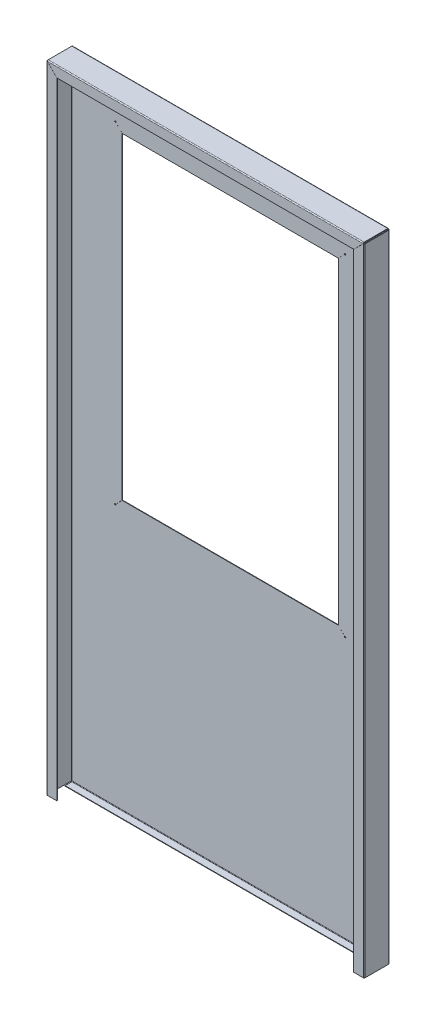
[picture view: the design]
ISO-10303-21;
HEADER;
FILE_DESCRIPTION(('STEP AP214'),'2;1');
FILE_NAME('part.step','',(''),(''),'','','');
FILE_SCHEMA(('AUTOMOTIVE_DESIGN { 1 0 10303 214 1 1 1 1 }'));
ENDSEC;
DATA;
#1=APPLICATION_CONTEXT('core data for automotive mechanical design processes');
#2=APPLICATION_PROTOCOL_DEFINITION('international standard','automotive_design',2000,#1);
#3=PRODUCT_CONTEXT('',#1,'mechanical');
#4=PRODUCT('Part','Part','',(#3));
#5=PRODUCT_RELATED_PRODUCT_CATEGORY('part','',(#4));
#6=PRODUCT_DEFINITION_FORMATION('','',#4);
#7=PRODUCT_DEFINITION_CONTEXT('part definition',#1,'design');
#8=PRODUCT_DEFINITION('design','',#6,#7);
#9=PRODUCT_DEFINITION_SHAPE('','',#8);
#10=(LENGTH_UNIT() NAMED_UNIT(*) SI_UNIT(.MILLI.,.METRE.));
#11=(NAMED_UNIT(*) PLANE_ANGLE_UNIT() SI_UNIT($,.RADIAN.));
#12=(NAMED_UNIT(*) SI_UNIT($,.STERADIAN.) SOLID_ANGLE_UNIT());
#13=UNCERTAINTY_MEASURE_WITH_UNIT(LENGTH_MEASURE(1.E-05),#10,'distance_accuracy_value','');
#14=(GEOMETRIC_REPRESENTATION_CONTEXT(3) GLOBAL_UNCERTAINTY_ASSIGNED_CONTEXT((#13)) GLOBAL_UNIT_ASSIGNED_CONTEXT((#10,
#11,#12)) REPRESENTATION_CONTEXT('',''));
#15=CARTESIAN_POINT('',(0.,0.,0.));
#16=DIRECTION('',(0.,0.,1.));
#17=DIRECTION('',(1.,0.,0.));
#18=AXIS2_PLACEMENT_3D('',#15,#16,#17);
#19=CARTESIAN_POINT('',(0.,1000.,0.75));
#20=DIRECTION('',(0.,0.,-1.));
#21=DIRECTION('',(-1.,0.,0.));
#22=AXIS2_PLACEMENT_3D('',#19,#20,#21);
#23=PLANE('',#22);
#24=DIRECTION('',(0.,1.,0.));
#25=VECTOR('',#24,1.);
#26=CARTESIAN_POINT('',(79.9999999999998,500.,0.750000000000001));
#27=LINE('',#26,#25);
#28=CARTESIAN_POINT('',(79.9999999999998,421.570710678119,0.750000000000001));
#29=VERTEX_POINT('',#28);
#30=CARTESIAN_POINT('',(79.9999999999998,921.429289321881,0.750000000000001));
#31=VERTEX_POINT('',#30);
#32=EDGE_CURVE('E499',#29,#31,#27,.T.);
#33=ORIENTED_EDGE('',*,*,#32,.T.);
#34=DIRECTION('',(0.707106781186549,-0.707106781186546,0.));
#35=VECTOR('',#34,1.);
#36=CARTESIAN_POINT('',(-58.6487222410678,1060.07801156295,0.750000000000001));
#37=LINE('',#36,#35);
#38=CARTESIAN_POINT('',(69.9208670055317,931.508422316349,0.750000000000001));
#39=VERTEX_POINT('',#38);
#40=EDGE_CURVE('E481',#39,#31,#37,.T.);
#41=ORIENTED_EDGE('',*,*,#40,.F.);
#42=CARTESIAN_POINT('',(69.2499999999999,932.25,0.750000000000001));
#43=DIRECTION('',(0.,0.,-1.));
#44=DIRECTION('',(-1.,0.,0.));
#45=AXIS2_PLACEMENT_3D('',#42,#43,#44);
#46=CIRCLE('',#45,0.999999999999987);
#47=CARTESIAN_POINT('',(69.9915776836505,931.579132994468,0.750000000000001));
#48=VERTEX_POINT('',#47);
#49=EDGE_CURVE('E490',#48,#39,#46,.F.);
#50=ORIENTED_EDGE('',*,*,#49,.F.);
#51=DIRECTION('',(0.707106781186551,-0.707106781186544,0.));
#52=VECTOR('',#51,1.);
#53=CARTESIAN_POINT('',(-58.5780115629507,1060.14872224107,0.750000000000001));
#54=LINE('',#53,#52);
#55=CARTESIAN_POINT('',(80.0707106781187,921.5,0.750000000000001));
#56=VERTEX_POINT('',#55);
#57=EDGE_CURVE('E189',#48,#56,#54,.T.);
#58=ORIENTED_EDGE('',*,*,#57,.T.);
#59=DIRECTION('',(1.,0.,0.));
#60=VECTOR('',#59,1.);
#61=CARTESIAN_POINT('',(-618.726733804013,921.5,0.750000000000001));
#62=LINE('',#61,#60);
#63=CARTESIAN_POINT('',(419.929289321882,921.5,0.750000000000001));
#64=VERTEX_POINT('',#63);
#65=EDGE_CURVE('E2033',#56,#64,#62,.T.);
#66=ORIENTED_EDGE('',*,*,#65,.T.);
#67=DIRECTION('',(-0.707106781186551,-0.707106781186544,0.));
#68=VECTOR('',#67,1.);
#69=CARTESIAN_POINT('',(-310.148722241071,191.421988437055,0.750000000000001));
#70=LINE('',#69,#68);
#71=CARTESIAN_POINT('',(430.008422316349,931.579132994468,0.750000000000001));
#72=VERTEX_POINT('',#71);
#73=EDGE_CURVE('E2035',#72,#64,#70,.T.);
#74=ORIENTED_EDGE('',*,*,#73,.F.);
#75=CARTESIAN_POINT('',(430.75,932.25,0.750000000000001));
#76=DIRECTION('',(0.,0.,-1.));
#77=DIRECTION('',(-1.,0.,0.));
#78=AXIS2_PLACEMENT_3D('',#75,#76,#77);
#79=CIRCLE('',#78,0.999999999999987);
#80=CARTESIAN_POINT('',(430.079132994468,931.508422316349,0.750000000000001));
#81=VERTEX_POINT('',#80);
#82=EDGE_CURVE('E2040',#72,#81,#79,.T.);
#83=ORIENTED_EDGE('',*,*,#82,.T.);
#84=DIRECTION('',(-0.707106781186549,-0.707106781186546,0.));
#85=VECTOR('',#84,1.);
#86=CARTESIAN_POINT('',(-310.07801156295,191.351277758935,0.750000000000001));
#87=LINE('',#86,#85);
#88=CARTESIAN_POINT('',(420.,921.429289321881,0.750000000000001));
#89=VERTEX_POINT('',#88);
#90=EDGE_CURVE('E2043',#81,#89,#87,.T.);
#91=ORIENTED_EDGE('',*,*,#90,.T.);
#92=DIRECTION('',(0.,1.,0.));
#93=VECTOR('',#92,1.);
#94=CARTESIAN_POINT('',(420.,500.,0.750000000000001));
#95=LINE('',#94,#93);
#96=CARTESIAN_POINT('',(420.,421.570710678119,0.750000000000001));
#97=VERTEX_POINT('',#96);
#98=EDGE_CURVE('E2046',#97,#89,#95,.T.);
#99=ORIENTED_EDGE('',*,*,#98,.F.);
#100=DIRECTION('',(-0.707106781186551,0.707106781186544,0.));
#101=VECTOR('',#100,1.);
#102=CARTESIAN_POINT('',(-138.578011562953,980.148722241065,0.750000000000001));
#103=LINE('',#102,#101);
#104=CARTESIAN_POINT('',(430.079132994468,411.491577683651,0.750000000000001));
#105=VERTEX_POINT('',#104);
#106=EDGE_CURVE('E2049',#105,#97,#103,.T.);
#107=ORIENTED_EDGE('',*,*,#106,.F.);
#108=CARTESIAN_POINT('',(430.75,410.75,0.750000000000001));
#109=DIRECTION('',(0.,0.,-1.));
#110=DIRECTION('',(-1.,0.,0.));
#111=AXIS2_PLACEMENT_3D('',#108,#109,#110);
#112=CIRCLE('',#111,1.00000000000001);
#113=CARTESIAN_POINT('',(430.008422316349,411.420867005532,0.750000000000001));
#114=VERTEX_POINT('',#113);
#115=EDGE_CURVE('E2052',#114,#105,#112,.F.);
#116=ORIENTED_EDGE('',*,*,#115,.F.);
#117=DIRECTION('',(-0.707106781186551,0.707106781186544,0.));
#118=VECTOR('',#117,1.);
#119=CARTESIAN_POINT('',(-138.648722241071,980.078011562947,0.750000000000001));
#120=LINE('',#119,#118);
#121=CARTESIAN_POINT('',(419.929289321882,421.5,0.750000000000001));
#122=VERTEX_POINT('',#121);
#123=EDGE_CURVE('E2055',#114,#122,#120,.T.);
#124=ORIENTED_EDGE('',*,*,#123,.T.);
#125=DIRECTION('',(1.,0.,0.));
#126=VECTOR('',#125,1.);
#127=CARTESIAN_POINT('',(-618.726733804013,421.5,0.750000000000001));
#128=LINE('',#127,#126);
#129=CARTESIAN_POINT('',(80.0707106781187,421.5,0.750000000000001));
#130=VERTEX_POINT('',#129);
#131=EDGE_CURVE('E2058',#130,#122,#128,.T.);
#132=ORIENTED_EDGE('',*,*,#131,.F.);
#133=DIRECTION('',(0.707106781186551,0.707106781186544,0.));
#134=VECTOR('',#133,1.);
#135=CARTESIAN_POINT('',(-230.078011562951,111.351277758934,0.750000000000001));
#136=LINE('',#135,#134);
#137=CARTESIAN_POINT('',(69.9915776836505,411.420867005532,0.750000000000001));
#138=VERTEX_POINT('',#137);
#139=EDGE_CURVE('E2061',#138,#130,#136,.T.);
#140=ORIENTED_EDGE('',*,*,#139,.F.);
#141=CARTESIAN_POINT('',(69.2499999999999,410.75,0.750000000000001));
#142=DIRECTION('',(0.,0.,-1.));
#143=DIRECTION('',(-1.,0.,0.));
#144=AXIS2_PLACEMENT_3D('',#141,#142,#143);
#145=CIRCLE('',#144,1.00000000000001);
#146=CARTESIAN_POINT('',(69.9208670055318,411.491577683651,0.750000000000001));
#147=VERTEX_POINT('',#146);
#148=EDGE_CURVE('E2064',#138,#147,#145,.T.);
#149=ORIENTED_EDGE('',*,*,#148,.T.);
#150=DIRECTION('',(0.707106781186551,0.707106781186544,0.));
#151=VECTOR('',#150,1.);
#152=CARTESIAN_POINT('',(-230.14872224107,111.421988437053,0.750000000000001));
#153=LINE('',#152,#151);
#154=EDGE_CURVE('E503',#147,#29,#153,.T.);
#155=ORIENTED_EDGE('',*,*,#154,.T.);
#156=EDGE_LOOP('',(#33,#41,#50,#58,#66,#74,#83,#91,#99,#107,#116,#124,#132,#140,#149,#155));
#157=FACE_BOUND('',#156,.T.);
#158=DIRECTION('',(0.,1.,0.));
#159=VECTOR('',#158,1.);
#160=CARTESIAN_POINT('',(498.5,1000.,0.750000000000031));
#161=LINE('',#160,#159);
#162=CARTESIAN_POINT('',(498.5,1000.,0.750000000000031));
#163=VERTEX_POINT('',#162);
#164=CARTESIAN_POINT('',(498.5,0.,0.750000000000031));
#165=VERTEX_POINT('',#164);
#166=EDGE_CURVE('E1001',#163,#165,#161,.F.);
#167=ORIENTED_EDGE('',*,*,#166,.F.);
#168=DIRECTION('',(-1.,0.,0.));
#169=VECTOR('',#168,1.);
#170=CARTESIAN_POINT('',(0.,1000.,0.75));
#171=LINE('',#170,#169);
#172=CARTESIAN_POINT('',(1.5,1000.,0.75));
#173=VERTEX_POINT('',#172);
#174=EDGE_CURVE('E13',#163,#173,#171,.T.);
#175=ORIENTED_EDGE('',*,*,#174,.T.);
#176=DIRECTION('',(0.,-1.,0.));
#177=VECTOR('',#176,1.);
#178=CARTESIAN_POINT('',(1.5,0.,0.75));
#179=LINE('',#178,#177);
#180=CARTESIAN_POINT('',(1.5,0.,0.75));
#181=VERTEX_POINT('',#180);
#182=EDGE_CURVE('E1046',#181,#173,#179,.F.);
#183=ORIENTED_EDGE('',*,*,#182,.F.);
#184=DIRECTION('',(1.,0.,0.));
#185=VECTOR('',#184,1.);
#186=CARTESIAN_POINT('',(0.,0.,0.75));
#187=LINE('',#186,#185);
#188=EDGE_CURVE('E182',#181,#165,#187,.T.);
#189=ORIENTED_EDGE('',*,*,#188,.T.);
#190=EDGE_LOOP('',(#167,#175,#183,#189));
#191=FACE_BOUND('',#190,.T.);
#192=ADVANCED_FACE('F175',(#157,#191),#23,.F.);
#193=CARTESIAN_POINT('',(0.,1000.,0.));
#194=DIRECTION('',(0.,0.,-1.));
#195=DIRECTION('',(-1.,0.,0.));
#196=AXIS2_PLACEMENT_3D('',#193,#194,#195);
#197=PLANE('',#196);
#198=DIRECTION('',(-0.707106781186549,0.707106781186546,0.));
#199=VECTOR('',#198,1.);
#200=CARTESIAN_POINT('',(-58.6487222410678,1060.07801156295,0.));
#201=LINE('',#200,#199);
#202=CARTESIAN_POINT('',(79.9999999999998,921.429289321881,0.));
#203=VERTEX_POINT('',#202);
#204=CARTESIAN_POINT('',(69.9208670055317,931.508422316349,0.));
#205=VERTEX_POINT('',#204);
#206=EDGE_CURVE('E197',#203,#205,#201,.T.);
#207=ORIENTED_EDGE('',*,*,#206,.F.);
#208=DIRECTION('',(0.,-1.,0.));
#209=VECTOR('',#208,1.);
#210=CARTESIAN_POINT('',(79.9999999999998,500.,0.));
#211=LINE('',#210,#209);
#212=CARTESIAN_POINT('',(79.9999999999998,421.570710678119,0.));
#213=VERTEX_POINT('',#212);
#214=EDGE_CURVE('E487',#203,#213,#211,.T.);
#215=ORIENTED_EDGE('',*,*,#214,.T.);
#216=DIRECTION('',(-0.707106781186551,-0.707106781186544,0.));
#217=VECTOR('',#216,1.);
#218=CARTESIAN_POINT('',(-230.14872224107,111.421988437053,0.));
#219=LINE('',#218,#217);
#220=CARTESIAN_POINT('',(69.9208670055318,411.491577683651,0.));
#221=VERTEX_POINT('',#220);
#222=EDGE_CURVE('E544',#213,#221,#219,.T.);
#223=ORIENTED_EDGE('',*,*,#222,.T.);
#224=CARTESIAN_POINT('',(69.2499999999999,410.75,0.));
#225=DIRECTION('',(0.,0.,-1.));
#226=DIRECTION('',(-1.,0.,0.));
#227=AXIS2_PLACEMENT_3D('',#224,#225,#226);
#228=CIRCLE('',#227,1.00000000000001);
#229=CARTESIAN_POINT('',(69.9915776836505,411.420867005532,0.));
#230=VERTEX_POINT('',#229);
#231=EDGE_CURVE('E541',#221,#230,#228,.F.);
#232=ORIENTED_EDGE('',*,*,#231,.T.);
#233=DIRECTION('',(-0.707106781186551,-0.707106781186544,0.));
#234=VECTOR('',#233,1.);
#235=CARTESIAN_POINT('',(-230.078011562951,111.351277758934,0.));
#236=LINE('',#235,#234);
#237=CARTESIAN_POINT('',(80.0707106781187,421.5,0.));
#238=VERTEX_POINT('',#237);
#239=EDGE_CURVE('E538',#238,#230,#236,.T.);
#240=ORIENTED_EDGE('',*,*,#239,.F.);
#241=DIRECTION('',(-1.,0.,0.));
#242=VECTOR('',#241,1.);
#243=CARTESIAN_POINT('',(-618.726733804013,421.5,0.));
#244=LINE('',#243,#242);
#245=CARTESIAN_POINT('',(419.929289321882,421.5,0.));
#246=VERTEX_POINT('',#245);
#247=EDGE_CURVE('E535',#246,#238,#244,.T.);
#248=ORIENTED_EDGE('',*,*,#247,.F.);
#249=DIRECTION('',(0.707106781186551,-0.707106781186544,0.));
#250=VECTOR('',#249,1.);
#251=CARTESIAN_POINT('',(-138.648722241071,980.078011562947,0.));
#252=LINE('',#251,#250);
#253=CARTESIAN_POINT('',(430.008422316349,411.420867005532,0.));
#254=VERTEX_POINT('',#253);
#255=EDGE_CURVE('E532',#246,#254,#252,.T.);
#256=ORIENTED_EDGE('',*,*,#255,.T.);
#257=CARTESIAN_POINT('',(430.75,410.75,0.));
#258=DIRECTION('',(0.,0.,-1.));
#259=DIRECTION('',(-1.,0.,0.));
#260=AXIS2_PLACEMENT_3D('',#257,#258,#259);
#261=CIRCLE('',#260,1.00000000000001);
#262=CARTESIAN_POINT('',(430.079132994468,411.491577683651,0.));
#263=VERTEX_POINT('',#262);
#264=EDGE_CURVE('E529',#263,#254,#261,.T.);
#265=ORIENTED_EDGE('',*,*,#264,.F.);
#266=DIRECTION('',(0.707106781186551,-0.707106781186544,0.));
#267=VECTOR('',#266,1.);
#268=CARTESIAN_POINT('',(-138.578011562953,980.148722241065,0.));
#269=LINE('',#268,#267);
#270=CARTESIAN_POINT('',(420.,421.570710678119,0.));
#271=VERTEX_POINT('',#270);
#272=EDGE_CURVE('E526',#271,#263,#269,.T.);
#273=ORIENTED_EDGE('',*,*,#272,.F.);
#274=DIRECTION('',(0.,-1.,0.));
#275=VECTOR('',#274,1.);
#276=CARTESIAN_POINT('',(420.,500.,0.));
#277=LINE('',#276,#275);
#278=CARTESIAN_POINT('',(420.,921.429289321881,0.));
#279=VERTEX_POINT('',#278);
#280=EDGE_CURVE('E523',#279,#271,#277,.T.);
#281=ORIENTED_EDGE('',*,*,#280,.F.);
#282=DIRECTION('',(0.707106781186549,0.707106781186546,0.));
#283=VECTOR('',#282,1.);
#284=CARTESIAN_POINT('',(-310.07801156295,191.351277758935,0.));
#285=LINE('',#284,#283);
#286=CARTESIAN_POINT('',(430.079132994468,931.508422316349,0.));
#287=VERTEX_POINT('',#286);
#288=EDGE_CURVE('E520',#279,#287,#285,.T.);
#289=ORIENTED_EDGE('',*,*,#288,.T.);
#290=CARTESIAN_POINT('',(430.75,932.25,0.));
#291=DIRECTION('',(0.,0.,-1.));
#292=DIRECTION('',(-1.,0.,0.));
#293=AXIS2_PLACEMENT_3D('',#290,#291,#292);
#294=CIRCLE('',#293,0.999999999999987);
#295=CARTESIAN_POINT('',(430.008422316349,931.579132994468,0.));
#296=VERTEX_POINT('',#295);
#297=EDGE_CURVE('E517',#287,#296,#294,.F.);
#298=ORIENTED_EDGE('',*,*,#297,.T.);
#299=DIRECTION('',(0.707106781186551,0.707106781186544,0.));
#300=VECTOR('',#299,1.);
#301=CARTESIAN_POINT('',(-310.148722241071,191.421988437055,0.));
#302=LINE('',#301,#300);
#303=CARTESIAN_POINT('',(419.929289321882,921.5,0.));
#304=VERTEX_POINT('',#303);
#305=EDGE_CURVE('E514',#304,#296,#302,.T.);
#306=ORIENTED_EDGE('',*,*,#305,.F.);
#307=DIRECTION('',(-1.,0.,0.));
#308=VECTOR('',#307,1.);
#309=CARTESIAN_POINT('',(-618.726733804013,921.5,0.));
#310=LINE('',#309,#308);
#311=CARTESIAN_POINT('',(80.0707106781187,921.5,0.));
#312=VERTEX_POINT('',#311);
#313=EDGE_CURVE('E511',#304,#312,#310,.T.);
#314=ORIENTED_EDGE('',*,*,#313,.T.);
#315=DIRECTION('',(-0.707106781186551,0.707106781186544,0.));
#316=VECTOR('',#315,1.);
#317=CARTESIAN_POINT('',(-58.5780115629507,1060.14872224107,0.));
#318=LINE('',#317,#316);
#319=CARTESIAN_POINT('',(69.9915776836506,931.579132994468,0.));
#320=VERTEX_POINT('',#319);
#321=EDGE_CURVE('E508',#312,#320,#318,.T.);
#322=ORIENTED_EDGE('',*,*,#321,.T.);
#323=CARTESIAN_POINT('',(69.2499999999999,932.25,0.));
#324=DIRECTION('',(0.,0.,-1.));
#325=DIRECTION('',(-1.,0.,0.));
#326=AXIS2_PLACEMENT_3D('',#323,#324,#325);
#327=CIRCLE('',#326,0.999999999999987);
#328=EDGE_CURVE('E501',#205,#320,#327,.T.);
#329=ORIENTED_EDGE('',*,*,#328,.F.);
#330=EDGE_LOOP('',(#207,#215,#223,#232,#240,#248,#256,#265,#273,#281,#289,#298,#306,#314,#322,#329));
#331=FACE_BOUND('',#330,.T.);
#332=DIRECTION('',(-1.,0.,0.));
#333=VECTOR('',#332,1.);
#334=CARTESIAN_POINT('',(0.,1000.,0.));
#335=LINE('',#334,#333);
#336=CARTESIAN_POINT('',(498.5,1000.,0.));
#337=VERTEX_POINT('',#336);
#338=CARTESIAN_POINT('',(1.5,1000.,0.));
#339=VERTEX_POINT('',#338);
#340=EDGE_CURVE('E931',#337,#339,#335,.T.);
#341=ORIENTED_EDGE('',*,*,#340,.F.);
#342=DIRECTION('',(0.,1.,0.));
#343=VECTOR('',#342,1.);
#344=CARTESIAN_POINT('',(498.5,1000.,0.));
#345=LINE('',#344,#343);
#346=CARTESIAN_POINT('',(498.5,0.,0.));
#347=VERTEX_POINT('',#346);
#348=EDGE_CURVE('E934',#337,#347,#345,.F.);
#349=ORIENTED_EDGE('',*,*,#348,.T.);
#350=DIRECTION('',(1.,0.,0.));
#351=VECTOR('',#350,1.);
#352=CARTESIAN_POINT('',(0.,0.,0.));
#353=LINE('',#352,#351);
#354=CARTESIAN_POINT('',(1.5,0.,0.));
#355=VERTEX_POINT('',#354);
#356=EDGE_CURVE('E940',#355,#347,#353,.T.);
#357=ORIENTED_EDGE('',*,*,#356,.F.);
#358=DIRECTION('',(0.,-1.,0.));
#359=VECTOR('',#358,1.);
#360=CARTESIAN_POINT('',(1.5,0.,0.));
#361=LINE('',#360,#359);
#362=EDGE_CURVE('E936',#355,#339,#361,.F.);
#363=ORIENTED_EDGE('',*,*,#362,.T.);
#364=EDGE_LOOP('',(#341,#349,#357,#363));
#365=FACE_BOUND('',#364,.T.);
#366=ADVANCED_FACE('F919',(#331,#365),#197,.T.);
#367=CARTESIAN_POINT('',(1.5,1000.,1.5));
#368=DIRECTION('',(0.,1.,0.));
#369=DIRECTION('',(0.,0.,1.));
#370=AXIS2_PLACEMENT_3D('',#367,#368,#369);
#371=PLANE('',#370);
#372=DIRECTION('',(1.,0.,0.));
#373=VECTOR('',#372,1.);
#374=CARTESIAN_POINT('',(0.,1000.,1.49999999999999));
#375=LINE('',#374,#373);
#376=CARTESIAN_POINT('',(0.749999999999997,1000.,1.5));
#377=VERTEX_POINT('',#376);
#378=CARTESIAN_POINT('',(0.,1000.,1.49999999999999));
#379=VERTEX_POINT('',#378);
#380=EDGE_CURVE('E1008',#377,#379,#375,.F.);
#381=ORIENTED_EDGE('',*,*,#380,.F.);
#382=CARTESIAN_POINT('',(1.5,1000.,1.5));
#383=DIRECTION('',(0.,-1.,0.));
#384=DIRECTION('',(0.,0.,-1.));
#385=AXIS2_PLACEMENT_3D('',#382,#383,#384);
#386=CIRCLE('',#385,0.75);
#387=EDGE_CURVE('E1042',#173,#377,#386,.F.);
#388=ORIENTED_EDGE('',*,*,#387,.F.);
#389=DIRECTION('',(0.,0.,-1.));
#390=VECTOR('',#389,1.);
#391=CARTESIAN_POINT('',(1.5,1000.,0.75));
#392=LINE('',#391,#390);
#393=EDGE_CURVE('E1057',#173,#339,#392,.T.);
#394=ORIENTED_EDGE('',*,*,#393,.T.);
#395=CARTESIAN_POINT('',(1.5,1000.,1.5));
#396=DIRECTION('',(0.,-1.,0.));
#397=DIRECTION('',(0.,0.,-1.));
#398=AXIS2_PLACEMENT_3D('',#395,#396,#397);
#399=CIRCLE('',#398,1.5);
#400=EDGE_CURVE('E1051',#339,#379,#399,.F.);
#401=ORIENTED_EDGE('',*,*,#400,.T.);
#402=EDGE_LOOP('',(#381,#388,#394,#401));
#403=FACE_BOUND('',#402,.T.);
#404=ADVANCED_FACE('F916',(#403),#371,.T.);
#405=CARTESIAN_POINT('',(1.5,0.,1.5));
#406=DIRECTION('',(0.,1.,0.));
#407=DIRECTION('',(0.,0.,1.));
#408=AXIS2_PLACEMENT_3D('',#405,#406,#407);
#409=PLANE('',#408);
#410=CARTESIAN_POINT('',(1.5,0.,1.5));
#411=DIRECTION('',(0.,-1.,0.));
#412=DIRECTION('',(0.,0.,-1.));
#413=AXIS2_PLACEMENT_3D('',#410,#411,#412);
#414=CIRCLE('',#413,0.75);
#415=CARTESIAN_POINT('',(0.749999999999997,0.,1.5));
#416=VERTEX_POINT('',#415);
#417=EDGE_CURVE('E1012',#416,#181,#414,.T.);
#418=ORIENTED_EDGE('',*,*,#417,.F.);
#419=DIRECTION('',(1.,0.,0.));
#420=VECTOR('',#419,1.);
#421=CARTESIAN_POINT('',(0.749999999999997,0.,1.5));
#422=LINE('',#421,#420);
#423=CARTESIAN_POINT('',(0.,0.,1.49999999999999));
#424=VERTEX_POINT('',#423);
#425=EDGE_CURVE('E1035',#416,#424,#422,.F.);
#426=ORIENTED_EDGE('',*,*,#425,.T.);
#427=CARTESIAN_POINT('',(1.5,0.,1.5));
#428=DIRECTION('',(0.,-1.,0.));
#429=DIRECTION('',(0.,0.,-1.));
#430=AXIS2_PLACEMENT_3D('',#427,#428,#429);
#431=CIRCLE('',#430,1.5);
#432=EDGE_CURVE('E1045',#424,#355,#431,.T.);
#433=ORIENTED_EDGE('',*,*,#432,.T.);
#434=DIRECTION('',(0.,0.,-1.));
#435=VECTOR('',#434,1.);
#436=CARTESIAN_POINT('',(1.5,0.,0.75));
#437=LINE('',#436,#435);
#438=EDGE_CURVE('E1054',#181,#355,#437,.T.);
#439=ORIENTED_EDGE('',*,*,#438,.F.);
#440=EDGE_LOOP('',(#418,#426,#433,#439));
#441=FACE_BOUND('',#440,.T.);
#442=ADVANCED_FACE('F912',(#441),#409,.F.);
#443=CARTESIAN_POINT('',(1.5,0.,1.5));
#444=DIRECTION('',(0.,-1.,0.));
#445=DIRECTION('',(-1.,0.,0.));
#446=AXIS2_PLACEMENT_3D('',#443,#444,#445);
#447=CYLINDRICAL_SURFACE('',#446,1.5);
#448=ORIENTED_EDGE('',*,*,#362,.F.);
#449=ORIENTED_EDGE('',*,*,#432,.F.);
#450=DIRECTION('',(0.,-1.,0.));
#451=VECTOR('',#450,1.);
#452=CARTESIAN_POINT('',(0.,1000.,1.49999999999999));
#453=LINE('',#452,#451);
#454=EDGE_CURVE('E1033',#424,#379,#453,.F.);
#455=ORIENTED_EDGE('',*,*,#454,.T.);
#456=ORIENTED_EDGE('',*,*,#400,.F.);
#457=EDGE_LOOP('',(#448,#449,#455,#456));
#458=FACE_BOUND('',#457,.T.);
#459=ADVANCED_FACE('F910',(#458),#447,.T.);
#460=CARTESIAN_POINT('',(1.5,0.,1.5));
#461=DIRECTION('',(0.,-1.,0.));
#462=DIRECTION('',(-1.,0.,0.));
#463=AXIS2_PLACEMENT_3D('',#460,#461,#462);
#464=CYLINDRICAL_SURFACE('',#463,0.75);
#465=ORIENTED_EDGE('',*,*,#182,.T.);
#466=ORIENTED_EDGE('',*,*,#387,.T.);
#467=DIRECTION('',(0.,-1.,0.));
#468=VECTOR('',#467,1.);
#469=CARTESIAN_POINT('',(0.749999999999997,1000.,1.5));
#470=LINE('',#469,#468);
#471=EDGE_CURVE('E1038',#377,#416,#470,.T.);
#472=ORIENTED_EDGE('',*,*,#471,.T.);
#473=ORIENTED_EDGE('',*,*,#417,.T.);
#474=EDGE_LOOP('',(#465,#466,#472,#473));
#475=FACE_BOUND('',#474,.T.);
#476=ADVANCED_FACE('F906',(#475),#464,.F.);
#477=CARTESIAN_POINT('',(0.,1000.,0.749999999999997));
#478=DIRECTION('',(0.,-1.,0.));
#479=DIRECTION('',(0.,0.,-1.));
#480=AXIS2_PLACEMENT_3D('',#477,#478,#479);
#481=PLANE('',#480);
#482=ORIENTED_EDGE('',*,*,#380,.T.);
#483=DIRECTION('',(0.,0.,-1.));
#484=VECTOR('',#483,1.);
#485=CARTESIAN_POINT('',(-1.31838984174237E-13,1000.,38.5));
#486=LINE('',#485,#484);
#487=CARTESIAN_POINT('',(-1.31838984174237E-13,1000.,38.5));
#488=VERTEX_POINT('',#487);
#489=EDGE_CURVE('E1022',#488,#379,#486,.T.);
#490=ORIENTED_EDGE('',*,*,#489,.F.);
#491=DIRECTION('',(1.,0.,0.));
#492=VECTOR('',#491,1.);
#493=CARTESIAN_POINT('',(-1.31803496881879E-13,1000.,38.5));
#494=LINE('',#493,#492);
#495=CARTESIAN_POINT('',(0.749999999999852,1000.,38.5));
#496=VERTEX_POINT('',#495);
#497=EDGE_CURVE('E1013',#488,#496,#494,.T.);
#498=ORIENTED_EDGE('',*,*,#497,.T.);
#499=DIRECTION('',(0.,0.,1.));
#500=VECTOR('',#499,1.);
#501=CARTESIAN_POINT('',(0.75,1000.,0.75));
#502=LINE('',#501,#500);
#503=EDGE_CURVE('E1030',#496,#377,#502,.F.);
#504=ORIENTED_EDGE('',*,*,#503,.T.);
#505=EDGE_LOOP('',(#482,#490,#498,#504));
#506=FACE_BOUND('',#505,.T.);
#507=ADVANCED_FACE('F902',(#506),#481,.F.);
#508=CARTESIAN_POINT('',(-1.31838984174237E-13,0.,38.5));
#509=DIRECTION('',(0.,1.,0.));
#510=DIRECTION('',(0.,0.,1.));
#511=AXIS2_PLACEMENT_3D('',#508,#509,#510);
#512=PLANE('',#511);
#513=ORIENTED_EDGE('',*,*,#425,.F.);
#514=DIRECTION('',(0.,0.,-1.));
#515=VECTOR('',#514,1.);
#516=CARTESIAN_POINT('',(0.749999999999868,0.,38.5));
#517=LINE('',#516,#515);
#518=CARTESIAN_POINT('',(0.749999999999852,0.,38.5));
#519=VERTEX_POINT('',#518);
#520=EDGE_CURVE('E1027',#416,#519,#517,.F.);
#521=ORIENTED_EDGE('',*,*,#520,.T.);
#522=DIRECTION('',(1.,0.,0.));
#523=VECTOR('',#522,1.);
#524=CARTESIAN_POINT('',(-1.31838984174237E-13,0.,38.5));
#525=LINE('',#524,#523);
#526=CARTESIAN_POINT('',(-1.47668335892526E-13,0.,38.5));
#527=VERTEX_POINT('',#526);
#528=EDGE_CURVE('E1010',#527,#519,#525,.T.);
#529=ORIENTED_EDGE('',*,*,#528,.F.);
#530=DIRECTION('',(0.,0.,1.));
#531=VECTOR('',#530,1.);
#532=CARTESIAN_POINT('',(-1.31838984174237E-13,0.,38.5));
#533=LINE('',#532,#531);
#534=EDGE_CURVE('E1019',#424,#527,#533,.T.);
#535=ORIENTED_EDGE('',*,*,#534,.F.);
#536=EDGE_LOOP('',(#513,#521,#529,#535));
#537=FACE_BOUND('',#536,.T.);
#538=ADVANCED_FACE('F898',(#537),#512,.F.);
#539=CARTESIAN_POINT('',(-1.31838984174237E-13,1000.,38.5));
#540=DIRECTION('',(1.,0.,0.));
#541=DIRECTION('',(0.,0.,-1.));
#542=AXIS2_PLACEMENT_3D('',#539,#540,#541);
#543=PLANE('',#542);
#544=ORIENTED_EDGE('',*,*,#454,.F.);
#545=ORIENTED_EDGE('',*,*,#534,.T.);
#546=DIRECTION('',(0.,1.,0.));
#547=VECTOR('',#546,1.);
#548=CARTESIAN_POINT('',(-1.31838984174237E-13,1000.,38.5));
#549=LINE('',#548,#547);
#550=EDGE_CURVE('E1016',#527,#488,#549,.T.);
#551=ORIENTED_EDGE('',*,*,#550,.T.);
#552=ORIENTED_EDGE('',*,*,#489,.T.);
#553=EDGE_LOOP('',(#544,#545,#551,#552));
#554=FACE_BOUND('',#553,.T.);
#555=ADVANCED_FACE('F894',(#554),#543,.F.);
#556=CARTESIAN_POINT('',(0.749999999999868,1000.,38.5));
#557=DIRECTION('',(1.,0.,0.));
#558=DIRECTION('',(0.,0.,-1.));
#559=AXIS2_PLACEMENT_3D('',#556,#557,#558);
#560=PLANE('',#559);
#561=ORIENTED_EDGE('',*,*,#520,.F.);
#562=ORIENTED_EDGE('',*,*,#471,.F.);
#563=ORIENTED_EDGE('',*,*,#503,.F.);
#564=DIRECTION('',(0.,-1.,0.));
#565=VECTOR('',#564,1.);
#566=CARTESIAN_POINT('',(0.749999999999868,1000.,38.5));
#567=LINE('',#566,#565);
#568=EDGE_CURVE('E1025',#519,#496,#567,.F.);
#569=ORIENTED_EDGE('',*,*,#568,.F.);
#570=EDGE_LOOP('',(#561,#562,#563,#569));
#571=FACE_BOUND('',#570,.T.);
#572=ADVANCED_FACE('F887',(#571),#560,.T.);
#573=CARTESIAN_POINT('',(498.5,0.,1.5));
#574=DIRECTION('',(0.,-1.,0.));
#575=DIRECTION('',(0.,0.,-1.));
#576=AXIS2_PLACEMENT_3D('',#573,#574,#575);
#577=PLANE('',#576);
#578=DIRECTION('',(-1.,0.,0.));
#579=VECTOR('',#578,1.);
#580=CARTESIAN_POINT('',(500.,0.,1.5));
#581=LINE('',#580,#579);
#582=CARTESIAN_POINT('',(499.25,0.,1.5));
#583=VERTEX_POINT('',#582);
#584=CARTESIAN_POINT('',(500.,0.,1.5));
#585=VERTEX_POINT('',#584);
#586=EDGE_CURVE('E957',#583,#585,#581,.F.);
#587=ORIENTED_EDGE('',*,*,#586,.F.);
#588=CARTESIAN_POINT('',(498.5,0.,1.5));
#589=DIRECTION('',(0.,1.,0.));
#590=DIRECTION('',(0.,0.,1.));
#591=AXIS2_PLACEMENT_3D('',#588,#589,#590);
#592=CIRCLE('',#591,0.749999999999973);
#593=EDGE_CURVE('E997',#165,#583,#592,.F.);
#594=ORIENTED_EDGE('',*,*,#593,.F.);
#595=DIRECTION('',(0.,0.,-1.));
#596=VECTOR('',#595,1.);
#597=CARTESIAN_POINT('',(498.5,0.,0.750000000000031));
#598=LINE('',#597,#596);
#599=EDGE_CURVE('E952',#165,#347,#598,.T.);
#600=ORIENTED_EDGE('',*,*,#599,.T.);
#601=CARTESIAN_POINT('',(498.5,0.,1.5));
#602=DIRECTION('',(0.,1.,0.));
#603=DIRECTION('',(0.,0.,1.));
#604=AXIS2_PLACEMENT_3D('',#601,#602,#603);
#605=CIRCLE('',#604,1.49999999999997);
#606=EDGE_CURVE('E953',#347,#585,#605,.F.);
#607=ORIENTED_EDGE('',*,*,#606,.T.);
#608=EDGE_LOOP('',(#587,#594,#600,#607));
#609=FACE_BOUND('',#608,.T.);
#610=ADVANCED_FACE('F884',(#609),#577,.T.);
#611=CARTESIAN_POINT('',(498.5,1000.,1.5));
#612=DIRECTION('',(0.,-1.,0.));
#613=DIRECTION('',(0.,0.,-1.));
#614=AXIS2_PLACEMENT_3D('',#611,#612,#613);
#615=PLANE('',#614);
#616=CARTESIAN_POINT('',(498.5,1000.,1.5));
#617=DIRECTION('',(0.,1.,0.));
#618=DIRECTION('',(0.,0.,1.));
#619=AXIS2_PLACEMENT_3D('',#616,#617,#618);
#620=CIRCLE('',#619,0.749999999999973);
#621=CARTESIAN_POINT('',(499.25,1000.,1.5));
#622=VERTEX_POINT('',#621);
#623=EDGE_CURVE('E970',#622,#163,#620,.T.);
#624=ORIENTED_EDGE('',*,*,#623,.F.);
#625=DIRECTION('',(-1.,0.,0.));
#626=VECTOR('',#625,1.);
#627=CARTESIAN_POINT('',(499.25,1000.,1.5));
#628=LINE('',#627,#626);
#629=CARTESIAN_POINT('',(500.,1000.,1.5));
#630=VERTEX_POINT('',#629);
#631=EDGE_CURVE('E993',#622,#630,#628,.F.);
#632=ORIENTED_EDGE('',*,*,#631,.T.);
#633=CARTESIAN_POINT('',(498.5,1000.,1.5));
#634=DIRECTION('',(0.,1.,0.));
#635=DIRECTION('',(0.,0.,1.));
#636=AXIS2_PLACEMENT_3D('',#633,#634,#635);
#637=CIRCLE('',#636,1.49999999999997);
#638=EDGE_CURVE('E1000',#630,#337,#637,.T.);
#639=ORIENTED_EDGE('',*,*,#638,.T.);
#640=DIRECTION('',(0.,0.,-1.));
#641=VECTOR('',#640,1.);
#642=CARTESIAN_POINT('',(498.5,1000.,0.750000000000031));
#643=LINE('',#642,#641);
#644=EDGE_CURVE('E944',#163,#337,#643,.T.);
#645=ORIENTED_EDGE('',*,*,#644,.F.);
#646=EDGE_LOOP('',(#624,#632,#639,#645));
#647=FACE_BOUND('',#646,.T.);
#648=ADVANCED_FACE('F880',(#647),#615,.F.);
#649=CARTESIAN_POINT('',(498.5,1000.,1.5));
#650=DIRECTION('',(0.,1.,0.));
#651=DIRECTION('',(1.,0.,0.));
#652=AXIS2_PLACEMENT_3D('',#649,#650,#651);
#653=CYLINDRICAL_SURFACE('',#652,1.49999999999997);
#654=ORIENTED_EDGE('',*,*,#348,.F.);
#655=ORIENTED_EDGE('',*,*,#638,.F.);
#656=DIRECTION('',(0.,1.,0.));
#657=VECTOR('',#656,1.);
#658=CARTESIAN_POINT('',(500.,0.,1.5));
#659=LINE('',#658,#657);
#660=EDGE_CURVE('E991',#630,#585,#659,.F.);
#661=ORIENTED_EDGE('',*,*,#660,.T.);
#662=ORIENTED_EDGE('',*,*,#606,.F.);
#663=EDGE_LOOP('',(#654,#655,#661,#662));
#664=FACE_BOUND('',#663,.T.);
#665=ADVANCED_FACE('F878',(#664),#653,.T.);
#666=CARTESIAN_POINT('',(498.5,1000.,1.5));
#667=DIRECTION('',(0.,1.,0.));
#668=DIRECTION('',(1.,0.,0.));
#669=AXIS2_PLACEMENT_3D('',#666,#667,#668);
#670=CYLINDRICAL_SURFACE('',#669,0.749999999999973);
#671=ORIENTED_EDGE('',*,*,#166,.T.);
#672=ORIENTED_EDGE('',*,*,#593,.T.);
#673=DIRECTION('',(0.,1.,0.));
#674=VECTOR('',#673,1.);
#675=CARTESIAN_POINT('',(499.25,0.,1.5));
#676=LINE('',#675,#674);
#677=EDGE_CURVE('E961',#583,#622,#676,.T.);
#678=ORIENTED_EDGE('',*,*,#677,.T.);
#679=ORIENTED_EDGE('',*,*,#623,.T.);
#680=EDGE_LOOP('',(#671,#672,#678,#679));
#681=FACE_BOUND('',#680,.T.);
#682=ADVANCED_FACE('F874',(#681),#670,.F.);
#683=CARTESIAN_POINT('',(500.,0.,0.749999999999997));
#684=DIRECTION('',(0.,1.,0.));
#685=DIRECTION('',(0.,0.,1.));
#686=AXIS2_PLACEMENT_3D('',#683,#684,#685);
#687=PLANE('',#686);
#688=ORIENTED_EDGE('',*,*,#586,.T.);
#689=DIRECTION('',(0.,0.,-1.));
#690=VECTOR('',#689,1.);
#691=CARTESIAN_POINT('',(500.,0.,38.5));
#692=LINE('',#691,#690);
#693=CARTESIAN_POINT('',(500.,0.,38.5));
#694=VERTEX_POINT('',#693);
#695=EDGE_CURVE('E980',#694,#585,#692,.T.);
#696=ORIENTED_EDGE('',*,*,#695,.F.);
#697=DIRECTION('',(-1.,0.,0.));
#698=VECTOR('',#697,1.);
#699=CARTESIAN_POINT('',(500.,0.,38.5));
#700=LINE('',#699,#698);
#701=CARTESIAN_POINT('',(499.25,0.,38.5));
#702=VERTEX_POINT('',#701);
#703=EDGE_CURVE('E971',#694,#702,#700,.T.);
#704=ORIENTED_EDGE('',*,*,#703,.T.);
#705=DIRECTION('',(0.,0.,1.));
#706=VECTOR('',#705,1.);
#707=CARTESIAN_POINT('',(499.25,0.,0.75));
#708=LINE('',#707,#706);
#709=EDGE_CURVE('E988',#702,#583,#708,.F.);
#710=ORIENTED_EDGE('',*,*,#709,.T.);
#711=EDGE_LOOP('',(#688,#696,#704,#710));
#712=FACE_BOUND('',#711,.T.);
#713=ADVANCED_FACE('F870',(#712),#687,.F.);
#714=CARTESIAN_POINT('',(500.,1000.,38.5));
#715=DIRECTION('',(0.,-1.,0.));
#716=DIRECTION('',(0.,0.,-1.));
#717=AXIS2_PLACEMENT_3D('',#714,#715,#716);
#718=PLANE('',#717);
#719=ORIENTED_EDGE('',*,*,#631,.F.);
#720=DIRECTION('',(0.,0.,-1.));
#721=VECTOR('',#720,1.);
#722=CARTESIAN_POINT('',(499.25,1000.,38.5));
#723=LINE('',#722,#721);
#724=CARTESIAN_POINT('',(499.25,1000.,38.5));
#725=VERTEX_POINT('',#724);
#726=EDGE_CURVE('E985',#622,#725,#723,.F.);
#727=ORIENTED_EDGE('',*,*,#726,.T.);
#728=DIRECTION('',(-1.,0.,0.));
#729=VECTOR('',#728,1.);
#730=CARTESIAN_POINT('',(500.,1000.,38.5));
#731=LINE('',#730,#729);
#732=CARTESIAN_POINT('',(500.,1000.,38.5));
#733=VERTEX_POINT('',#732);
#734=EDGE_CURVE('E968',#733,#725,#731,.T.);
#735=ORIENTED_EDGE('',*,*,#734,.F.);
#736=DIRECTION('',(0.,0.,1.));
#737=VECTOR('',#736,1.);
#738=CARTESIAN_POINT('',(500.,1000.,38.5));
#739=LINE('',#738,#737);
#740=EDGE_CURVE('E977',#630,#733,#739,.T.);
#741=ORIENTED_EDGE('',*,*,#740,.F.);
#742=EDGE_LOOP('',(#719,#727,#735,#741));
#743=FACE_BOUND('',#742,.T.);
#744=ADVANCED_FACE('F866',(#743),#718,.F.);
#745=CARTESIAN_POINT('',(500.,0.,38.5));
#746=DIRECTION('',(-1.,0.,0.));
#747=DIRECTION('',(0.,0.,1.));
#748=AXIS2_PLACEMENT_3D('',#745,#746,#747);
#749=PLANE('',#748);
#750=ORIENTED_EDGE('',*,*,#660,.F.);
#751=ORIENTED_EDGE('',*,*,#740,.T.);
#752=DIRECTION('',(0.,-1.,0.));
#753=VECTOR('',#752,1.);
#754=CARTESIAN_POINT('',(500.,0.,38.5));
#755=LINE('',#754,#753);
#756=EDGE_CURVE('E974',#733,#694,#755,.T.);
#757=ORIENTED_EDGE('',*,*,#756,.T.);
#758=ORIENTED_EDGE('',*,*,#695,.T.);
#759=EDGE_LOOP('',(#750,#751,#757,#758));
#760=FACE_BOUND('',#759,.T.);
#761=ADVANCED_FACE('F862',(#760),#749,.F.);
#762=CARTESIAN_POINT('',(499.25,0.,38.5));
#763=DIRECTION('',(-1.,0.,0.));
#764=DIRECTION('',(0.,0.,1.));
#765=AXIS2_PLACEMENT_3D('',#762,#763,#764);
#766=PLANE('',#765);
#767=ORIENTED_EDGE('',*,*,#726,.F.);
#768=ORIENTED_EDGE('',*,*,#677,.F.);
#769=ORIENTED_EDGE('',*,*,#709,.F.);
#770=DIRECTION('',(0.,1.,0.));
#771=VECTOR('',#770,1.);
#772=CARTESIAN_POINT('',(499.25,0.,38.5));
#773=LINE('',#772,#771);
#774=EDGE_CURVE('E983',#725,#702,#773,.F.);
#775=ORIENTED_EDGE('',*,*,#774,.F.);
#776=EDGE_LOOP('',(#767,#768,#769,#775));
#777=FACE_BOUND('',#776,.T.);
#778=ADVANCED_FACE('F855',(#777),#766,.T.);
#779=CARTESIAN_POINT('',(498.5,1000.,1.50000000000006));
#780=DIRECTION('',(1.,0.,0.));
#781=DIRECTION('',(0.,0.,-1.));
#782=AXIS2_PLACEMENT_3D('',#779,#780,#781);
#783=PLANE('',#782);
#784=DIRECTION('',(0.,1.,0.));
#785=VECTOR('',#784,1.);
#786=CARTESIAN_POINT('',(498.5,1001.5,1.50000000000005));
#787=LINE('',#786,#785);
#788=CARTESIAN_POINT('',(498.5,1000.75,1.50000000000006));
#789=VERTEX_POINT('',#788);
#790=CARTESIAN_POINT('',(498.5,1001.5,1.50000000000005));
#791=VERTEX_POINT('',#790);
#792=EDGE_CURVE('E1092',#789,#791,#787,.T.);
#793=ORIENTED_EDGE('',*,*,#792,.F.);
#794=CARTESIAN_POINT('',(498.5,1000.,1.50000000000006));
#795=DIRECTION('',(-1.,0.,0.));
#796=DIRECTION('',(0.,0.,1.));
#797=AXIS2_PLACEMENT_3D('',#794,#795,#796);
#798=CIRCLE('',#797,0.750000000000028);
#799=EDGE_CURVE('E948',#163,#789,#798,.F.);
#800=ORIENTED_EDGE('',*,*,#799,.F.);
#801=ORIENTED_EDGE('',*,*,#644,.T.);
#802=CARTESIAN_POINT('',(498.5,1000.,1.50000000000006));
#803=DIRECTION('',(-1.,0.,0.));
#804=DIRECTION('',(0.,0.,1.));
#805=AXIS2_PLACEMENT_3D('',#802,#803,#804);
#806=CIRCLE('',#805,1.50000000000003);
#807=EDGE_CURVE('E945',#337,#791,#806,.F.);
#808=ORIENTED_EDGE('',*,*,#807,.T.);
#809=EDGE_LOOP('',(#793,#800,#801,#808));
#810=FACE_BOUND('',#809,.T.);
#811=ADVANCED_FACE('F852',(#810),#783,.T.);
#812=CARTESIAN_POINT('',(1.5,1000.,1.50000000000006));
#813=DIRECTION('',(1.,0.,0.));
#814=DIRECTION('',(0.,0.,-1.));
#815=AXIS2_PLACEMENT_3D('',#812,#813,#814);
#816=PLANE('',#815);
#817=CARTESIAN_POINT('',(1.5,1000.,1.50000000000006));
#818=DIRECTION('',(-1.,0.,0.));
#819=DIRECTION('',(0.,0.,1.));
#820=AXIS2_PLACEMENT_3D('',#817,#818,#819);
#821=CIRCLE('',#820,0.750000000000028);
#822=CARTESIAN_POINT('',(1.5,1000.75,1.50000000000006));
#823=VERTEX_POINT('',#822);
#824=EDGE_CURVE('E965',#823,#173,#821,.T.);
#825=ORIENTED_EDGE('',*,*,#824,.F.);
#826=DIRECTION('',(0.,1.,0.));
#827=VECTOR('',#826,1.);
#828=CARTESIAN_POINT('',(1.5,1000.75,1.50000000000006));
#829=LINE('',#828,#827);
#830=CARTESIAN_POINT('',(1.5,1001.5,1.50000000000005));
#831=VERTEX_POINT('',#830);
#832=EDGE_CURVE('E1116',#823,#831,#829,.T.);
#833=ORIENTED_EDGE('',*,*,#832,.T.);
#834=CARTESIAN_POINT('',(1.5,1000.,1.50000000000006));
#835=DIRECTION('',(-1.,0.,0.));
#836=DIRECTION('',(0.,0.,1.));
#837=AXIS2_PLACEMENT_3D('',#834,#835,#836);
#838=CIRCLE('',#837,1.50000000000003);
#839=EDGE_CURVE('E958',#831,#339,#838,.T.);
#840=ORIENTED_EDGE('',*,*,#839,.T.);
#841=ORIENTED_EDGE('',*,*,#393,.F.);
#842=EDGE_LOOP('',(#825,#833,#840,#841));
#843=FACE_BOUND('',#842,.T.);
#844=ADVANCED_FACE('F848',(#843),#816,.F.);
#845=CARTESIAN_POINT('',(1.49999999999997,1000.,1.50000000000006));
#846=DIRECTION('',(-1.,0.,0.));
#847=DIRECTION('',(0.,1.,0.));
#848=AXIS2_PLACEMENT_3D('',#845,#846,#847);
#849=CYLINDRICAL_SURFACE('',#848,1.50000000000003);
#850=ORIENTED_EDGE('',*,*,#340,.T.);
#851=ORIENTED_EDGE('',*,*,#839,.F.);
#852=DIRECTION('',(-1.,0.,0.));
#853=VECTOR('',#852,1.);
#854=CARTESIAN_POINT('',(1.5,1001.5,1.50000000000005));
#855=LINE('',#854,#853);
#856=EDGE_CURVE('E956',#791,#831,#855,.T.);
#857=ORIENTED_EDGE('',*,*,#856,.F.);
#858=ORIENTED_EDGE('',*,*,#807,.F.);
#859=EDGE_LOOP('',(#850,#851,#857,#858));
#860=FACE_BOUND('',#859,.T.);
#861=ADVANCED_FACE('F846',(#860),#849,.T.);
#862=CARTESIAN_POINT('',(1.49999999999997,1000.,1.50000000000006));
#863=DIRECTION('',(-1.,0.,0.));
#864=DIRECTION('',(0.,1.,0.));
#865=AXIS2_PLACEMENT_3D('',#862,#863,#864);
#866=CYLINDRICAL_SURFACE('',#865,0.750000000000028);
#867=ORIENTED_EDGE('',*,*,#174,.F.);
#868=ORIENTED_EDGE('',*,*,#799,.T.);
#869=DIRECTION('',(1.,0.,0.));
#870=VECTOR('',#869,1.);
#871=CARTESIAN_POINT('',(498.5,1000.75,1.50000000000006));
#872=LINE('',#871,#870);
#873=EDGE_CURVE('E1119',#789,#823,#872,.F.);
#874=ORIENTED_EDGE('',*,*,#873,.T.);
#875=ORIENTED_EDGE('',*,*,#824,.T.);
#876=EDGE_LOOP('',(#867,#868,#874,#875));
#877=FACE_BOUND('',#876,.T.);
#878=ADVANCED_FACE('F839',(#877),#866,.F.);
#879=CARTESIAN_POINT('',(1.5,1001.5,0.749999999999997));
#880=DIRECTION('',(-1.,0.,0.));
#881=DIRECTION('',(0.,0.,1.));
#882=AXIS2_PLACEMENT_3D('',#879,#880,#881);
#883=PLANE('',#882);
#884=DIRECTION('',(0.,0.,-1.));
#885=VECTOR('',#884,1.);
#886=CARTESIAN_POINT('',(1.5,1001.5,0.749999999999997));
#887=LINE('',#886,#885);
#888=CARTESIAN_POINT('',(1.49999999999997,1001.5,38.5));
#889=VERTEX_POINT('',#888);
#890=EDGE_CURVE('E1100',#889,#831,#887,.T.);
#891=ORIENTED_EDGE('',*,*,#890,.T.);
#892=ORIENTED_EDGE('',*,*,#832,.F.);
#893=DIRECTION('',(0.,0.,1.));
#894=VECTOR('',#893,1.);
#895=CARTESIAN_POINT('',(1.5,1000.75,0.75));
#896=LINE('',#895,#894);
#897=CARTESIAN_POINT('',(1.5,1000.75,38.5));
#898=VERTEX_POINT('',#897);
#899=EDGE_CURVE('E1108',#898,#823,#896,.F.);
#900=ORIENTED_EDGE('',*,*,#899,.F.);
#901=DIRECTION('',(0.,-1.,0.));
#902=VECTOR('',#901,1.);
#903=CARTESIAN_POINT('',(1.5,1001.5,38.5));
#904=LINE('',#903,#902);
#905=EDGE_CURVE('E1094',#889,#898,#904,.T.);
#906=ORIENTED_EDGE('',*,*,#905,.F.);
#907=EDGE_LOOP('',(#891,#892,#900,#906));
#908=FACE_BOUND('',#907,.T.);
#909=ADVANCED_FACE('F836',(#908),#883,.T.);
#910=CARTESIAN_POINT('',(498.5,1001.5,38.5));
#911=DIRECTION('',(1.,0.,0.));
#912=DIRECTION('',(0.,1.,0.));
#913=AXIS2_PLACEMENT_3D('',#910,#911,#912);
#914=PLANE('',#913);
#915=DIRECTION('',(0.,0.,-1.));
#916=VECTOR('',#915,1.);
#917=CARTESIAN_POINT('',(498.5,1000.75,0.75));
#918=LINE('',#917,#916);
#919=CARTESIAN_POINT('',(498.5,1000.75,38.5));
#920=VERTEX_POINT('',#919);
#921=EDGE_CURVE('E1113',#789,#920,#918,.F.);
#922=ORIENTED_EDGE('',*,*,#921,.F.);
#923=ORIENTED_EDGE('',*,*,#792,.T.);
#924=DIRECTION('',(0.,0.,1.));
#925=VECTOR('',#924,1.);
#926=CARTESIAN_POINT('',(498.5,1001.5,38.5));
#927=LINE('',#926,#925);
#928=CARTESIAN_POINT('',(498.5,1001.5,38.5));
#929=VERTEX_POINT('',#928);
#930=EDGE_CURVE('E1106',#791,#929,#927,.T.);
#931=ORIENTED_EDGE('',*,*,#930,.T.);
#932=DIRECTION('',(0.,-1.,0.));
#933=VECTOR('',#932,1.);
#934=CARTESIAN_POINT('',(498.5,1001.5,38.5));
#935=LINE('',#934,#933);
#936=EDGE_CURVE('E1097',#929,#920,#935,.T.);
#937=ORIENTED_EDGE('',*,*,#936,.T.);
#938=EDGE_LOOP('',(#922,#923,#931,#937));
#939=FACE_BOUND('',#938,.T.);
#940=ADVANCED_FACE('F834',(#939),#914,.T.);
#941=CARTESIAN_POINT('',(1.5,1001.5,0.749999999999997));
#942=DIRECTION('',(0.,1.,0.));
#943=DIRECTION('',(0.,0.,1.));
#944=AXIS2_PLACEMENT_3D('',#941,#942,#943);
#945=PLANE('',#944);
#946=ORIENTED_EDGE('',*,*,#930,.F.);
#947=ORIENTED_EDGE('',*,*,#856,.T.);
#948=ORIENTED_EDGE('',*,*,#890,.F.);
#949=DIRECTION('',(-1.,0.,0.));
#950=VECTOR('',#949,1.);
#951=CARTESIAN_POINT('',(1.5,1001.5,38.5));
#952=LINE('',#951,#950);
#953=EDGE_CURVE('E1103',#929,#889,#952,.T.);
#954=ORIENTED_EDGE('',*,*,#953,.F.);
#955=EDGE_LOOP('',(#946,#947,#948,#954));
#956=FACE_BOUND('',#955,.T.);
#957=ADVANCED_FACE('F830',(#956),#945,.T.);
#958=CARTESIAN_POINT('',(1.5,1000.75,0.75));
#959=DIRECTION('',(0.,1.,0.));
#960=DIRECTION('',(0.,0.,1.));
#961=AXIS2_PLACEMENT_3D('',#958,#959,#960);
#962=PLANE('',#961);
#963=ORIENTED_EDGE('',*,*,#873,.F.);
#964=ORIENTED_EDGE('',*,*,#921,.T.);
#965=DIRECTION('',(1.,0.,0.));
#966=VECTOR('',#965,1.);
#967=CARTESIAN_POINT('',(1.5,1000.75,38.5));
#968=LINE('',#967,#966);
#969=EDGE_CURVE('E1111',#920,#898,#968,.F.);
#970=ORIENTED_EDGE('',*,*,#969,.T.);
#971=ORIENTED_EDGE('',*,*,#899,.T.);
#972=EDGE_LOOP('',(#963,#964,#970,#971));
#973=FACE_BOUND('',#972,.T.);
#974=ADVANCED_FACE('F823',(#973),#962,.F.);
#975=CARTESIAN_POINT('',(1.49999999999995,0.,1.50000000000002));
#976=DIRECTION('',(-1.,0.,0.));
#977=DIRECTION('',(0.,0.,1.));
#978=AXIS2_PLACEMENT_3D('',#975,#976,#977);
#979=PLANE('',#978);
#980=DIRECTION('',(0.,1.,0.));
#981=VECTOR('',#980,1.);
#982=CARTESIAN_POINT('',(1.5,-1.5,1.49999999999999));
#983=LINE('',#982,#981);
#984=CARTESIAN_POINT('',(1.49999999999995,-0.75,1.50000000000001));
#985=VERTEX_POINT('',#984);
#986=CARTESIAN_POINT('',(1.49999999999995,-1.5,1.50000000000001));
#987=VERTEX_POINT('',#986);
#988=EDGE_CURVE('E1223',#985,#987,#983,.F.);
#989=ORIENTED_EDGE('',*,*,#988,.F.);
#990=CARTESIAN_POINT('',(1.49999999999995,0.,1.50000000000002));
#991=DIRECTION('',(1.,0.,0.));
#992=DIRECTION('',(0.,0.,-1.));
#993=AXIS2_PLACEMENT_3D('',#990,#991,#992);
#994=CIRCLE('',#993,0.75);
#995=EDGE_CURVE('E1081',#181,#985,#994,.F.);
#996=ORIENTED_EDGE('',*,*,#995,.F.);
#997=ORIENTED_EDGE('',*,*,#438,.T.);
#998=CARTESIAN_POINT('',(1.49999999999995,0.,1.50000000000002));
#999=DIRECTION('',(1.,0.,0.));
#1000=DIRECTION('',(0.,0.,-1.));
#1001=AXIS2_PLACEMENT_3D('',#998,#999,#1000);
#1002=CIRCLE('',#1001,1.5);
#1003=EDGE_CURVE('E1089',#355,#987,#1002,.F.);
#1004=ORIENTED_EDGE('',*,*,#1003,.T.);
#1005=EDGE_LOOP('',(#989,#996,#997,#1004));
#1006=FACE_BOUND('',#1005,.T.);
#1007=ADVANCED_FACE('F820',(#1006),#979,.T.);
#1008=CARTESIAN_POINT('',(498.5,0.,1.50000000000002));
#1009=DIRECTION('',(-1.,0.,0.));
#1010=DIRECTION('',(0.,0.,1.));
#1011=AXIS2_PLACEMENT_3D('',#1008,#1009,#1010);
#1012=PLANE('',#1011);
#1013=CARTESIAN_POINT('',(498.5,0.,1.50000000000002));
#1014=DIRECTION('',(1.,0.,0.));
#1015=DIRECTION('',(0.,0.,-1.));
#1016=AXIS2_PLACEMENT_3D('',#1013,#1014,#1015);
#1017=CIRCLE('',#1016,0.75);
#1018=CARTESIAN_POINT('',(498.5,-0.75,1.50000000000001));
#1019=VERTEX_POINT('',#1018);
#1020=EDGE_CURVE('E1074',#1019,#165,#1017,.T.);
#1021=ORIENTED_EDGE('',*,*,#1020,.F.);
#1022=DIRECTION('',(0.,1.,0.));
#1023=VECTOR('',#1022,1.);
#1024=CARTESIAN_POINT('',(498.5,-0.75,1.50000000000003));
#1025=LINE('',#1024,#1023);
#1026=CARTESIAN_POINT('',(498.5,-1.5,1.50000000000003));
#1027=VERTEX_POINT('',#1026);
#1028=EDGE_CURVE('E1247',#1019,#1027,#1025,.F.);
#1029=ORIENTED_EDGE('',*,*,#1028,.T.);
#1030=CARTESIAN_POINT('',(498.5,0.,1.50000000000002));
#1031=DIRECTION('',(1.,0.,0.));
#1032=DIRECTION('',(0.,0.,-1.));
#1033=AXIS2_PLACEMENT_3D('',#1030,#1031,#1032);
#1034=CIRCLE('',#1033,1.5);
#1035=EDGE_CURVE('E1076',#1027,#347,#1034,.T.);
#1036=ORIENTED_EDGE('',*,*,#1035,.T.);
#1037=ORIENTED_EDGE('',*,*,#599,.F.);
#1038=EDGE_LOOP('',(#1021,#1029,#1036,#1037));
#1039=FACE_BOUND('',#1038,.T.);
#1040=ADVANCED_FACE('F816',(#1039),#1012,.F.);
#1041=CARTESIAN_POINT('',(498.5,0.,1.50000000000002));
#1042=DIRECTION('',(1.,0.,0.));
#1043=DIRECTION('',(0.,-1.,0.));
#1044=AXIS2_PLACEMENT_3D('',#1041,#1042,#1043);
#1045=CYLINDRICAL_SURFACE('',#1044,1.5);
#1046=ORIENTED_EDGE('',*,*,#356,.T.);
#1047=ORIENTED_EDGE('',*,*,#1035,.F.);
#1048=DIRECTION('',(1.,0.,0.));
#1049=VECTOR('',#1048,1.);
#1050=CARTESIAN_POINT('',(1.5,-1.5,1.49999999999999));
#1051=LINE('',#1050,#1049);
#1052=EDGE_CURVE('E1243',#1027,#987,#1051,.F.);
#1053=ORIENTED_EDGE('',*,*,#1052,.T.);
#1054=ORIENTED_EDGE('',*,*,#1003,.F.);
#1055=EDGE_LOOP('',(#1046,#1047,#1053,#1054));
#1056=FACE_BOUND('',#1055,.T.);
#1057=ADVANCED_FACE('F814',(#1056),#1045,.T.);
#1058=CARTESIAN_POINT('',(498.5,0.,1.50000000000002));
#1059=DIRECTION('',(1.,0.,0.));
#1060=DIRECTION('',(0.,-1.,0.));
#1061=AXIS2_PLACEMENT_3D('',#1058,#1059,#1060);
#1062=CYLINDRICAL_SURFACE('',#1061,0.75);
#1063=ORIENTED_EDGE('',*,*,#188,.F.);
#1064=ORIENTED_EDGE('',*,*,#995,.T.);
#1065=DIRECTION('',(1.,0.,0.));
#1066=VECTOR('',#1065,1.);
#1067=CARTESIAN_POINT('',(1.5,-0.75,1.5));
#1068=LINE('',#1067,#1066);
#1069=EDGE_CURVE('E1080',#985,#1019,#1068,.T.);
#1070=ORIENTED_EDGE('',*,*,#1069,.T.);
#1071=ORIENTED_EDGE('',*,*,#1020,.T.);
#1072=EDGE_LOOP('',(#1063,#1064,#1070,#1071));
#1073=FACE_BOUND('',#1072,.T.);
#1074=ADVANCED_FACE('F810',(#1073),#1062,.F.);
#1075=CARTESIAN_POINT('',(1.5,-1.5,0.749999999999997));
#1076=DIRECTION('',(1.,0.,0.));
#1077=DIRECTION('',(0.,0.,-1.));
#1078=AXIS2_PLACEMENT_3D('',#1075,#1076,#1077);
#1079=PLANE('',#1078);
#1080=ORIENTED_EDGE('',*,*,#988,.T.);
#1081=DIRECTION('',(0.,0.,-1.));
#1082=VECTOR('',#1081,1.);
#1083=CARTESIAN_POINT('',(1.5,-1.5,0.749999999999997));
#1084=LINE('',#1083,#1082);
#1085=CARTESIAN_POINT('',(1.5,-1.50000000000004,12.));
#1086=VERTEX_POINT('',#1085);
#1087=EDGE_CURVE('E1257',#1086,#987,#1084,.T.);
#1088=ORIENTED_EDGE('',*,*,#1087,.F.);
#1089=DIRECTION('',(0.,1.,0.));
#1090=VECTOR('',#1089,1.);
#1091=CARTESIAN_POINT('',(1.5,-1.50000000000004,12.));
#1092=LINE('',#1091,#1090);
#1093=CARTESIAN_POINT('',(1.5,-0.750000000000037,12.));
#1094=VERTEX_POINT('',#1093);
#1095=EDGE_CURVE('E1086',#1086,#1094,#1092,.T.);
#1096=ORIENTED_EDGE('',*,*,#1095,.T.);
#1097=DIRECTION('',(0.,0.,1.));
#1098=VECTOR('',#1097,1.);
#1099=CARTESIAN_POINT('',(1.5,-0.749999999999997,0.75));
#1100=LINE('',#1099,#1098);
#1101=EDGE_CURVE('E1246',#1094,#985,#1100,.F.);
#1102=ORIENTED_EDGE('',*,*,#1101,.T.);
#1103=EDGE_LOOP('',(#1080,#1088,#1096,#1102));
#1104=FACE_BOUND('',#1103,.T.);
#1105=ADVANCED_FACE('F806',(#1104),#1079,.F.);
#1106=CARTESIAN_POINT('',(498.5,-1.50000000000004,12.));
#1107=DIRECTION('',(-1.,0.,0.));
#1108=DIRECTION('',(0.,-1.,0.));
#1109=AXIS2_PLACEMENT_3D('',#1106,#1107,#1108);
#1110=PLANE('',#1109);
#1111=ORIENTED_EDGE('',*,*,#1028,.F.);
#1112=DIRECTION('',(0.,0.,-1.));
#1113=VECTOR('',#1112,1.);
#1114=CARTESIAN_POINT('',(498.5,-0.750000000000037,12.));
#1115=LINE('',#1114,#1113);
#1116=CARTESIAN_POINT('',(498.5,-0.750000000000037,12.));
#1117=VERTEX_POINT('',#1116);
#1118=EDGE_CURVE('E1250',#1019,#1117,#1115,.F.);
#1119=ORIENTED_EDGE('',*,*,#1118,.T.);
#1120=DIRECTION('',(0.,1.,0.));
#1121=VECTOR('',#1120,1.);
#1122=CARTESIAN_POINT('',(498.5,-1.50000000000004,12.));
#1123=LINE('',#1122,#1121);
#1124=CARTESIAN_POINT('',(498.5,-1.50000000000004,12.));
#1125=VERTEX_POINT('',#1124);
#1126=EDGE_CURVE('E1082',#1125,#1117,#1123,.T.);
#1127=ORIENTED_EDGE('',*,*,#1126,.F.);
#1128=DIRECTION('',(0.,0.,1.));
#1129=VECTOR('',#1128,1.);
#1130=CARTESIAN_POINT('',(498.5,-1.5,0.749999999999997));
#1131=LINE('',#1130,#1129);
#1132=EDGE_CURVE('E1262',#1027,#1125,#1131,.T.);
#1133=ORIENTED_EDGE('',*,*,#1132,.F.);
#1134=EDGE_LOOP('',(#1111,#1119,#1127,#1133));
#1135=FACE_BOUND('',#1134,.T.);
#1136=ADVANCED_FACE('F799',(#1135),#1110,.F.);
#1137=CARTESIAN_POINT('',(1.5,-1.5,0.749999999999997));
#1138=DIRECTION('',(0.,1.,0.));
#1139=DIRECTION('',(0.,0.,1.));
#1140=AXIS2_PLACEMENT_3D('',#1137,#1138,#1139);
#1141=PLANE('',#1140);
#1142=ORIENTED_EDGE('',*,*,#1052,.F.);
#1143=ORIENTED_EDGE('',*,*,#1132,.T.);
#1144=DIRECTION('',(-1.,0.,0.));
#1145=VECTOR('',#1144,1.);
#1146=CARTESIAN_POINT('',(1.5,-1.50000000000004,12.));
#1147=LINE('',#1146,#1145);
#1148=EDGE_CURVE('E1260',#1125,#1086,#1147,.T.);
#1149=ORIENTED_EDGE('',*,*,#1148,.T.);
#1150=ORIENTED_EDGE('',*,*,#1087,.T.);
#1151=EDGE_LOOP('',(#1142,#1143,#1149,#1150));
#1152=FACE_BOUND('',#1151,.T.);
#1153=ADVANCED_FACE('F795',(#1152),#1141,.F.);
#1154=CARTESIAN_POINT('',(1.5,-0.749999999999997,0.75));
#1155=DIRECTION('',(0.,1.,0.));
#1156=DIRECTION('',(0.,0.,1.));
#1157=AXIS2_PLACEMENT_3D('',#1154,#1155,#1156);
#1158=PLANE('',#1157);
#1159=ORIENTED_EDGE('',*,*,#1118,.F.);
#1160=ORIENTED_EDGE('',*,*,#1069,.F.);
#1161=ORIENTED_EDGE('',*,*,#1101,.F.);
#1162=DIRECTION('',(1.,0.,0.));
#1163=VECTOR('',#1162,1.);
#1164=CARTESIAN_POINT('',(1.5,-0.750000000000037,12.));
#1165=LINE('',#1164,#1163);
#1166=EDGE_CURVE('E1263',#1117,#1094,#1165,.F.);
#1167=ORIENTED_EDGE('',*,*,#1166,.F.);
#1168=EDGE_LOOP('',(#1159,#1160,#1161,#1167));
#1169=FACE_BOUND('',#1168,.T.);
#1170=ADVANCED_FACE('F792',(#1169),#1158,.T.);
#1171=CARTESIAN_POINT('',(1.5,-1.50000000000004,12.));
#1172=DIRECTION('',(0.,0.,-1.));
#1173=DIRECTION('',(0.,1.,0.));
#1174=AXIS2_PLACEMENT_3D('',#1171,#1172,#1173);
#1175=PLANE('',#1174);
#1176=ORIENTED_EDGE('',*,*,#1166,.T.);
#1177=ORIENTED_EDGE('',*,*,#1095,.F.);
#1178=ORIENTED_EDGE('',*,*,#1148,.F.);
#1179=ORIENTED_EDGE('',*,*,#1126,.T.);
#1180=EDGE_LOOP('',(#1176,#1177,#1178,#1179));
#1181=FACE_BOUND('',#1180,.T.);
#1182=ADVANCED_FACE('F782',(#1181),#1175,.F.);
#1183=CARTESIAN_POINT('',(-0.00750000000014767,1000.,38.5));
#1184=CARTESIAN_POINT('',(-0.00750000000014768,999.994106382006,38.6973668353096));
#1185=CARTESIAN_POINT('',(0.0317361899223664,999.98821488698,38.8945849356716));
#1186=CARTESIAN_POINT('',(0.18276701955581,999.97642977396,39.2592056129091));
#1187=CARTESIAN_POINT('',(0.294502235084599,999.970537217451,39.4264291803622));
#1188=CARTESIAN_POINT('',(0.573570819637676,999.958752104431,39.7054977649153));
#1189=CARTESIAN_POINT('',(0.740794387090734,999.952859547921,39.8172329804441));
#1190=CARTESIAN_POINT('',(1.10541506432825,999.941074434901,39.9682638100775));
#1191=CARTESIAN_POINT('',(1.3026331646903,999.935182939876,40.0075));
#1192=CARTESIAN_POINT('',(1.49999999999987,999.929289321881,40.0075));
#1193=CARTESIAN_POINT('',(-1.47668335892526E-13,1000.,38.5));
#1194=CARTESIAN_POINT('',(-1.47678589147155E-13,999.994106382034,38.6963849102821));
#1195=CARTESIAN_POINT('',(0.0390409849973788,999.98821488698,38.8926218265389));
#1196=CARTESIAN_POINT('',(0.189320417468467,999.97642977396,39.2554284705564));
#1197=CARTESIAN_POINT('',(0.300499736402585,999.970537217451,39.4218200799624));
#1198=CARTESIAN_POINT('',(0.578179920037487,999.958752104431,39.6995002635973));
#1199=CARTESIAN_POINT('',(0.744571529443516,999.952859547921,39.8106795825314));
#1200=CARTESIAN_POINT('',(1.10737817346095,999.941074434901,39.9609590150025));
#1201=CARTESIAN_POINT('',(1.30361508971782,999.935182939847,40.));
#1202=CARTESIAN_POINT('',(1.49999999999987,999.929289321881,40.));
#1203=CARTESIAN_POINT('',(0.749999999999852,1000.,38.5));
#1204=CARTESIAN_POINT('',(0.749999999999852,999.994106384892,38.5981924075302));
#1205=CARTESIAN_POINT('',(0.769520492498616,999.98821488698,38.6963109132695));
#1206=CARTESIAN_POINT('',(0.844660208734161,999.97642977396,38.8777142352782));
#1207=CARTESIAN_POINT('',(0.90024986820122,999.97053721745,38.9609100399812));
#1208=CARTESIAN_POINT('',(1.03908996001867,999.958752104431,39.0997501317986));
#1209=CARTESIAN_POINT('',(1.12228576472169,999.952859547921,39.1553397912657));
#1210=CARTESIAN_POINT('',(1.3036890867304,999.941074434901,39.2304795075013));
#1211=CARTESIAN_POINT('',(1.40180759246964,999.935182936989,39.25));
#1212=CARTESIAN_POINT('',(1.49999999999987,999.929289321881,39.25));
#1213=CARTESIAN_POINT('',(0.757574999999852,1000.,38.5));
#1214=CARTESIAN_POINT('',(0.757574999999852,999.994106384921,38.5972006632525));
#1215=CARTESIAN_POINT('',(0.776898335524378,999.98821488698,38.6943281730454));
#1216=CARTESIAN_POINT('',(0.851279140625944,999.97642977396,38.8738993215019));
#1217=CARTESIAN_POINT('',(0.906307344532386,999.97053721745,38.9562548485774));
#1218=CARTESIAN_POINT('',(1.04374515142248,999.958752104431,39.0936926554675));
#1219=CARTESIAN_POINT('',(1.12610067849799,999.952859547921,39.1487208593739));
#1220=CARTESIAN_POINT('',(1.30567182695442,999.941074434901,39.2231016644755));
#1221=CARTESIAN_POINT('',(1.40279933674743,999.93518293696,39.242425));
#1222=CARTESIAN_POINT('',(1.49999999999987,999.929289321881,39.242425));
#1223=B_SPLINE_SURFACE_WITH_KNOTS('',1,3,((#1183,#1184,#1185,#1186,#1187,#1188,#1189,#1190,
#1191,#1192),(#1193,#1194,#1195,#1196,#1197,#1198,#1199,#1200,#1201,#1202),(#1203,#1204,#1205,
#1206,#1207,#1208,#1209,#1210,#1211,#1212),(#1213,#1214,#1215,#1216,#1217,#1218,#1219,#1220,
#1221,#1222)),.UNSPECIFIED.,.F.,.F.,.F.,(2,1,1,2),(4,2,2,2,4),(-0.01,0.,1.,1.0101),(0.,0.25,0.5,
0.75,1.),.UNSPECIFIED.);
#1224=DIRECTION('',(0.,0.,-1.));
#1225=VECTOR('',#1224,1.);
#1226=CARTESIAN_POINT('',(1.49999999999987,999.929289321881,39.25));
#1227=LINE('',#1226,#1225);
#1228=CARTESIAN_POINT('',(1.49999999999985,999.929289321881,40.));
#1229=VERTEX_POINT('',#1228);
#1230=CARTESIAN_POINT('',(1.49999999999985,999.929289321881,39.25));
#1231=VERTEX_POINT('',#1230);
#1232=EDGE_CURVE('E722',#1229,#1231,#1227,.T.);
#1233=CARTESIAN_POINT('',(0.749999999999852,1000.,38.5));
#1234=CARTESIAN_POINT('',(0.74999973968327,999.999263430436,38.5122718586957));
#1235=CARTESIAN_POINT('',(0.750301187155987,999.998526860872,38.5245436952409));
#1236=CARTESIAN_POINT('',(0.751505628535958,999.997053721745,38.5490578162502));
#1237=CARTESIAN_POINT('',(0.752408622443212,999.996317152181,38.5613001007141));
#1238=CARTESIAN_POINT('',(0.754814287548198,999.994844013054,38.5857256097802));
#1239=CARTESIAN_POINT('',(0.756316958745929,999.99410744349,38.5979088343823));
#1240=CARTESIAN_POINT('',(0.759918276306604,999.992634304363,38.6221868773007));
#1241=CARTESIAN_POINT('',(0.762016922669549,999.991897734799,38.6342816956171));
#1242=CARTESIAN_POINT('',(0.766805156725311,999.990424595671,38.6583537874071));
#1243=CARTESIAN_POINT('',(0.76949474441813,999.989688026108,38.6703310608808));
#1244=CARTESIAN_POINT('',(0.775458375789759,999.98821488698,38.6941392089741));
#1245=CARTESIAN_POINT('',(0.77873241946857,999.987478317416,38.7059700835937));
#1246=CARTESIAN_POINT('',(0.785857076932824,999.986005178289,38.729456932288));
#1247=CARTESIAN_POINT('',(0.789707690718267,999.985268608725,38.7411129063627));
#1248=CARTESIAN_POINT('',(0.797976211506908,999.983795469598,38.7642218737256));
#1249=CARTESIAN_POINT('',(0.802394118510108,999.983058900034,38.7756748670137));
#1250=CARTESIAN_POINT('',(0.811786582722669,999.981585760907,38.7983502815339));
#1251=CARTESIAN_POINT('',(0.816761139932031,999.980849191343,38.8095727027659));
#1252=CARTESIAN_POINT('',(0.827254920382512,999.979376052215,38.8317599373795));
#1253=CARTESIAN_POINT('',(0.832774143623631,999.978639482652,38.8427247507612));
#1254=CARTESIAN_POINT('',(0.844343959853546,999.977166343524,38.8643703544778));
#1255=CARTESIAN_POINT('',(0.850394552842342,999.97642977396,38.8750511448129));
#1256=CARTESIAN_POINT('',(0.863012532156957,999.974956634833,38.896102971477));
#1257=CARTESIAN_POINT('',(0.869579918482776,999.974220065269,38.9064740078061));
#1258=CARTESIAN_POINT('',(0.883215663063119,999.972746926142,38.9268813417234));
#1259=CARTESIAN_POINT('',(0.890284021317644,999.972010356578,38.9369176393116));
#1260=CARTESIAN_POINT('',(0.904904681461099,999.97053721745,38.9566313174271));
#1261=CARTESIAN_POINT('',(0.912456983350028,999.969800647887,38.9663086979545));
#1262=CARTESIAN_POINT('',(0.928027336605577,999.968327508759,38.985281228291));
#1263=CARTESIAN_POINT('',(0.936045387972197,999.967590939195,38.9945763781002));
#1264=CARTESIAN_POINT('',(0.952527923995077,999.966117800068,39.0127620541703));
#1265=CARTESIAN_POINT('',(0.960992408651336,999.965381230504,39.0216525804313));
#1266=CARTESIAN_POINT('',(0.978347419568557,999.963908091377,39.0390075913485));
#1267=CARTESIAN_POINT('',(0.987237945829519,999.963171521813,39.0474720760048));
#1268=CARTESIAN_POINT('',(1.00542362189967,999.961698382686,39.0639546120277));
#1269=CARTESIAN_POINT('',(1.01471877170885,999.960961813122,39.0719726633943));
#1270=CARTESIAN_POINT('',(1.0336913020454,999.959488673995,39.0875430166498));
#1271=CARTESIAN_POINT('',(1.04336868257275,999.958752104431,39.0950953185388));
#1272=CARTESIAN_POINT('',(1.06308236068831,999.957278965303,39.1097159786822));
#1273=CARTESIAN_POINT('',(1.07311865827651,999.956542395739,39.1167843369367));
#1274=CARTESIAN_POINT('',(1.0935259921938,999.955069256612,39.1304200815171));
#1275=CARTESIAN_POINT('',(1.10389702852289,999.954332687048,39.1369874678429));
#1276=CARTESIAN_POINT('',(1.124948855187,999.952859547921,39.1496054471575));
#1277=CARTESIAN_POINT('',(1.13562964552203,999.952122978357,39.1556560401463));
#1278=CARTESIAN_POINT('',(1.15727524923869,999.95064983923,39.1672258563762));
#1279=CARTESIAN_POINT('',(1.16824006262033,999.949913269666,39.1727450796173));
#1280=CARTESIAN_POINT('',(1.19042729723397,999.948440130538,39.1832388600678));
#1281=CARTESIAN_POINT('',(1.20164971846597,999.947703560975,39.1882134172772));
#1282=CARTESIAN_POINT('',(1.22432513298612,999.946230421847,39.1976058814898));
#1283=CARTESIAN_POINT('',(1.23577812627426,999.945493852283,39.202023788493));
#1284=CARTESIAN_POINT('',(1.25888709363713,999.944020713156,39.2102923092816));
#1285=CARTESIAN_POINT('',(1.27054306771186,999.943284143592,39.214142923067));
#1286=CARTESIAN_POINT('',(1.29402991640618,999.941811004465,39.2212675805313));
#1287=CARTESIAN_POINT('',(1.30586079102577,999.941074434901,39.2245416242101));
#1288=CARTESIAN_POINT('',(1.32966893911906,999.939601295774,39.2305052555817));
#1289=CARTESIAN_POINT('',(1.34164621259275,999.93886472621,39.2331948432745));
#1290=CARTESIAN_POINT('',(1.36571830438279,999.937391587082,39.2379830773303));
#1291=CARTESIAN_POINT('',(1.37781312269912,999.936655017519,39.2400817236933));
#1292=CARTESIAN_POINT('',(1.40209116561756,999.935181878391,39.2436830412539));
#1293=CARTESIAN_POINT('',(1.41427439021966,999.934445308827,39.2451857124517));
#1294=CARTESIAN_POINT('',(1.43869989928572,999.9329721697,39.2475913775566));
#1295=CARTESIAN_POINT('',(1.45094218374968,999.932235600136,39.2484943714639));
#1296=CARTESIAN_POINT('',(1.47545630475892,999.930762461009,39.2496988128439));
#1297=CARTESIAN_POINT('',(1.4877281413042,999.930025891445,39.2500002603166));
#1298=CARTESIAN_POINT('',(1.49999999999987,999.929289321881,39.25));
#1299=B_SPLINE_CURVE_WITH_KNOTS('',3,(#1233,#1234,#1235,#1236,#1237,#1238,#1239,#1240,#1241,
#1242,#1243,#1244,#1245,#1246,#1247,#1248,#1249,#1250,#1251,#1252,#1253,#1254,#1255,#1256,#1257,
#1258,#1259,#1260,#1261,#1262,#1263,#1264,#1265,#1266,#1267,#1268,#1269,#1270,#1271,#1272,#1273,
#1274,#1275,#1276,#1277,#1278,#1279,#1280,#1281,#1282,#1283,#1284,#1285,#1286,#1287,#1288,#1289,
#1290,#1291,#1292,#1293,#1294,#1295,#1296,#1297,#1298),.UNSPECIFIED.,.F.,.F.,(4,2,2,2,2,2,2,2,2,
2,2,2,2,2,2,2,2,2,2,2,2,2,2,2,2,2,2,2,2,2,2,2,4),(0.,0.0368781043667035,0.0737562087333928,
0.110634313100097,0.1475124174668,0.1843905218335,0.221268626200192,0.258146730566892,
0.295024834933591,0.331902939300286,0.368781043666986,0.405659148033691,0.442537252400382,
0.479415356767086,0.516293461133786,0.553171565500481,0.590049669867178,0.626927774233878,
0.663805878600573,0.700683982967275,0.737562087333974,0.77444019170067,0.81131829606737,
0.848196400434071,0.885074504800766,0.921952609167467,0.958830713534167,0.995708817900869,
1.03258692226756,1.06946502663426,1.10634313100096,1.14322123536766,1.18009933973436),.UNSPECIFIED.);
#1300=EDGE_CURVE('E746',#496,#1231,#1299,.T.);
#1301=CARTESIAN_POINT('',(-1.47668335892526E-13,1000.,38.5));
#1302=CARTESIAN_POINT('',(-5.20633310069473E-07,999.999263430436,38.5245437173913));
#1303=CARTESIAN_POINT('',(0.00060237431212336,999.998526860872,38.5490873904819));
#1304=CARTESIAN_POINT('',(0.0030112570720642,999.997053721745,38.5981156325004));
#1305=CARTESIAN_POINT('',(0.00481724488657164,999.996317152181,38.6226002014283));
#1306=CARTESIAN_POINT('',(0.0096285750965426,999.994844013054,38.6714512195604));
#1307=CARTESIAN_POINT('',(0.012633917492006,999.99410744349,38.6958176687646));
#1308=CARTESIAN_POINT('',(0.0198365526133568,999.992634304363,38.7443737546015));
#1309=CARTESIAN_POINT('',(0.0240338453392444,999.991897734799,38.7685633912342));
#1310=CARTESIAN_POINT('',(0.0336103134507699,999.990424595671,38.8167075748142));
#1311=CARTESIAN_POINT('',(0.0389894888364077,999.989688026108,38.8406621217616));
#1312=CARTESIAN_POINT('',(0.0509167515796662,999.98821488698,38.8882784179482));
#1313=CARTESIAN_POINT('',(0.0574648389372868,999.987478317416,38.9119401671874));
#1314=CARTESIAN_POINT('',(0.0717141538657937,999.986005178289,38.958913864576));
#1315=CARTESIAN_POINT('',(0.07941538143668,999.985268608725,38.9822258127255));
#1316=CARTESIAN_POINT('',(0.0959524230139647,999.983795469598,39.0284437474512));
#1317=CARTESIAN_POINT('',(0.104788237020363,999.983058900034,39.0513497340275));
#1318=CARTESIAN_POINT('',(0.123573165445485,999.981585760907,39.0967005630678));
#1319=CARTESIAN_POINT('',(0.133522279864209,999.980849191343,39.1191454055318));
#1320=CARTESIAN_POINT('',(0.15450984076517,999.979376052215,39.1635198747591));
#1321=CARTESIAN_POINT('',(0.165548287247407,999.978639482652,39.1854495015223));
#1322=CARTESIAN_POINT('',(0.188687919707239,999.977166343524,39.2287407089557));
#1323=CARTESIAN_POINT('',(0.200789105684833,999.97642977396,39.2501022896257));
#1324=CARTESIAN_POINT('',(0.226025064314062,999.974956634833,39.292205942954));
#1325=CARTESIAN_POINT('',(0.239159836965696,999.974220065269,39.3129480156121));
#1326=CARTESIAN_POINT('',(0.266431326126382,999.972746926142,39.3537626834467));
#1327=CARTESIAN_POINT('',(0.280568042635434,999.972010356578,39.3738352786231));
#1328=CARTESIAN_POINT('',(0.309809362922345,999.97053721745,39.4132626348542));
#1329=CARTESIAN_POINT('',(0.324913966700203,999.969800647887,39.4326173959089));
#1330=CARTESIAN_POINT('',(0.356054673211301,999.968327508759,39.470562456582));
#1331=CARTESIAN_POINT('',(0.372090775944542,999.967590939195,39.4891527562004));
#1332=CARTESIAN_POINT('',(0.405055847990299,999.966117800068,39.5255241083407));
#1333=CARTESIAN_POINT('',(0.421984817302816,999.965381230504,39.5433051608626));
#1334=CARTESIAN_POINT('',(0.456694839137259,999.963908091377,39.5780151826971));
#1335=CARTESIAN_POINT('',(0.474475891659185,999.963171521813,39.5949441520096));
#1336=CARTESIAN_POINT('',(0.51084724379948,999.961698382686,39.6279092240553));
#1337=CARTESIAN_POINT('',(0.529437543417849,999.960961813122,39.6439453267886));
#1338=CARTESIAN_POINT('',(0.567382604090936,999.959488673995,39.6750860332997));
#1339=CARTESIAN_POINT('',(0.586737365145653,999.958752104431,39.6901906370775));
#1340=CARTESIAN_POINT('',(0.626164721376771,999.957278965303,39.7194319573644));
#1341=CARTESIAN_POINT('',(0.646237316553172,999.956542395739,39.7335686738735));
#1342=CARTESIAN_POINT('',(0.687051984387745,999.955069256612,39.7608401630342));
#1343=CARTESIAN_POINT('',(0.707794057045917,999.954332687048,39.7739749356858));
#1344=CARTESIAN_POINT('',(0.749897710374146,999.952859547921,39.799210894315));
#1345=CARTESIAN_POINT('',(0.771259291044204,999.952122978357,39.8113120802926));
#1346=CARTESIAN_POINT('',(0.814550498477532,999.95064983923,39.8344517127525));
#1347=CARTESIAN_POINT('',(0.836480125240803,999.949913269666,39.8454901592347));
#1348=CARTESIAN_POINT('',(0.88085459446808,999.948440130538,39.8664777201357));
#1349=CARTESIAN_POINT('',(0.903299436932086,999.947703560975,39.8764268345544));
#1350=CARTESIAN_POINT('',(0.94865026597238,999.946230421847,39.8952117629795));
#1351=CARTESIAN_POINT('',(0.971556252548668,999.945493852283,39.9040475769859));
#1352=CARTESIAN_POINT('',(1.01777418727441,999.944020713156,39.9205846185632));
#1353=CARTESIAN_POINT('',(1.04108613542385,999.943284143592,39.9282858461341));
#1354=CARTESIAN_POINT('',(1.08805983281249,999.941811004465,39.9425351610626));
#1355=CARTESIAN_POINT('',(1.11172158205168,999.941074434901,39.9490832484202));
#1356=CARTESIAN_POINT('',(1.15933787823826,999.939601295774,39.9610105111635));
#1357=CARTESIAN_POINT('',(1.18329242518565,999.93886472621,39.9663896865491));
#1358=CARTESIAN_POINT('',(1.23143660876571,999.937391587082,39.9759661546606));
#1359=CARTESIAN_POINT('',(1.25562624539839,999.936655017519,39.9801634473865));
#1360=CARTESIAN_POINT('',(1.30418233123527,999.935181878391,39.9873660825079));
#1361=CARTESIAN_POINT('',(1.32854878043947,999.934445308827,39.9903714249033));
#1362=CARTESIAN_POINT('',(1.37739979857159,999.9329721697,39.9951827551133));
#1363=CARTESIAN_POINT('',(1.40188436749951,999.932235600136,39.9969887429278));
#1364=CARTESIAN_POINT('',(1.45091260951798,999.930762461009,39.9993976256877));
#1365=CARTESIAN_POINT('',(1.47545628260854,999.930025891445,40.0000005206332));
#1366=CARTESIAN_POINT('',(1.49999999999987,999.929289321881,40.));
#1367=B_SPLINE_CURVE_WITH_KNOTS('',3,(#1301,#1302,#1303,#1304,#1305,#1306,#1307,#1308,#1309,
#1310,#1311,#1312,#1313,#1314,#1315,#1316,#1317,#1318,#1319,#1320,#1321,#1322,#1323,#1324,#1325,
#1326,#1327,#1328,#1329,#1330,#1331,#1332,#1333,#1334,#1335,#1336,#1337,#1338,#1339,#1340,#1341,
#1342,#1343,#1344,#1345,#1346,#1347,#1348,#1349,#1350,#1351,#1352,#1353,#1354,#1355,#1356,#1357,
#1358,#1359,#1360,#1361,#1362,#1363,#1364,#1365,#1366),.UNSPECIFIED.,.F.,.F.,(4,2,2,2,2,2,2,2,2,
2,2,2,2,2,2,2,2,2,2,2,2,2,2,2,2,2,2,2,2,2,2,2,4),(0.,0.0736568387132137,0.14731367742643,
0.220970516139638,0.294627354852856,0.368284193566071,0.441941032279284,0.515597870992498,
0.589254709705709,0.662911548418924,0.736568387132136,0.810225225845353,0.883882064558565,
0.95753890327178,1.03119574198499,1.1048525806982,1.17850941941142,1.25216625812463,
1.32582309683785,1.39947993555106,1.47313677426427,1.54679361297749,1.6204504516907,
1.69410729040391,1.76776412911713,1.84142096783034,1.91507780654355,1.98873464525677,
2.06239148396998,2.1360483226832,2.20970516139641,2.28336200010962,2.35701883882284),.UNSPECIFIED.);
#1368=EDGE_CURVE('E750',#488,#1229,#1367,.T.);
#1369=ORIENTED_EDGE('',*,*,#1232,.T.);
#1370=ORIENTED_EDGE('',*,*,#1300,.F.);
#1371=ORIENTED_EDGE('',*,*,#497,.F.);
#1372=ORIENTED_EDGE('',*,*,#1368,.T.);
#1373=EDGE_LOOP('',(#1369,#1370,#1371,#1372));
#1374=FACE_BOUND('',#1373,.T.);
#1375=ADVANCED_FACE('F777',(#1374),#1223,.F.);
#1376=CARTESIAN_POINT('',(1.49999999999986,0.,38.5));
#1377=DIRECTION('',(0.,1.,0.));
#1378=DIRECTION('',(0.,0.,1.));
#1379=AXIS2_PLACEMENT_3D('',#1376,#1377,#1378);
#1380=PLANE('',#1379);
#1381=CARTESIAN_POINT('',(1.49999999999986,0.,38.5));
#1382=DIRECTION('',(0.,-1.,0.));
#1383=DIRECTION('',(0.,0.,-1.));
#1384=AXIS2_PLACEMENT_3D('',#1381,#1382,#1383);
#1385=CIRCLE('',#1384,0.750000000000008);
#1386=CARTESIAN_POINT('',(1.49999999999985,0.,39.25));
#1387=VERTEX_POINT('',#1386);
#1388=EDGE_CURVE('E724',#1387,#519,#1385,.T.);
#1389=ORIENTED_EDGE('',*,*,#1388,.F.);
#1390=DIRECTION('',(0.,0.,1.));
#1391=VECTOR('',#1390,1.);
#1392=CARTESIAN_POINT('',(1.49999999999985,0.,39.25));
#1393=LINE('',#1392,#1391);
#1394=CARTESIAN_POINT('',(1.49999999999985,0.,40.));
#1395=VERTEX_POINT('',#1394);
#1396=EDGE_CURVE('E740',#1387,#1395,#1393,.T.);
#1397=ORIENTED_EDGE('',*,*,#1396,.T.);
#1398=CARTESIAN_POINT('',(1.49999999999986,0.,38.5));
#1399=DIRECTION('',(0.,-1.,0.));
#1400=DIRECTION('',(0.,0.,-1.));
#1401=AXIS2_PLACEMENT_3D('',#1398,#1399,#1400);
#1402=CIRCLE('',#1401,1.50000000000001);
#1403=EDGE_CURVE('E747',#1395,#527,#1402,.T.);
#1404=ORIENTED_EDGE('',*,*,#1403,.T.);
#1405=ORIENTED_EDGE('',*,*,#528,.T.);
#1406=EDGE_LOOP('',(#1389,#1397,#1404,#1405));
#1407=FACE_BOUND('',#1406,.T.);
#1408=ADVANCED_FACE('F770',(#1407),#1380,.F.);
#1409=CARTESIAN_POINT('',(1.49999999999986,0.,38.5));
#1410=DIRECTION('',(0.,-1.,0.));
#1411=DIRECTION('',(0.,0.,1.));
#1412=AXIS2_PLACEMENT_3D('',#1409,#1410,#1411);
#1413=CYLINDRICAL_SURFACE('',#1412,1.50000000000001);
#1414=ORIENTED_EDGE('',*,*,#550,.F.);
#1415=ORIENTED_EDGE('',*,*,#1403,.F.);
#1416=DIRECTION('',(0.,-1.,0.));
#1417=VECTOR('',#1416,1.);
#1418=CARTESIAN_POINT('',(1.49999999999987,1000.,40.));
#1419=LINE('',#1418,#1417);
#1420=EDGE_CURVE('E738',#1395,#1229,#1419,.F.);
#1421=ORIENTED_EDGE('',*,*,#1420,.T.);
#1422=ORIENTED_EDGE('',*,*,#1368,.F.);
#1423=EDGE_LOOP('',(#1414,#1415,#1421,#1422));
#1424=FACE_BOUND('',#1423,.T.);
#1425=ADVANCED_FACE('F768',(#1424),#1413,.T.);
#1426=CARTESIAN_POINT('',(1.49999999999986,0.,38.5));
#1427=DIRECTION('',(0.,-1.,0.));
#1428=DIRECTION('',(0.,0.,1.));
#1429=AXIS2_PLACEMENT_3D('',#1426,#1427,#1428);
#1430=CYLINDRICAL_SURFACE('',#1429,0.750000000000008);
#1431=ORIENTED_EDGE('',*,*,#568,.T.);
#1432=ORIENTED_EDGE('',*,*,#1300,.T.);
#1433=DIRECTION('',(0.,-1.,0.));
#1434=VECTOR('',#1433,1.);
#1435=CARTESIAN_POINT('',(1.49999999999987,1000.,39.25));
#1436=LINE('',#1435,#1434);
#1437=EDGE_CURVE('E721',#1231,#1387,#1436,.T.);
#1438=ORIENTED_EDGE('',*,*,#1437,.T.);
#1439=ORIENTED_EDGE('',*,*,#1388,.T.);
#1440=EDGE_LOOP('',(#1431,#1432,#1438,#1439));
#1441=FACE_BOUND('',#1440,.T.);
#1442=ADVANCED_FACE('F758',(#1441),#1430,.F.);
#1443=CARTESIAN_POINT('',(16.4999999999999,1000.,40.0000000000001));
#1444=DIRECTION('',(0.,0.,-1.));
#1445=DIRECTION('',(-1.,0.,0.));
#1446=AXIS2_PLACEMENT_3D('',#1443,#1444,#1445);
#1447=PLANE('',#1446);
#1448=DIRECTION('',(0.707106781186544,-0.707106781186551,0.));
#1449=VECTOR('',#1448,1.);
#1450=CARTESIAN_POINT('',(1.49999999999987,999.929289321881,40.));
#1451=LINE('',#1450,#1449);
#1452=CARTESIAN_POINT('',(16.4999999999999,984.929289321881,40.0000000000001));
#1453=VERTEX_POINT('',#1452);
#1454=EDGE_CURVE('E708',#1229,#1453,#1451,.T.);
#1455=ORIENTED_EDGE('',*,*,#1454,.F.);
#1456=ORIENTED_EDGE('',*,*,#1420,.F.);
#1457=DIRECTION('',(1.,0.,0.));
#1458=VECTOR('',#1457,1.);
#1459=CARTESIAN_POINT('',(16.4999999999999,0.,40.0000000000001));
#1460=LINE('',#1459,#1458);
#1461=CARTESIAN_POINT('',(16.4999999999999,0.,40.0000000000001));
#1462=VERTEX_POINT('',#1461);
#1463=EDGE_CURVE('E728',#1462,#1395,#1460,.F.);
#1464=ORIENTED_EDGE('',*,*,#1463,.F.);
#1465=DIRECTION('',(0.,1.,0.));
#1466=VECTOR('',#1465,1.);
#1467=CARTESIAN_POINT('',(16.4999999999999,1000.,40.0000000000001));
#1468=LINE('',#1467,#1466);
#1469=EDGE_CURVE('E731',#1453,#1462,#1468,.F.);
#1470=ORIENTED_EDGE('',*,*,#1469,.F.);
#1471=EDGE_LOOP('',(#1455,#1456,#1464,#1470));
#1472=FACE_BOUND('',#1471,.T.);
#1473=ADVANCED_FACE('F767',(#1472),#1447,.F.);
#1474=CARTESIAN_POINT('',(16.4999999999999,1000.,39.2500000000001));
#1475=DIRECTION('',(0.,0.,-1.));
#1476=DIRECTION('',(-1.,0.,0.));
#1477=AXIS2_PLACEMENT_3D('',#1474,#1475,#1476);
#1478=PLANE('',#1477);
#1479=ORIENTED_EDGE('',*,*,#1437,.F.);
#1480=DIRECTION('',(0.707106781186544,-0.707106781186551,0.));
#1481=VECTOR('',#1480,1.);
#1482=CARTESIAN_POINT('',(8.9646446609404,992.464644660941,39.2500000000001));
#1483=LINE('',#1482,#1481);
#1484=CARTESIAN_POINT('',(16.4999999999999,984.929289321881,39.2500000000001));
#1485=VERTEX_POINT('',#1484);
#1486=EDGE_CURVE('E718',#1231,#1485,#1483,.T.);
#1487=ORIENTED_EDGE('',*,*,#1486,.T.);
#1488=DIRECTION('',(0.,-1.,0.));
#1489=VECTOR('',#1488,1.);
#1490=CARTESIAN_POINT('',(16.4999999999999,1000.,39.2500000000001));
#1491=LINE('',#1490,#1489);
#1492=CARTESIAN_POINT('',(16.4999999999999,0.,39.2500000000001));
#1493=VERTEX_POINT('',#1492);
#1494=EDGE_CURVE('E736',#1485,#1493,#1491,.T.);
#1495=ORIENTED_EDGE('',*,*,#1494,.T.);
#1496=DIRECTION('',(-1.,0.,0.));
#1497=VECTOR('',#1496,1.);
#1498=CARTESIAN_POINT('',(16.4999999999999,0.,39.2500000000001));
#1499=LINE('',#1498,#1497);
#1500=EDGE_CURVE('E733',#1493,#1387,#1499,.T.);
#1501=ORIENTED_EDGE('',*,*,#1500,.T.);
#1502=EDGE_LOOP('',(#1479,#1487,#1495,#1501));
#1503=FACE_BOUND('',#1502,.T.);
#1504=ADVANCED_FACE('F1200',(#1503),#1478,.T.);
#1505=CARTESIAN_POINT('',(16.4999999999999,1000.,40.0000000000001));
#1506=DIRECTION('',(1.,0.,0.));
#1507=DIRECTION('',(0.,0.,-1.));
#1508=AXIS2_PLACEMENT_3D('',#1505,#1506,#1507);
#1509=PLANE('',#1508);
#1510=ORIENTED_EDGE('',*,*,#1494,.F.);
#1511=DIRECTION('',(0.,0.,1.));
#1512=VECTOR('',#1511,1.);
#1513=CARTESIAN_POINT('',(16.4999999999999,984.929289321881,40.0000000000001));
#1514=LINE('',#1513,#1512);
#1515=EDGE_CURVE('E715',#1485,#1453,#1514,.T.);
#1516=ORIENTED_EDGE('',*,*,#1515,.T.);
#1517=ORIENTED_EDGE('',*,*,#1469,.T.);
#1518=DIRECTION('',(0.,0.,-1.));
#1519=VECTOR('',#1518,1.);
#1520=CARTESIAN_POINT('',(16.4999999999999,0.,40.0000000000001));
#1521=LINE('',#1520,#1519);
#1522=EDGE_CURVE('E725',#1462,#1493,#1521,.T.);
#1523=ORIENTED_EDGE('',*,*,#1522,.T.);
#1524=EDGE_LOOP('',(#1510,#1516,#1517,#1523));
#1525=FACE_BOUND('',#1524,.T.);
#1526=ADVANCED_FACE('F771',(#1525),#1509,.T.);
#1527=CARTESIAN_POINT('',(16.4999999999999,0.,40.0000000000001));
#1528=DIRECTION('',(0.,-1.,0.));
#1529=DIRECTION('',(1.,0.,0.));
#1530=AXIS2_PLACEMENT_3D('',#1527,#1528,#1529);
#1531=PLANE('',#1530);
#1532=ORIENTED_EDGE('',*,*,#1463,.T.);
#1533=ORIENTED_EDGE('',*,*,#1396,.F.);
#1534=ORIENTED_EDGE('',*,*,#1500,.F.);
#1535=ORIENTED_EDGE('',*,*,#1522,.F.);
#1536=EDGE_LOOP('',(#1532,#1533,#1534,#1535));
#1537=FACE_BOUND('',#1536,.T.);
#1538=ADVANCED_FACE('F1198',(#1537),#1531,.T.);
#1539=CARTESIAN_POINT('',(1.49999999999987,999.929289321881,40.));
#1540=DIRECTION('',(0.707106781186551,0.707106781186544,0.));
#1541=DIRECTION('',(-0.707106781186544,0.707106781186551,0.));
#1542=AXIS2_PLACEMENT_3D('',#1539,#1540,#1541);
#1543=PLANE('',#1542);
#1544=ORIENTED_EDGE('',*,*,#1486,.F.);
#1545=ORIENTED_EDGE('',*,*,#1232,.F.);
#1546=ORIENTED_EDGE('',*,*,#1454,.T.);
#1547=ORIENTED_EDGE('',*,*,#1515,.F.);
#1548=EDGE_LOOP('',(#1544,#1545,#1546,#1547));
#1549=FACE_BOUND('',#1548,.T.);
#1550=ADVANCED_FACE('F1185',(#1549),#1543,.T.);
#1551=CARTESIAN_POINT('',(498.5,1001.5075,38.5));
#1552=CARTESIAN_POINT('',(498.494106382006,1001.5075,38.6973668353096));
#1553=CARTESIAN_POINT('',(498.48821488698,1001.46826381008,38.8945849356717));
#1554=CARTESIAN_POINT('',(498.47642977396,1001.31723298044,39.2592056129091));
#1555=CARTESIAN_POINT('',(498.470537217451,1001.20549776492,39.4264291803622));
#1556=CARTESIAN_POINT('',(498.458752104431,1000.92642918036,39.7054977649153));
#1557=CARTESIAN_POINT('',(498.452859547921,1000.75920561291,39.8172329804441));
#1558=CARTESIAN_POINT('',(498.441074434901,1000.39458493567,39.9682638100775));
#1559=CARTESIAN_POINT('',(498.435182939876,1000.19736683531,40.0075));
#1560=CARTESIAN_POINT('',(498.429289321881,1000.,40.0075));
#1561=CARTESIAN_POINT('',(498.5,1001.5,38.5));
#1562=CARTESIAN_POINT('',(498.494106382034,1001.5,38.6963849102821));
#1563=CARTESIAN_POINT('',(498.48821488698,1001.460959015,38.892621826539));
#1564=CARTESIAN_POINT('',(498.47642977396,1001.31067958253,39.2554284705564));
#1565=CARTESIAN_POINT('',(498.470537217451,1001.1995002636,39.4218200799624));
#1566=CARTESIAN_POINT('',(498.458752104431,1000.92182007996,39.6995002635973));
#1567=CARTESIAN_POINT('',(498.452859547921,1000.75542847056,39.8106795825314));
#1568=CARTESIAN_POINT('',(498.441074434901,1000.39262182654,39.9609590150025));
#1569=CARTESIAN_POINT('',(498.435182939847,1000.19638491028,40.));
#1570=CARTESIAN_POINT('',(498.429289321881,1000.,40.));
#1571=CARTESIAN_POINT('',(498.5,1000.75,38.5));
#1572=CARTESIAN_POINT('',(498.494106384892,1000.75,38.5981924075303));
#1573=CARTESIAN_POINT('',(498.48821488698,1000.7304795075,38.6963109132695));
#1574=CARTESIAN_POINT('',(498.47642977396,1000.65533979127,38.8777142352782));
#1575=CARTESIAN_POINT('',(498.470537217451,1000.5997501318,38.9609100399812));
#1576=CARTESIAN_POINT('',(498.458752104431,1000.46091003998,39.0997501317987));
#1577=CARTESIAN_POINT('',(498.452859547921,1000.37771423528,39.1553397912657));
#1578=CARTESIAN_POINT('',(498.441074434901,1000.19631091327,39.2304795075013));
#1579=CARTESIAN_POINT('',(498.435182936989,1000.09819240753,39.25));
#1580=CARTESIAN_POINT('',(498.429289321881,1000.,39.25));
#1581=CARTESIAN_POINT('',(498.5,1000.742425,38.5));
#1582=CARTESIAN_POINT('',(498.494106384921,1000.742425,38.5972006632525));
#1583=CARTESIAN_POINT('',(498.48821488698,1000.72310166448,38.6943281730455));
#1584=CARTESIAN_POINT('',(498.47642977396,1000.64872085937,38.8738993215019));
#1585=CARTESIAN_POINT('',(498.470537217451,1000.59369265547,38.9562548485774));
#1586=CARTESIAN_POINT('',(498.458752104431,1000.45625484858,39.0936926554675));
#1587=CARTESIAN_POINT('',(498.452859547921,1000.3738993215,39.1487208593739));
#1588=CARTESIAN_POINT('',(498.441074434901,1000.19432817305,39.2231016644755));
#1589=CARTESIAN_POINT('',(498.43518293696,1000.09720066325,39.242425));
#1590=CARTESIAN_POINT('',(498.429289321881,1000.,39.242425));
#1591=B_SPLINE_SURFACE_WITH_KNOTS('',1,3,((#1551,#1552,#1553,#1554,#1555,#1556,#1557,#1558,
#1559,#1560),(#1561,#1562,#1563,#1564,#1565,#1566,#1567,#1568,#1569,#1570),(#1571,#1572,#1573,
#1574,#1575,#1576,#1577,#1578,#1579,#1580),(#1581,#1582,#1583,#1584,#1585,#1586,#1587,#1588,
#1589,#1590)),.UNSPECIFIED.,.F.,.F.,.F.,(2,1,1,2),(4,2,2,2,4),(-0.01,0.,1.,1.0101),(0.,0.25,0.5,
0.75,1.),.UNSPECIFIED.);
#1592=DIRECTION('',(0.,0.,-1.));
#1593=VECTOR('',#1592,1.);
#1594=CARTESIAN_POINT('',(498.429289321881,1000.,39.25));
#1595=LINE('',#1594,#1593);
#1596=CARTESIAN_POINT('',(498.429289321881,1000.,40.));
#1597=VERTEX_POINT('',#1596);
#1598=CARTESIAN_POINT('',(498.429289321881,1000.,39.25));
#1599=VERTEX_POINT('',#1598);
#1600=EDGE_CURVE('E1142',#1597,#1599,#1595,.T.);
#1601=CARTESIAN_POINT('',(498.5,1000.75,38.5));
#1602=CARTESIAN_POINT('',(498.499263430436,1000.75000026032,38.5122718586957));
#1603=CARTESIAN_POINT('',(498.498526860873,1000.74969881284,38.524543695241));
#1604=CARTESIAN_POINT('',(498.497053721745,1000.74849437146,38.5490578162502));
#1605=CARTESIAN_POINT('',(498.496317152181,1000.74759137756,38.5613001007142));
#1606=CARTESIAN_POINT('',(498.494844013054,1000.74518571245,38.5857256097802));
#1607=CARTESIAN_POINT('',(498.49410744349,1000.74368304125,38.5979088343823));
#1608=CARTESIAN_POINT('',(498.492634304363,1000.74008172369,38.6221868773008));
#1609=CARTESIAN_POINT('',(498.491897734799,1000.73798307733,38.6342816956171));
#1610=CARTESIAN_POINT('',(498.490424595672,1000.73319484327,38.6583537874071));
#1611=CARTESIAN_POINT('',(498.489688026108,1000.73050525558,38.6703310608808));
#1612=CARTESIAN_POINT('',(498.48821488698,1000.72454162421,38.6941392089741));
#1613=CARTESIAN_POINT('',(498.487478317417,1000.72126758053,38.7059700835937));
#1614=CARTESIAN_POINT('',(498.486005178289,1000.71414292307,38.729456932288));
#1615=CARTESIAN_POINT('',(498.485268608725,1000.71029230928,38.7411129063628));
#1616=CARTESIAN_POINT('',(498.483795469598,1000.70202378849,38.7642218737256));
#1617=CARTESIAN_POINT('',(498.483058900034,1000.69760588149,38.7756748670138));
#1618=CARTESIAN_POINT('',(498.481585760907,1000.68821341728,38.7983502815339));
#1619=CARTESIAN_POINT('',(498.480849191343,1000.68323886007,38.8095727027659));
#1620=CARTESIAN_POINT('',(498.479376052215,1000.67274507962,38.8317599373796));
#1621=CARTESIAN_POINT('',(498.478639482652,1000.66722585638,38.8427247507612));
#1622=CARTESIAN_POINT('',(498.477166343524,1000.65565604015,38.8643703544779));
#1623=CARTESIAN_POINT('',(498.47642977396,1000.64960544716,38.8750511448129));
#1624=CARTESIAN_POINT('',(498.474956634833,1000.63698746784,38.896102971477));
#1625=CARTESIAN_POINT('',(498.474220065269,1000.63042008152,38.9064740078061));
#1626=CARTESIAN_POINT('',(498.472746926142,1000.61678433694,38.9268813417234));
#1627=CARTESIAN_POINT('',(498.472010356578,1000.60971597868,38.9369176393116));
#1628=CARTESIAN_POINT('',(498.470537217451,1000.59509531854,38.9566313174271));
#1629=CARTESIAN_POINT('',(498.469800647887,1000.58754301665,38.9663086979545));
#1630=CARTESIAN_POINT('',(498.468327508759,1000.57197266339,38.985281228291));
#1631=CARTESIAN_POINT('',(498.467590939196,1000.56395461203,38.9945763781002));
#1632=CARTESIAN_POINT('',(498.466117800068,1000.54747207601,39.0127620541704));
#1633=CARTESIAN_POINT('',(498.465381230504,1000.53900759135,39.0216525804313));
#1634=CARTESIAN_POINT('',(498.463908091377,1000.52165258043,39.0390075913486));
#1635=CARTESIAN_POINT('',(498.463171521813,1000.51276205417,39.0474720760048));
#1636=CARTESIAN_POINT('',(498.461698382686,1000.4945763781,39.0639546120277));
#1637=CARTESIAN_POINT('',(498.460961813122,1000.48528122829,39.0719726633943));
#1638=CARTESIAN_POINT('',(498.459488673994,1000.46630869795,39.0875430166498));
#1639=CARTESIAN_POINT('',(498.458752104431,1000.45663131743,39.0950953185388));
#1640=CARTESIAN_POINT('',(498.457278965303,1000.43691763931,39.1097159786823));
#1641=CARTESIAN_POINT('',(498.45654239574,1000.42688134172,39.1167843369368));
#1642=CARTESIAN_POINT('',(498.455069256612,1000.40647400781,39.1304200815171));
#1643=CARTESIAN_POINT('',(498.454332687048,1000.39610297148,39.1369874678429));
#1644=CARTESIAN_POINT('',(498.452859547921,1000.37505114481,39.1496054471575));
#1645=CARTESIAN_POINT('',(498.452122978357,1000.36437035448,39.1556560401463));
#1646=CARTESIAN_POINT('',(498.45064983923,1000.34272475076,39.1672258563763));
#1647=CARTESIAN_POINT('',(498.449913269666,1000.33175993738,39.1727450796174));
#1648=CARTESIAN_POINT('',(498.448440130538,1000.30957270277,39.1832388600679));
#1649=CARTESIAN_POINT('',(498.447703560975,1000.29835028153,39.1882134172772));
#1650=CARTESIAN_POINT('',(498.446230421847,1000.27567486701,39.1976058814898));
#1651=CARTESIAN_POINT('',(498.445493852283,1000.26422187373,39.202023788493));
#1652=CARTESIAN_POINT('',(498.444020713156,1000.24111290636,39.2102923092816));
#1653=CARTESIAN_POINT('',(498.443284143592,1000.22945693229,39.2141429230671));
#1654=CARTESIAN_POINT('',(498.441811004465,1000.20597008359,39.2212675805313));
#1655=CARTESIAN_POINT('',(498.441074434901,1000.19413920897,39.2245416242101));
#1656=CARTESIAN_POINT('',(498.439601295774,1000.17033106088,39.2305052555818));
#1657=CARTESIAN_POINT('',(498.43886472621,1000.15835378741,39.2331948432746));
#1658=CARTESIAN_POINT('',(498.437391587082,1000.13428169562,39.2379830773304));
#1659=CARTESIAN_POINT('',(498.436655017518,1000.1221868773,39.2400817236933));
#1660=CARTESIAN_POINT('',(498.435181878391,1000.09790883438,39.243683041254));
#1661=CARTESIAN_POINT('',(498.434445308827,1000.08572560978,39.2451857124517));
#1662=CARTESIAN_POINT('',(498.4329721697,1000.06130010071,39.2475913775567));
#1663=CARTESIAN_POINT('',(498.432235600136,1000.04905781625,39.2484943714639));
#1664=CARTESIAN_POINT('',(498.430762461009,1000.02454369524,39.2496988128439));
#1665=CARTESIAN_POINT('',(498.430025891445,1000.0122718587,39.2500002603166));
#1666=CARTESIAN_POINT('',(498.429289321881,1000.,39.25));
#1667=B_SPLINE_CURVE_WITH_KNOTS('',3,(#1601,#1602,#1603,#1604,#1605,#1606,#1607,#1608,#1609,
#1610,#1611,#1612,#1613,#1614,#1615,#1616,#1617,#1618,#1619,#1620,#1621,#1622,#1623,#1624,#1625,
#1626,#1627,#1628,#1629,#1630,#1631,#1632,#1633,#1634,#1635,#1636,#1637,#1638,#1639,#1640,#1641,
#1642,#1643,#1644,#1645,#1646,#1647,#1648,#1649,#1650,#1651,#1652,#1653,#1654,#1655,#1656,#1657,
#1658,#1659,#1660,#1661,#1662,#1663,#1664,#1665,#1666),.UNSPECIFIED.,.F.,.F.,(4,2,2,2,2,2,2,2,2,
2,2,2,2,2,2,2,2,2,2,2,2,2,2,2,2,2,2,2,2,2,2,2,4),(0.,0.0368781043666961,0.0737562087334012,
0.110634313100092,0.14751241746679,0.184390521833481,0.221268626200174,0.258146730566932,
0.295024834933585,0.331902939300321,0.368781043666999,0.405659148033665,0.442537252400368,
0.479415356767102,0.51629346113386,0.55317156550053,0.59004966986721,0.626927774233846,
0.663805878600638,0.70068398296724,0.737562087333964,0.774440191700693,0.811318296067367,
0.848196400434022,0.885074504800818,0.921952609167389,0.958830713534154,0.995708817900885,
1.03258692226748,1.06946502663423,1.10634313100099,1.14322123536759,1.18009933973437),.UNSPECIFIED.);
#1668=EDGE_CURVE('E687',#920,#1599,#1667,.T.);
#1669=CARTESIAN_POINT('',(498.5,1001.5,38.5));
#1670=CARTESIAN_POINT('',(498.499263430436,1001.50000052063,38.5245437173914));
#1671=CARTESIAN_POINT('',(498.498526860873,1001.49939762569,38.5490873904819));
#1672=CARTESIAN_POINT('',(498.497053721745,1001.49698874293,38.5981156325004));
#1673=CARTESIAN_POINT('',(498.496317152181,1001.49518275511,38.6226002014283));
#1674=CARTESIAN_POINT('',(498.494844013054,1001.4903714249,38.6714512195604));
#1675=CARTESIAN_POINT('',(498.49410744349,1001.48736608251,38.6958176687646));
#1676=CARTESIAN_POINT('',(498.492634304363,1001.48016344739,38.7443737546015));
#1677=CARTESIAN_POINT('',(498.491897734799,1001.47596615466,38.7685633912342));
#1678=CARTESIAN_POINT('',(498.490424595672,1001.46638968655,38.8167075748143));
#1679=CARTESIAN_POINT('',(498.489688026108,1001.46101051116,38.8406621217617));
#1680=CARTESIAN_POINT('',(498.48821488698,1001.44908324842,38.8882784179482));
#1681=CARTESIAN_POINT('',(498.487478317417,1001.44253516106,38.9119401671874));
#1682=CARTESIAN_POINT('',(498.486005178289,1001.42828584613,38.9589138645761));
#1683=CARTESIAN_POINT('',(498.485268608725,1001.42058461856,38.9822258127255));
#1684=CARTESIAN_POINT('',(498.483795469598,1001.40404757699,39.0284437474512));
#1685=CARTESIAN_POINT('',(498.483058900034,1001.39521176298,39.0513497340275));
#1686=CARTESIAN_POINT('',(498.481585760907,1001.37642683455,39.0967005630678));
#1687=CARTESIAN_POINT('',(498.480849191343,1001.36647772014,39.1191454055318));
#1688=CARTESIAN_POINT('',(498.479376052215,1001.34549015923,39.1635198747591));
#1689=CARTESIAN_POINT('',(498.478639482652,1001.33445171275,39.1854495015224));
#1690=CARTESIAN_POINT('',(498.477166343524,1001.31131208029,39.2287407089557));
#1691=CARTESIAN_POINT('',(498.47642977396,1001.29921089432,39.2501022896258));
#1692=CARTESIAN_POINT('',(498.474956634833,1001.27397493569,39.292205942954));
#1693=CARTESIAN_POINT('',(498.474220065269,1001.26084016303,39.3129480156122));
#1694=CARTESIAN_POINT('',(498.472746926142,1001.23356867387,39.3537626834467));
#1695=CARTESIAN_POINT('',(498.472010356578,1001.21943195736,39.3738352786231));
#1696=CARTESIAN_POINT('',(498.470537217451,1001.19019063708,39.4132626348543));
#1697=CARTESIAN_POINT('',(498.469800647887,1001.1750860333,39.432617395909));
#1698=CARTESIAN_POINT('',(498.468327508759,1001.14394532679,39.4705624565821));
#1699=CARTESIAN_POINT('',(498.467590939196,1001.12790922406,39.4891527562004));
#1700=CARTESIAN_POINT('',(498.466117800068,1001.09494415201,39.5255241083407));
#1701=CARTESIAN_POINT('',(498.465381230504,1001.0780151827,39.5433051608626));
#1702=CARTESIAN_POINT('',(498.463908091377,1001.04330516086,39.5780151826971));
#1703=CARTESIAN_POINT('',(498.463171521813,1001.02552410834,39.5949441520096));
#1704=CARTESIAN_POINT('',(498.461698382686,1000.9891527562,39.6279092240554));
#1705=CARTESIAN_POINT('',(498.460961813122,1000.97056245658,39.6439453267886));
#1706=CARTESIAN_POINT('',(498.459488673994,1000.93261739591,39.6750860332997));
#1707=CARTESIAN_POINT('',(498.458752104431,1000.91326263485,39.6901906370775));
#1708=CARTESIAN_POINT('',(498.457278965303,1000.87383527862,39.7194319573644));
#1709=CARTESIAN_POINT('',(498.45654239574,1000.85376268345,39.7335686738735));
#1710=CARTESIAN_POINT('',(498.455069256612,1000.81294801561,39.7608401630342));
#1711=CARTESIAN_POINT('',(498.454332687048,1000.79220594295,39.7739749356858));
#1712=CARTESIAN_POINT('',(498.452859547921,1000.75010228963,39.7992108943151));
#1713=CARTESIAN_POINT('',(498.452122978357,1000.72874070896,39.8113120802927));
#1714=CARTESIAN_POINT('',(498.45064983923,1000.68544950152,39.8344517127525));
#1715=CARTESIAN_POINT('',(498.449913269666,1000.66351987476,39.8454901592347));
#1716=CARTESIAN_POINT('',(498.448440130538,1000.61914540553,39.8664777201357));
#1717=CARTESIAN_POINT('',(498.447703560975,1000.59670056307,39.8764268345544));
#1718=CARTESIAN_POINT('',(498.446230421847,1000.55134973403,39.8952117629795));
#1719=CARTESIAN_POINT('',(498.445493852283,1000.52844374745,39.9040475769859));
#1720=CARTESIAN_POINT('',(498.444020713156,1000.48222581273,39.9205846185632));
#1721=CARTESIAN_POINT('',(498.443284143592,1000.45891386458,39.9282858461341));
#1722=CARTESIAN_POINT('',(498.441811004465,1000.41194016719,39.9425351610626));
#1723=CARTESIAN_POINT('',(498.441074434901,1000.38827841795,39.9490832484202));
#1724=CARTESIAN_POINT('',(498.439601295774,1000.34066212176,39.9610105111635));
#1725=CARTESIAN_POINT('',(498.43886472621,1000.31670757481,39.9663896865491));
#1726=CARTESIAN_POINT('',(498.437391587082,1000.26856339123,39.9759661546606));
#1727=CARTESIAN_POINT('',(498.436655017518,1000.2443737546,39.9801634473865));
#1728=CARTESIAN_POINT('',(498.435181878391,1000.19581766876,39.9873660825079));
#1729=CARTESIAN_POINT('',(498.434445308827,1000.17145121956,39.9903714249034));
#1730=CARTESIAN_POINT('',(498.4329721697,1000.12260020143,39.9951827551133));
#1731=CARTESIAN_POINT('',(498.432235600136,1000.0981156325,39.9969887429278));
#1732=CARTESIAN_POINT('',(498.430762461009,1000.04908739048,39.9993976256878));
#1733=CARTESIAN_POINT('',(498.430025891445,1000.02454371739,40.0000005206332));
#1734=CARTESIAN_POINT('',(498.429289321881,1000.,40.));
#1735=B_SPLINE_CURVE_WITH_KNOTS('',3,(#1669,#1670,#1671,#1672,#1673,#1674,#1675,#1676,#1677,
#1678,#1679,#1680,#1681,#1682,#1683,#1684,#1685,#1686,#1687,#1688,#1689,#1690,#1691,#1692,#1693,
#1694,#1695,#1696,#1697,#1698,#1699,#1700,#1701,#1702,#1703,#1704,#1705,#1706,#1707,#1708,#1709,
#1710,#1711,#1712,#1713,#1714,#1715,#1716,#1717,#1718,#1719,#1720,#1721,#1722,#1723,#1724,#1725,
#1726,#1727,#1728,#1729,#1730,#1731,#1732,#1733,#1734),.UNSPECIFIED.,.F.,.F.,(4,2,2,2,2,2,2,2,2,
2,2,2,2,2,2,2,2,2,2,2,2,2,2,2,2,2,2,2,2,2,2,2,4),(0.,0.0736568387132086,0.147313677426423,
0.220970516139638,0.294627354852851,0.368284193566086,0.441941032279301,0.515597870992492,
0.589254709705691,0.662911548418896,0.736568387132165,0.810225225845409,0.883882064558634,
0.957538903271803,1.03119574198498,1.10485258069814,1.17850941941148,1.25216625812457,
1.32582309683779,1.39947993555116,1.47313677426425,1.54679361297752,1.62045045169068,
1.69410729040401,1.76776412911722,1.84142096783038,1.91507780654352,1.9887346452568,
2.06239148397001,2.13604832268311,2.20970516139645,2.2833620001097,2.35701883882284),.UNSPECIFIED.);
#1736=EDGE_CURVE('E697',#929,#1597,#1735,.T.);
#1737=ORIENTED_EDGE('',*,*,#1600,.T.);
#1738=ORIENTED_EDGE('',*,*,#1668,.F.);
#1739=ORIENTED_EDGE('',*,*,#936,.F.);
#1740=ORIENTED_EDGE('',*,*,#1736,.T.);
#1741=EDGE_LOOP('',(#1737,#1738,#1739,#1740));
#1742=FACE_BOUND('',#1741,.T.);
#1743=ADVANCED_FACE('F1140',(#1742),#1591,.F.);
#1744=CARTESIAN_POINT('',(1.57071067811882,1000.,40.0075));
#1745=CARTESIAN_POINT('',(1.56481706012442,1000.19736683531,40.0075));
#1746=CARTESIAN_POINT('',(1.55892556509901,1000.39458493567,39.9682638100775));
#1747=CARTESIAN_POINT('',(1.5471404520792,1000.75920561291,39.8172329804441));
#1748=CARTESIAN_POINT('',(1.5412478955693,1000.92642918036,39.7054977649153));
#1749=CARTESIAN_POINT('',(1.52946278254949,1001.20549776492,39.4264291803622));
#1750=CARTESIAN_POINT('',(1.52357022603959,1001.31723298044,39.2592056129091));
#1751=CARTESIAN_POINT('',(1.51178511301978,1001.46826381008,38.8945849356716));
#1752=CARTESIAN_POINT('',(1.50589361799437,1001.5075,38.6973668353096));
#1753=CARTESIAN_POINT('',(1.49999999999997,1001.5075,38.5));
#1754=CARTESIAN_POINT('',(1.57071067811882,1000.,40.));
#1755=CARTESIAN_POINT('',(1.56481706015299,1000.19638491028,40.));
#1756=CARTESIAN_POINT('',(1.55892556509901,1000.39262182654,39.9609590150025));
#1757=CARTESIAN_POINT('',(1.5471404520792,1000.75542847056,39.8106795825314));
#1758=CARTESIAN_POINT('',(1.5412478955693,1000.92182007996,39.6995002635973));
#1759=CARTESIAN_POINT('',(1.52946278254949,1001.1995002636,39.4218200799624));
#1760=CARTESIAN_POINT('',(1.52357022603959,1001.31067958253,39.2554284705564));
#1761=CARTESIAN_POINT('',(1.51178511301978,1001.460959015,38.8926218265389));
#1762=CARTESIAN_POINT('',(1.50589361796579,1001.5,38.696384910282));
#1763=CARTESIAN_POINT('',(1.49999999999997,1001.5,38.5));
#1764=CARTESIAN_POINT('',(1.57071067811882,1000.,39.25));
#1765=CARTESIAN_POINT('',(1.56481706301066,1000.09819240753,39.25));
#1766=CARTESIAN_POINT('',(1.55892556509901,1000.19631091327,39.2304795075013));
#1767=CARTESIAN_POINT('',(1.5471404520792,1000.37771423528,39.1553397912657));
#1768=CARTESIAN_POINT('',(1.5412478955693,1000.46091003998,39.0997501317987));
#1769=CARTESIAN_POINT('',(1.52946278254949,1000.5997501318,38.9609100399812));
#1770=CARTESIAN_POINT('',(1.52357022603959,1000.65533979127,38.8777142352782));
#1771=CARTESIAN_POINT('',(1.51178511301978,1000.7304795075,38.6963109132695));
#1772=CARTESIAN_POINT('',(1.50589361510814,1000.75,38.5981924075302));
#1773=CARTESIAN_POINT('',(1.49999999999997,1000.75,38.5));
#1774=CARTESIAN_POINT('',(1.57071067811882,1000.,39.242425));
#1775=CARTESIAN_POINT('',(1.56481706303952,1000.09720066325,39.242425));
#1776=CARTESIAN_POINT('',(1.55892556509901,1000.19432817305,39.2231016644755));
#1777=CARTESIAN_POINT('',(1.5471404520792,1000.3738993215,39.1487208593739));
#1778=CARTESIAN_POINT('',(1.5412478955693,1000.45625484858,39.0936926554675));
#1779=CARTESIAN_POINT('',(1.52946278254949,1000.59369265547,38.9562548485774));
#1780=CARTESIAN_POINT('',(1.52357022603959,1000.64872085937,38.8738993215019));
#1781=CARTESIAN_POINT('',(1.51178511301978,1000.72310166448,38.6943281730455));
#1782=CARTESIAN_POINT('',(1.50589361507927,1000.742425,38.5972006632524));
#1783=CARTESIAN_POINT('',(1.49999999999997,1000.742425,38.5));
#1784=B_SPLINE_SURFACE_WITH_KNOTS('',1,3,((#1744,#1745,#1746,#1747,#1748,#1749,#1750,#1751,
#1752,#1753),(#1754,#1755,#1756,#1757,#1758,#1759,#1760,#1761,#1762,#1763),(#1764,#1765,#1766,
#1767,#1768,#1769,#1770,#1771,#1772,#1773),(#1774,#1775,#1776,#1777,#1778,#1779,#1780,#1781,
#1782,#1783)),.UNSPECIFIED.,.F.,.F.,.F.,(2,1,1,2),(4,2,2,2,4),(-0.01,0.,1.,1.0101),(0.,0.25,0.5,
0.75,1.),.UNSPECIFIED.);
#1785=CARTESIAN_POINT('',(1.57071067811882,1000.,39.25));
#1786=CARTESIAN_POINT('',(1.56997410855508,1000.0122718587,39.2500002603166));
#1787=CARTESIAN_POINT('',(1.56923753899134,1000.02454369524,39.2496988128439));
#1788=CARTESIAN_POINT('',(1.56776439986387,1000.04905781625,39.2484943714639));
#1789=CARTESIAN_POINT('',(1.56702783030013,1000.06130010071,39.2475913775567));
#1790=CARTESIAN_POINT('',(1.56555469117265,1000.08572560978,39.2451857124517));
#1791=CARTESIAN_POINT('',(1.56481812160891,1000.09790883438,39.243683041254));
#1792=CARTESIAN_POINT('',(1.56334498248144,1000.1221868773,39.2400817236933));
#1793=CARTESIAN_POINT('',(1.5626084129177,1000.13428169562,39.2379830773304));
#1794=CARTESIAN_POINT('',(1.56113527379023,1000.15835378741,39.2331948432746));
#1795=CARTESIAN_POINT('',(1.56039870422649,1000.17033106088,39.2305052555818));
#1796=CARTESIAN_POINT('',(1.55892556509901,1000.19413920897,39.2245416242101));
#1797=CARTESIAN_POINT('',(1.55818899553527,1000.20597008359,39.2212675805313));
#1798=CARTESIAN_POINT('',(1.5567158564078,1000.22945693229,39.2141429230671));
#1799=CARTESIAN_POINT('',(1.55597928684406,1000.24111290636,39.2102923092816));
#1800=CARTESIAN_POINT('',(1.55450614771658,1000.26422187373,39.202023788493));
#1801=CARTESIAN_POINT('',(1.55376957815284,1000.27567486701,39.1976058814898));
#1802=CARTESIAN_POINT('',(1.55229643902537,1000.29835028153,39.1882134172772));
#1803=CARTESIAN_POINT('',(1.55155986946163,1000.30957270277,39.1832388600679));
#1804=CARTESIAN_POINT('',(1.55008673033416,1000.33175993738,39.1727450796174));
#1805=CARTESIAN_POINT('',(1.54935016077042,1000.34272475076,39.1672258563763));
#1806=CARTESIAN_POINT('',(1.54787702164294,1000.36437035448,39.1556560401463));
#1807=CARTESIAN_POINT('',(1.5471404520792,1000.37505114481,39.1496054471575));
#1808=CARTESIAN_POINT('',(1.54566731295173,1000.39610297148,39.1369874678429));
#1809=CARTESIAN_POINT('',(1.54493074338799,1000.40647400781,39.1304200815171));
#1810=CARTESIAN_POINT('',(1.54345760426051,1000.42688134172,39.1167843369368));
#1811=CARTESIAN_POINT('',(1.54272103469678,1000.43691763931,39.1097159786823));
#1812=CARTESIAN_POINT('',(1.5412478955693,1000.45663131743,39.0950953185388));
#1813=CARTESIAN_POINT('',(1.54051132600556,1000.46630869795,39.0875430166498));
#1814=CARTESIAN_POINT('',(1.53903818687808,1000.48528122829,39.0719726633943));
#1815=CARTESIAN_POINT('',(1.53830161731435,1000.4945763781,39.0639546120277));
#1816=CARTESIAN_POINT('',(1.53682847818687,1000.51276205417,39.0474720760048));
#1817=CARTESIAN_POINT('',(1.53609190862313,1000.52165258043,39.0390075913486));
#1818=CARTESIAN_POINT('',(1.53461876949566,1000.53900759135,39.0216525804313));
#1819=CARTESIAN_POINT('',(1.53388219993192,1000.54747207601,39.0127620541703));
#1820=CARTESIAN_POINT('',(1.53240906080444,1000.56395461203,38.9945763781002));
#1821=CARTESIAN_POINT('',(1.53167249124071,1000.57197266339,38.9852812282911));
#1822=CARTESIAN_POINT('',(1.53019935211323,1000.58754301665,38.9663086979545));
#1823=CARTESIAN_POINT('',(1.52946278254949,1000.59509531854,38.9566313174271));
#1824=CARTESIAN_POINT('',(1.52798964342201,1000.60971597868,38.9369176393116));
#1825=CARTESIAN_POINT('',(1.52725307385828,1000.61678433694,38.9268813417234));
#1826=CARTESIAN_POINT('',(1.5257799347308,1000.63042008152,38.9064740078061));
#1827=CARTESIAN_POINT('',(1.52504336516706,1000.63698746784,38.896102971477));
#1828=CARTESIAN_POINT('',(1.52357022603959,1000.64960544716,38.8750511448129));
#1829=CARTESIAN_POINT('',(1.52283365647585,1000.65565604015,38.8643703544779));
#1830=CARTESIAN_POINT('',(1.52136051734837,1000.66722585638,38.8427247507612));
#1831=CARTESIAN_POINT('',(1.52062394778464,1000.67274507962,38.8317599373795));
#1832=CARTESIAN_POINT('',(1.51915080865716,1000.68323886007,38.8095727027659));
#1833=CARTESIAN_POINT('',(1.51841423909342,1000.68821341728,38.7983502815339));
#1834=CARTESIAN_POINT('',(1.51694109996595,1000.69760588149,38.7756748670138));
#1835=CARTESIAN_POINT('',(1.51620453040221,1000.70202378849,38.7642218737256));
#1836=CARTESIAN_POINT('',(1.51473139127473,1000.71029230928,38.7411129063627));
#1837=CARTESIAN_POINT('',(1.51399482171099,1000.71414292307,38.729456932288));
#1838=CARTESIAN_POINT('',(1.51252168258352,1000.72126758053,38.7059700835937));
#1839=CARTESIAN_POINT('',(1.51178511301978,1000.72454162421,38.6941392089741));
#1840=CARTESIAN_POINT('',(1.5103119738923,1000.73050525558,38.6703310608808));
#1841=CARTESIAN_POINT('',(1.50957540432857,1000.73319484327,38.6583537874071));
#1842=CARTESIAN_POINT('',(1.50810226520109,1000.73798307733,38.6342816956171));
#1843=CARTESIAN_POINT('',(1.50736569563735,1000.74008172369,38.6221868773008));
#1844=CARTESIAN_POINT('',(1.50589255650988,1000.74368304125,38.5979088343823));
#1845=CARTESIAN_POINT('',(1.50515598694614,1000.74518571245,38.5857256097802));
#1846=CARTESIAN_POINT('',(1.50368284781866,1000.74759137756,38.5613001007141));
#1847=CARTESIAN_POINT('',(1.50294627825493,1000.74849437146,38.5490578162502));
#1848=CARTESIAN_POINT('',(1.50147313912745,1000.74969881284,38.524543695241));
#1849=CARTESIAN_POINT('',(1.50073656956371,1000.75000026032,38.5122718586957));
#1850=CARTESIAN_POINT('',(1.49999999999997,1000.75,38.5));
#1851=B_SPLINE_CURVE_WITH_KNOTS('',3,(#1785,#1786,#1787,#1788,#1789,#1790,#1791,#1792,#1793,
#1794,#1795,#1796,#1797,#1798,#1799,#1800,#1801,#1802,#1803,#1804,#1805,#1806,#1807,#1808,#1809,
#1810,#1811,#1812,#1813,#1814,#1815,#1816,#1817,#1818,#1819,#1820,#1821,#1822,#1823,#1824,#1825,
#1826,#1827,#1828,#1829,#1830,#1831,#1832,#1833,#1834,#1835,#1836,#1837,#1838,#1839,#1840,#1841,
#1842,#1843,#1844,#1845,#1846,#1847,#1848,#1849,#1850),.UNSPECIFIED.,.F.,.F.,(4,2,2,2,2,2,2,2,2,
2,2,2,2,2,2,2,2,2,2,2,2,2,2,2,2,2,2,2,2,2,2,2,4),(0.,0.0368781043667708,0.073756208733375,
0.110634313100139,0.147512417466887,0.184390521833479,0.221268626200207,0.258146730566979,
0.295024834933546,0.331902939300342,0.368781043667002,0.405659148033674,0.442537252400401,
0.479415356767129,0.51629346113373,0.55317156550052,0.590049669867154,0.626927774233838,
0.663805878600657,0.70068398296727,0.737562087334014,0.774440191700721,0.81131829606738,
0.848196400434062,0.885074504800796,0.921952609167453,0.95883071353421,0.995708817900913,
1.0325869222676,1.0694650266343,1.10634313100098,1.14322123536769,1.18009933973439),.UNSPECIFIED.);
#1852=CARTESIAN_POINT('',(1.57071067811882,1000.,39.25));
#1853=VERTEX_POINT('',#1852);
#1854=EDGE_CURVE('E692',#1853,#898,#1851,.T.);
#1855=DIRECTION('',(0.,0.,1.));
#1856=VECTOR('',#1855,1.);
#1857=CARTESIAN_POINT('',(1.57071067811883,1000.,39.25));
#1858=LINE('',#1857,#1856);
#1859=CARTESIAN_POINT('',(1.57071067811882,1000.,40.));
#1860=VERTEX_POINT('',#1859);
#1861=EDGE_CURVE('E696',#1860,#1853,#1858,.F.);
#1862=CARTESIAN_POINT('',(1.57071067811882,1000.,40.));
#1863=CARTESIAN_POINT('',(1.56997410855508,1000.02454371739,40.0000005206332));
#1864=CARTESIAN_POINT('',(1.56923753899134,1000.04908739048,39.9993976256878));
#1865=CARTESIAN_POINT('',(1.56776439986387,1000.0981156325,39.9969887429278));
#1866=CARTESIAN_POINT('',(1.56702783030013,1000.12260020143,39.9951827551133));
#1867=CARTESIAN_POINT('',(1.56555469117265,1000.17145121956,39.9903714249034));
#1868=CARTESIAN_POINT('',(1.56481812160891,1000.19581766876,39.9873660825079));
#1869=CARTESIAN_POINT('',(1.56334498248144,1000.2443737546,39.9801634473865));
#1870=CARTESIAN_POINT('',(1.5626084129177,1000.26856339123,39.9759661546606));
#1871=CARTESIAN_POINT('',(1.56113527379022,1000.31670757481,39.9663896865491));
#1872=CARTESIAN_POINT('',(1.56039870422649,1000.34066212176,39.9610105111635));
#1873=CARTESIAN_POINT('',(1.55892556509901,1000.38827841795,39.9490832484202));
#1874=CARTESIAN_POINT('',(1.55818899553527,1000.41194016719,39.9425351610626));
#1875=CARTESIAN_POINT('',(1.5567158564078,1000.45891386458,39.9282858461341));
#1876=CARTESIAN_POINT('',(1.55597928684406,1000.48222581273,39.9205846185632));
#1877=CARTESIAN_POINT('',(1.55450614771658,1000.52844374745,39.9040475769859));
#1878=CARTESIAN_POINT('',(1.55376957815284,1000.55134973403,39.8952117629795));
#1879=CARTESIAN_POINT('',(1.55229643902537,1000.59670056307,39.8764268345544));
#1880=CARTESIAN_POINT('',(1.55155986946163,1000.61914540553,39.8664777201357));
#1881=CARTESIAN_POINT('',(1.55008673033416,1000.66351987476,39.8454901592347));
#1882=CARTESIAN_POINT('',(1.54935016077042,1000.68544950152,39.8344517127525));
#1883=CARTESIAN_POINT('',(1.54787702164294,1000.72874070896,39.8113120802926));
#1884=CARTESIAN_POINT('',(1.5471404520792,1000.75010228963,39.799210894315));
#1885=CARTESIAN_POINT('',(1.54566731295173,1000.79220594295,39.7739749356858));
#1886=CARTESIAN_POINT('',(1.54493074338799,1000.81294801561,39.7608401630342));
#1887=CARTESIAN_POINT('',(1.54345760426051,1000.85376268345,39.7335686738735));
#1888=CARTESIAN_POINT('',(1.54272103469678,1000.87383527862,39.7194319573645));
#1889=CARTESIAN_POINT('',(1.5412478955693,1000.91326263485,39.6901906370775));
#1890=CARTESIAN_POINT('',(1.54051132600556,1000.93261739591,39.6750860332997));
#1891=CARTESIAN_POINT('',(1.53903818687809,1000.97056245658,39.6439453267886));
#1892=CARTESIAN_POINT('',(1.53830161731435,1000.9891527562,39.6279092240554));
#1893=CARTESIAN_POINT('',(1.53682847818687,1001.02552410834,39.5949441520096));
#1894=CARTESIAN_POINT('',(1.53609190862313,1001.04330516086,39.578015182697));
#1895=CARTESIAN_POINT('',(1.53461876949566,1001.0780151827,39.5433051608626));
#1896=CARTESIAN_POINT('',(1.53388219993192,1001.09494415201,39.5255241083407));
#1897=CARTESIAN_POINT('',(1.53240906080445,1001.12790922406,39.4891527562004));
#1898=CARTESIAN_POINT('',(1.53167249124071,1001.14394532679,39.470562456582));
#1899=CARTESIAN_POINT('',(1.53019935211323,1001.1750860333,39.4326173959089));
#1900=CARTESIAN_POINT('',(1.52946278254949,1001.19019063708,39.4132626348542));
#1901=CARTESIAN_POINT('',(1.52798964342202,1001.21943195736,39.3738352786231));
#1902=CARTESIAN_POINT('',(1.52725307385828,1001.23356867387,39.3537626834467));
#1903=CARTESIAN_POINT('',(1.5257799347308,1001.26084016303,39.3129480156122));
#1904=CARTESIAN_POINT('',(1.52504336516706,1001.27397493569,39.292205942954));
#1905=CARTESIAN_POINT('',(1.52357022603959,1001.29921089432,39.2501022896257));
#1906=CARTESIAN_POINT('',(1.52283365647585,1001.31131208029,39.2287407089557));
#1907=CARTESIAN_POINT('',(1.52136051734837,1001.33445171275,39.1854495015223));
#1908=CARTESIAN_POINT('',(1.52062394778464,1001.34549015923,39.1635198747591));
#1909=CARTESIAN_POINT('',(1.51915080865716,1001.36647772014,39.1191454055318));
#1910=CARTESIAN_POINT('',(1.51841423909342,1001.37642683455,39.0967005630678));
#1911=CARTESIAN_POINT('',(1.51694109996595,1001.39521176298,39.0513497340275));
#1912=CARTESIAN_POINT('',(1.51620453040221,1001.40404757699,39.0284437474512));
#1913=CARTESIAN_POINT('',(1.51473139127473,1001.42058461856,38.9822258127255));
#1914=CARTESIAN_POINT('',(1.51399482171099,1001.42828584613,38.958913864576));
#1915=CARTESIAN_POINT('',(1.51252168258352,1001.44253516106,38.9119401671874));
#1916=CARTESIAN_POINT('',(1.51178511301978,1001.44908324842,38.8882784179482));
#1917=CARTESIAN_POINT('',(1.5103119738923,1001.46101051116,38.8406621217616));
#1918=CARTESIAN_POINT('',(1.50957540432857,1001.46638968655,38.8167075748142));
#1919=CARTESIAN_POINT('',(1.50810226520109,1001.47596615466,38.7685633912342));
#1920=CARTESIAN_POINT('',(1.50736569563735,1001.48016344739,38.7443737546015));
#1921=CARTESIAN_POINT('',(1.50589255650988,1001.48736608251,38.6958176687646));
#1922=CARTESIAN_POINT('',(1.50515598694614,1001.4903714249,38.6714512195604));
#1923=CARTESIAN_POINT('',(1.50368284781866,1001.49518275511,38.6226002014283));
#1924=CARTESIAN_POINT('',(1.50294627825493,1001.49698874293,38.5981156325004));
#1925=CARTESIAN_POINT('',(1.50147313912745,1001.49939762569,38.5490873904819));
#1926=CARTESIAN_POINT('',(1.50073656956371,1001.50000052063,38.5245437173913));
#1927=CARTESIAN_POINT('',(1.49999999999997,1001.5,38.5));
#1928=B_SPLINE_CURVE_WITH_KNOTS('',3,(#1862,#1863,#1864,#1865,#1866,#1867,#1868,#1869,#1870,
#1871,#1872,#1873,#1874,#1875,#1876,#1877,#1878,#1879,#1880,#1881,#1882,#1883,#1884,#1885,#1886,
#1887,#1888,#1889,#1890,#1891,#1892,#1893,#1894,#1895,#1896,#1897,#1898,#1899,#1900,#1901,#1902,
#1903,#1904,#1905,#1906,#1907,#1908,#1909,#1910,#1911,#1912,#1913,#1914,#1915,#1916,#1917,#1918,
#1919,#1920,#1921,#1922,#1923,#1924,#1925,#1926,#1927),.UNSPECIFIED.,.F.,.F.,(4,2,2,2,2,2,2,2,2,
2,2,2,2,2,2,2,2,2,2,2,2,2,2,2,2,2,2,2,2,2,2,2,4),(0.,0.0736568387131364,0.147313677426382,
0.220970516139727,0.294627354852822,0.368284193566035,0.441941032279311,0.515597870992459,
0.589254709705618,0.662911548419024,0.736568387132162,0.810225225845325,0.883882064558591,
0.957538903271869,1.03119574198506,1.10485258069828,1.17850941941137,1.25216625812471,
1.32582309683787,1.39947993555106,1.47313677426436,1.54679361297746,1.62045045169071,
1.69410729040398,1.76776412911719,1.84142096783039,1.91507780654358,1.9887346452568,
2.06239148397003,2.13604832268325,2.20970516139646,2.28336200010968,2.3570188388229),.UNSPECIFIED.);
#1929=EDGE_CURVE('E699',#1860,#889,#1928,.T.);
#1930=ORIENTED_EDGE('',*,*,#1854,.F.);
#1931=ORIENTED_EDGE('',*,*,#1861,.F.);
#1932=ORIENTED_EDGE('',*,*,#1929,.T.);
#1933=ORIENTED_EDGE('',*,*,#905,.T.);
#1934=EDGE_LOOP('',(#1930,#1931,#1932,#1933));
#1935=FACE_BOUND('',#1934,.T.);
#1936=ADVANCED_FACE('F682',(#1935),#1784,.F.);
#1937=CARTESIAN_POINT('',(1.49999999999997,1000.,38.5));
#1938=DIRECTION('',(-1.,0.,0.));
#1939=DIRECTION('',(0.,0.,1.));
#1940=AXIS2_PLACEMENT_3D('',#1937,#1938,#1939);
#1941=CYLINDRICAL_SURFACE('',#1940,1.50000000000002);
#1942=ORIENTED_EDGE('',*,*,#953,.T.);
#1943=ORIENTED_EDGE('',*,*,#1929,.F.);
#1944=DIRECTION('',(-1.,0.,0.));
#1945=VECTOR('',#1944,1.);
#1946=CARTESIAN_POINT('',(498.5,1000.,40.));
#1947=LINE('',#1946,#1945);
#1948=EDGE_CURVE('E1155',#1860,#1597,#1947,.F.);
#1949=ORIENTED_EDGE('',*,*,#1948,.T.);
#1950=ORIENTED_EDGE('',*,*,#1736,.F.);
#1951=EDGE_LOOP('',(#1942,#1943,#1949,#1950));
#1952=FACE_BOUND('',#1951,.T.);
#1953=ADVANCED_FACE('F680',(#1952),#1941,.T.);
#1954=CARTESIAN_POINT('',(1.49999999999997,1000.,38.5));
#1955=DIRECTION('',(-1.,0.,0.));
#1956=DIRECTION('',(0.,0.,1.));
#1957=AXIS2_PLACEMENT_3D('',#1954,#1955,#1956);
#1958=CYLINDRICAL_SURFACE('',#1957,0.750000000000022);
#1959=ORIENTED_EDGE('',*,*,#969,.F.);
#1960=ORIENTED_EDGE('',*,*,#1668,.T.);
#1961=DIRECTION('',(-1.,0.,0.));
#1962=VECTOR('',#1961,1.);
#1963=CARTESIAN_POINT('',(498.5,1000.,39.25));
#1964=LINE('',#1963,#1962);
#1965=EDGE_CURVE('E1156',#1599,#1853,#1964,.T.);
#1966=ORIENTED_EDGE('',*,*,#1965,.T.);
#1967=ORIENTED_EDGE('',*,*,#1854,.T.);
#1968=EDGE_LOOP('',(#1959,#1960,#1966,#1967));
#1969=FACE_BOUND('',#1968,.T.);
#1970=ADVANCED_FACE('F672',(#1969),#1958,.F.);
#1971=CARTESIAN_POINT('',(498.5,985.,40.0000000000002));
#1972=DIRECTION('',(0.,0.,-1.));
#1973=DIRECTION('',(0.,1.,0.));
#1974=AXIS2_PLACEMENT_3D('',#1971,#1972,#1973);
#1975=PLANE('',#1974);
#1976=DIRECTION('',(-0.70710678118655,0.707106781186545,0.));
#1977=VECTOR('',#1976,1.);
#1978=CARTESIAN_POINT('',(353.06324948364,648.507461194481,40.0000000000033));
#1979=LINE('',#1978,#1977);
#1980=CARTESIAN_POINT('',(16.5707106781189,985.,40.0000000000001));
#1981=VERTEX_POINT('',#1980);
#1982=EDGE_CURVE('E615',#1981,#1860,#1979,.T.);
#1983=ORIENTED_EDGE('',*,*,#1982,.F.);
#1984=DIRECTION('',(1.,0.,0.));
#1985=VECTOR('',#1984,1.);
#1986=CARTESIAN_POINT('',(498.5,985.,40.0000000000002));
#1987=LINE('',#1986,#1985);
#1988=CARTESIAN_POINT('',(483.429289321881,985.,40.0000000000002));
#1989=VERTEX_POINT('',#1988);
#1990=EDGE_CURVE('E1144',#1989,#1981,#1987,.F.);
#1991=ORIENTED_EDGE('',*,*,#1990,.F.);
#1992=DIRECTION('',(-0.70710678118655,-0.707106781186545,0.));
#1993=VECTOR('',#1992,1.);
#1994=CARTESIAN_POINT('',(498.429289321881,1000.,40.));
#1995=LINE('',#1994,#1993);
#1996=EDGE_CURVE('E1163',#1597,#1989,#1995,.T.);
#1997=ORIENTED_EDGE('',*,*,#1996,.F.);
#1998=ORIENTED_EDGE('',*,*,#1948,.F.);
#1999=EDGE_LOOP('',(#1983,#1991,#1997,#1998));
#2000=FACE_BOUND('',#1999,.T.);
#2001=ADVANCED_FACE('F668',(#2000),#1975,.F.);
#2002=CARTESIAN_POINT('',(498.5,985.,39.2500000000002));
#2003=DIRECTION('',(0.,0.,-1.));
#2004=DIRECTION('',(0.,1.,0.));
#2005=AXIS2_PLACEMENT_3D('',#2002,#2003,#2004);
#2006=PLANE('',#2005);
#2007=DIRECTION('',(-1.,0.,0.));
#2008=VECTOR('',#2007,1.);
#2009=CARTESIAN_POINT('',(498.5,985.,39.2500000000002));
#2010=LINE('',#2009,#2008);
#2011=CARTESIAN_POINT('',(483.429289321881,985.,39.2500000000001));
#2012=VERTEX_POINT('',#2011);
#2013=CARTESIAN_POINT('',(16.5707106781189,985.,39.2500000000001));
#2014=VERTEX_POINT('',#2013);
#2015=EDGE_CURVE('E1149',#2012,#2014,#2010,.T.);
#2016=ORIENTED_EDGE('',*,*,#2015,.T.);
#2017=DIRECTION('',(-0.70710678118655,0.707106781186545,0.));
#2018=VECTOR('',#2017,1.);
#2019=CARTESIAN_POINT('',(257.535355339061,744.03535533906,39.2500000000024));
#2020=LINE('',#2019,#2018);
#2021=EDGE_CURVE('E1167',#2014,#1853,#2020,.T.);
#2022=ORIENTED_EDGE('',*,*,#2021,.T.);
#2023=ORIENTED_EDGE('',*,*,#1965,.F.);
#2024=DIRECTION('',(-0.70710678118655,-0.707106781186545,0.));
#2025=VECTOR('',#2024,1.);
#2026=CARTESIAN_POINT('',(490.964644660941,992.53535533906,39.2500000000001));
#2027=LINE('',#2026,#2025);
#2028=EDGE_CURVE('E1157',#1599,#2012,#2027,.T.);
#2029=ORIENTED_EDGE('',*,*,#2028,.T.);
#2030=EDGE_LOOP('',(#2016,#2022,#2023,#2029));
#2031=FACE_BOUND('',#2030,.T.);
#2032=ADVANCED_FACE('F665',(#2031),#2006,.T.);
#2033=CARTESIAN_POINT('',(498.5,985.,40.0000000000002));
#2034=DIRECTION('',(0.,-1.,0.));
#2035=DIRECTION('',(0.,0.,-1.));
#2036=AXIS2_PLACEMENT_3D('',#2033,#2034,#2035);
#2037=PLANE('',#2036);
#2038=ORIENTED_EDGE('',*,*,#1990,.T.);
#2039=DIRECTION('',(0.,0.,-1.));
#2040=VECTOR('',#2039,1.);
#2041=CARTESIAN_POINT('',(16.5707106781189,985.,39.9999999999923));
#2042=LINE('',#2041,#2040);
#2043=EDGE_CURVE('E1170',#1981,#2014,#2042,.T.);
#2044=ORIENTED_EDGE('',*,*,#2043,.T.);
#2045=ORIENTED_EDGE('',*,*,#2015,.F.);
#2046=DIRECTION('',(0.,0.,1.));
#2047=VECTOR('',#2046,1.);
#2048=CARTESIAN_POINT('',(483.429289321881,985.,40.0000000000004));
#2049=LINE('',#2048,#2047);
#2050=EDGE_CURVE('E1160',#2012,#1989,#2049,.T.);
#2051=ORIENTED_EDGE('',*,*,#2050,.T.);
#2052=EDGE_LOOP('',(#2038,#2044,#2045,#2051));
#2053=FACE_BOUND('',#2052,.T.);
#2054=ADVANCED_FACE('F663',(#2053),#2037,.T.);
#2055=CARTESIAN_POINT('',(498.429289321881,1000.,40.));
#2056=DIRECTION('',(0.707106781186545,-0.70710678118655,0.));
#2057=DIRECTION('',(0.70710678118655,0.707106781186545,0.));
#2058=AXIS2_PLACEMENT_3D('',#2055,#2056,#2057);
#2059=PLANE('',#2058);
#2060=ORIENTED_EDGE('',*,*,#2028,.F.);
#2061=ORIENTED_EDGE('',*,*,#1600,.F.);
#2062=ORIENTED_EDGE('',*,*,#1996,.T.);
#2063=ORIENTED_EDGE('',*,*,#2050,.F.);
#2064=EDGE_LOOP('',(#2060,#2061,#2062,#2063));
#2065=FACE_BOUND('',#2064,.T.);
#2066=ADVANCED_FACE('F659',(#2065),#2059,.T.);
#2067=CARTESIAN_POINT('',(353.06324948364,648.507461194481,40.0000000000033));
#2068=DIRECTION('',(-0.707106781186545,-0.70710678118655,0.));
#2069=DIRECTION('',(0.70710678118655,-0.707106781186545,0.));
#2070=AXIS2_PLACEMENT_3D('',#2067,#2068,#2069);
#2071=PLANE('',#2070);
#2072=ORIENTED_EDGE('',*,*,#2021,.F.);
#2073=ORIENTED_EDGE('',*,*,#2043,.F.);
#2074=ORIENTED_EDGE('',*,*,#1982,.T.);
#2075=ORIENTED_EDGE('',*,*,#1861,.T.);
#2076=EDGE_LOOP('',(#2072,#2073,#2074,#2075));
#2077=FACE_BOUND('',#2076,.T.);
#2078=ADVANCED_FACE('F645',(#2077),#2071,.T.);
#2079=CARTESIAN_POINT('',(498.5,0.,38.5));
#2080=DIRECTION('',(0.,-1.,0.));
#2081=DIRECTION('',(0.,0.,-1.));
#2082=AXIS2_PLACEMENT_3D('',#2079,#2080,#2081);
#2083=PLANE('',#2082);
#2084=DIRECTION('',(0.,0.,1.));
#2085=VECTOR('',#2084,1.);
#2086=CARTESIAN_POINT('',(498.5,0.,40.));
#2087=LINE('',#2086,#2085);
#2088=CARTESIAN_POINT('',(498.5,0.,39.25));
#2089=VERTEX_POINT('',#2088);
#2090=CARTESIAN_POINT('',(498.5,0.,40.));
#2091=VERTEX_POINT('',#2090);
#2092=EDGE_CURVE('E584',#2089,#2091,#2087,.T.);
#2093=ORIENTED_EDGE('',*,*,#2092,.F.);
#2094=CARTESIAN_POINT('',(498.5,0.,38.5));
#2095=DIRECTION('',(0.,1.,0.));
#2096=DIRECTION('',(0.,0.,1.));
#2097=AXIS2_PLACEMENT_3D('',#2094,#2095,#2096);
#2098=CIRCLE('',#2097,0.750000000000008);
#2099=EDGE_CURVE('E608',#702,#2089,#2098,.F.);
#2100=ORIENTED_EDGE('',*,*,#2099,.F.);
#2101=ORIENTED_EDGE('',*,*,#703,.F.);
#2102=CARTESIAN_POINT('',(498.5,0.,38.5));
#2103=DIRECTION('',(0.,1.,0.));
#2104=DIRECTION('',(0.,0.,1.));
#2105=AXIS2_PLACEMENT_3D('',#2102,#2103,#2104);
#2106=CIRCLE('',#2105,1.50000000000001);
#2107=EDGE_CURVE('E612',#694,#2091,#2106,.F.);
#2108=ORIENTED_EDGE('',*,*,#2107,.T.);
#2109=EDGE_LOOP('',(#2093,#2100,#2101,#2108));
#2110=FACE_BOUND('',#2109,.T.);
#2111=ADVANCED_FACE('F642',(#2110),#2083,.T.);
#2112=CARTESIAN_POINT('',(498.5,999.929289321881,40.0075));
#2113=CARTESIAN_POINT('',(498.69736683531,999.935182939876,40.0075));
#2114=CARTESIAN_POINT('',(498.894584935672,999.941074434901,39.9682638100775));
#2115=CARTESIAN_POINT('',(499.259205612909,999.952859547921,39.8172329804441));
#2116=CARTESIAN_POINT('',(499.426429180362,999.958752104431,39.7054977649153));
#2117=CARTESIAN_POINT('',(499.705497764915,999.97053721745,39.4264291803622));
#2118=CARTESIAN_POINT('',(499.817232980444,999.97642977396,39.2592056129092));
#2119=CARTESIAN_POINT('',(499.968263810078,999.98821488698,38.8945849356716));
#2120=CARTESIAN_POINT('',(500.0075,999.994106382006,38.6973668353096));
#2121=CARTESIAN_POINT('',(500.0075,1000.,38.5));
#2122=CARTESIAN_POINT('',(498.5,999.929289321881,40.));
#2123=CARTESIAN_POINT('',(498.696384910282,999.935182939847,40.));
#2124=CARTESIAN_POINT('',(498.892621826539,999.941074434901,39.9609590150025));
#2125=CARTESIAN_POINT('',(499.255428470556,999.952859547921,39.8106795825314));
#2126=CARTESIAN_POINT('',(499.421820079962,999.958752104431,39.6995002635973));
#2127=CARTESIAN_POINT('',(499.699500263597,999.97053721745,39.4218200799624));
#2128=CARTESIAN_POINT('',(499.810679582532,999.97642977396,39.2554284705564));
#2129=CARTESIAN_POINT('',(499.960959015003,999.98821488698,38.8926218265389));
#2130=CARTESIAN_POINT('',(500.,999.994106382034,38.6963849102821));
#2131=CARTESIAN_POINT('',(500.,1000.,38.5));
#2132=CARTESIAN_POINT('',(498.5,999.929289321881,39.25));
#2133=CARTESIAN_POINT('',(498.59819240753,999.935182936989,39.25));
#2134=CARTESIAN_POINT('',(498.69631091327,999.941074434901,39.2304795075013));
#2135=CARTESIAN_POINT('',(498.877714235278,999.952859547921,39.1553397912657));
#2136=CARTESIAN_POINT('',(498.960910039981,999.958752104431,39.0997501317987));
#2137=CARTESIAN_POINT('',(499.099750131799,999.97053721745,38.9609100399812));
#2138=CARTESIAN_POINT('',(499.155339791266,999.97642977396,38.8777142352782));
#2139=CARTESIAN_POINT('',(499.230479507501,999.98821488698,38.6963109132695));
#2140=CARTESIAN_POINT('',(499.25,999.994106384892,38.5981924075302));
#2141=CARTESIAN_POINT('',(499.25,1000.,38.5));
#2142=CARTESIAN_POINT('',(498.5,999.929289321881,39.242425));
#2143=CARTESIAN_POINT('',(498.597200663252,999.93518293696,39.242425));
#2144=CARTESIAN_POINT('',(498.694328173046,999.941074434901,39.2231016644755));
#2145=CARTESIAN_POINT('',(498.873899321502,999.952859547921,39.1487208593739));
#2146=CARTESIAN_POINT('',(498.956254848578,999.958752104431,39.0936926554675));
#2147=CARTESIAN_POINT('',(499.093692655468,999.97053721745,38.9562548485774));
#2148=CARTESIAN_POINT('',(499.148720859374,999.97642977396,38.8738993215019));
#2149=CARTESIAN_POINT('',(499.223101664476,999.98821488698,38.6943281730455));
#2150=CARTESIAN_POINT('',(499.242425,999.994106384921,38.5972006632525));
#2151=CARTESIAN_POINT('',(499.242425,1000.,38.5));
#2152=B_SPLINE_SURFACE_WITH_KNOTS('',1,3,((#2112,#2113,#2114,#2115,#2116,#2117,#2118,#2119,
#2120,#2121),(#2122,#2123,#2124,#2125,#2126,#2127,#2128,#2129,#2130,#2131),(#2132,#2133,#2134,
#2135,#2136,#2137,#2138,#2139,#2140,#2141),(#2142,#2143,#2144,#2145,#2146,#2147,#2148,#2149,
#2150,#2151)),.UNSPECIFIED.,.F.,.F.,.F.,(2,1,1,2),(4,2,2,2,4),(-0.01,0.,1.,1.0101),(0.,0.25,0.5,
0.75,1.),.UNSPECIFIED.);
#2153=CARTESIAN_POINT('',(498.5,999.929289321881,39.25));
#2154=CARTESIAN_POINT('',(498.512271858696,999.930025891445,39.2500002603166));
#2155=CARTESIAN_POINT('',(498.524543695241,999.930762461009,39.2496988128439));
#2156=CARTESIAN_POINT('',(498.54905781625,999.932235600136,39.2484943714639));
#2157=CARTESIAN_POINT('',(498.561300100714,999.9329721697,39.2475913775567));
#2158=CARTESIAN_POINT('',(498.58572560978,999.934445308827,39.2451857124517));
#2159=CARTESIAN_POINT('',(498.597908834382,999.935181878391,39.2436830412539));
#2160=CARTESIAN_POINT('',(498.622186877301,999.936655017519,39.2400817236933));
#2161=CARTESIAN_POINT('',(498.634281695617,999.937391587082,39.2379830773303));
#2162=CARTESIAN_POINT('',(498.658353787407,999.93886472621,39.2331948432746));
#2163=CARTESIAN_POINT('',(498.670331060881,999.939601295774,39.2305052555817));
#2164=CARTESIAN_POINT('',(498.694139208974,999.941074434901,39.2245416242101));
#2165=CARTESIAN_POINT('',(498.705970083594,999.941811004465,39.2212675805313));
#2166=CARTESIAN_POINT('',(498.729456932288,999.943284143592,39.2141429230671));
#2167=CARTESIAN_POINT('',(498.741112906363,999.944020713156,39.2102923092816));
#2168=CARTESIAN_POINT('',(498.764221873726,999.945493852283,39.202023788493));
#2169=CARTESIAN_POINT('',(498.775674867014,999.946230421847,39.1976058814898));
#2170=CARTESIAN_POINT('',(498.798350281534,999.947703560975,39.1882134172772));
#2171=CARTESIAN_POINT('',(498.809572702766,999.948440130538,39.1832388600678));
#2172=CARTESIAN_POINT('',(498.83175993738,999.949913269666,39.1727450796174));
#2173=CARTESIAN_POINT('',(498.842724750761,999.95064983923,39.1672258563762));
#2174=CARTESIAN_POINT('',(498.864370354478,999.952122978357,39.1556560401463));
#2175=CARTESIAN_POINT('',(498.875051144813,999.952859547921,39.1496054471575));
#2176=CARTESIAN_POINT('',(498.896102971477,999.954332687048,39.1369874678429));
#2177=CARTESIAN_POINT('',(498.906474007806,999.955069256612,39.1304200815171));
#2178=CARTESIAN_POINT('',(498.926881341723,999.956542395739,39.1167843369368));
#2179=CARTESIAN_POINT('',(498.936917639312,999.957278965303,39.1097159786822));
#2180=CARTESIAN_POINT('',(498.956631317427,999.958752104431,39.0950953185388));
#2181=CARTESIAN_POINT('',(498.966308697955,999.959488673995,39.0875430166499));
#2182=CARTESIAN_POINT('',(498.985281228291,999.960961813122,39.0719726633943));
#2183=CARTESIAN_POINT('',(498.9945763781,999.961698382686,39.0639546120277));
#2184=CARTESIAN_POINT('',(499.01276205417,999.963171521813,39.0474720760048));
#2185=CARTESIAN_POINT('',(499.021652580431,999.963908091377,39.0390075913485));
#2186=CARTESIAN_POINT('',(499.039007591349,999.965381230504,39.0216525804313));
#2187=CARTESIAN_POINT('',(499.047472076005,999.966117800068,39.0127620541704));
#2188=CARTESIAN_POINT('',(499.063954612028,999.967590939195,38.9945763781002));
#2189=CARTESIAN_POINT('',(499.071972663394,999.968327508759,38.985281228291));
#2190=CARTESIAN_POINT('',(499.08754301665,999.969800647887,38.9663086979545));
#2191=CARTESIAN_POINT('',(499.095095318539,999.97053721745,38.9566313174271));
#2192=CARTESIAN_POINT('',(499.109715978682,999.972010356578,38.9369176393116));
#2193=CARTESIAN_POINT('',(499.116784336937,999.972746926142,38.9268813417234));
#2194=CARTESIAN_POINT('',(499.130420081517,999.974220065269,38.9064740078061));
#2195=CARTESIAN_POINT('',(499.136987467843,999.974956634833,38.896102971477));
#2196=CARTESIAN_POINT('',(499.149605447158,999.97642977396,38.8750511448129));
#2197=CARTESIAN_POINT('',(499.155656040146,999.977166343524,38.8643703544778));
#2198=CARTESIAN_POINT('',(499.167225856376,999.978639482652,38.8427247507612));
#2199=CARTESIAN_POINT('',(499.172745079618,999.979376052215,38.8317599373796));
#2200=CARTESIAN_POINT('',(499.183238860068,999.980849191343,38.8095727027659));
#2201=CARTESIAN_POINT('',(499.188213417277,999.981585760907,38.7983502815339));
#2202=CARTESIAN_POINT('',(499.19760588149,999.983058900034,38.7756748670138));
#2203=CARTESIAN_POINT('',(499.202023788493,999.983795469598,38.7642218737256));
#2204=CARTESIAN_POINT('',(499.210292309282,999.985268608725,38.7411129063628));
#2205=CARTESIAN_POINT('',(499.214142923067,999.986005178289,38.729456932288));
#2206=CARTESIAN_POINT('',(499.221267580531,999.987478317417,38.7059700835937));
#2207=CARTESIAN_POINT('',(499.22454162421,999.98821488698,38.6941392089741));
#2208=CARTESIAN_POINT('',(499.230505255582,999.989688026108,38.6703310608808));
#2209=CARTESIAN_POINT('',(499.233194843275,999.990424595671,38.6583537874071));
#2210=CARTESIAN_POINT('',(499.23798307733,999.991897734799,38.6342816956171));
#2211=CARTESIAN_POINT('',(499.240081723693,999.992634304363,38.6221868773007));
#2212=CARTESIAN_POINT('',(499.243683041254,999.99410744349,38.5979088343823));
#2213=CARTESIAN_POINT('',(499.245185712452,999.994844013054,38.5857256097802));
#2214=CARTESIAN_POINT('',(499.247591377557,999.996317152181,38.5613001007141));
#2215=CARTESIAN_POINT('',(499.248494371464,999.997053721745,38.5490578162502));
#2216=CARTESIAN_POINT('',(499.249698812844,999.998526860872,38.5245436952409));
#2217=CARTESIAN_POINT('',(499.250000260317,999.999263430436,38.5122718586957));
#2218=CARTESIAN_POINT('',(499.25,1000.,38.5));
#2219=B_SPLINE_CURVE_WITH_KNOTS('',3,(#2153,#2154,#2155,#2156,#2157,#2158,#2159,#2160,#2161,
#2162,#2163,#2164,#2165,#2166,#2167,#2168,#2169,#2170,#2171,#2172,#2173,#2174,#2175,#2176,#2177,
#2178,#2179,#2180,#2181,#2182,#2183,#2184,#2185,#2186,#2187,#2188,#2189,#2190,#2191,#2192,#2193,
#2194,#2195,#2196,#2197,#2198,#2199,#2200,#2201,#2202,#2203,#2204,#2205,#2206,#2207,#2208,#2209,
#2210,#2211,#2212,#2213,#2214,#2215,#2216,#2217,#2218),.UNSPECIFIED.,.F.,.F.,(4,2,2,2,2,2,2,2,2,
2,2,2,2,2,2,2,2,2,2,2,2,2,2,2,2,2,2,2,2,2,2,2,4),(0.,0.0368781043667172,0.0737562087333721,
0.110634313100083,0.147512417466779,0.184390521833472,0.221268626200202,0.258146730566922,
0.295024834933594,0.331902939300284,0.368781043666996,0.405659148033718,0.44253725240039,
0.47941535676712,0.51629346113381,0.553171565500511,0.590049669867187,0.626927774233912,
0.663805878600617,0.700683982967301,0.737562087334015,0.774440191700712,0.811318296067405,
0.848196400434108,0.885074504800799,0.921952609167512,0.958830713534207,0.995708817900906,
1.0325869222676,1.06946502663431,1.10634313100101,1.1432212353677,1.18009933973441),.UNSPECIFIED.);
#2220=CARTESIAN_POINT('',(498.5,999.929289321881,39.25));
#2221=VERTEX_POINT('',#2220);
#2222=EDGE_CURVE('E588',#2221,#725,#2219,.T.);
#2223=DIRECTION('',(0.,0.,1.));
#2224=VECTOR('',#2223,1.);
#2225=CARTESIAN_POINT('',(498.5,999.929289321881,39.25));
#2226=LINE('',#2225,#2224);
#2227=CARTESIAN_POINT('',(498.5,999.929289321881,40.));
#2228=VERTEX_POINT('',#2227);
#2229=EDGE_CURVE('E585',#2228,#2221,#2226,.F.);
#2230=CARTESIAN_POINT('',(498.5,999.929289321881,40.));
#2231=CARTESIAN_POINT('',(498.524543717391,999.930025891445,40.0000005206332));
#2232=CARTESIAN_POINT('',(498.549087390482,999.930762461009,39.9993976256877));
#2233=CARTESIAN_POINT('',(498.5981156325,999.932235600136,39.9969887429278));
#2234=CARTESIAN_POINT('',(498.622600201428,999.9329721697,39.9951827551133));
#2235=CARTESIAN_POINT('',(498.67145121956,999.934445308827,39.9903714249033));
#2236=CARTESIAN_POINT('',(498.695817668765,999.935181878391,39.9873660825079));
#2237=CARTESIAN_POINT('',(498.744373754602,999.936655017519,39.9801634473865));
#2238=CARTESIAN_POINT('',(498.768563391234,999.937391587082,39.9759661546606));
#2239=CARTESIAN_POINT('',(498.816707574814,999.93886472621,39.9663896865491));
#2240=CARTESIAN_POINT('',(498.840662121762,999.939601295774,39.9610105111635));
#2241=CARTESIAN_POINT('',(498.888278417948,999.941074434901,39.9490832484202));
#2242=CARTESIAN_POINT('',(498.911940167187,999.941811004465,39.9425351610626));
#2243=CARTESIAN_POINT('',(498.958913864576,999.943284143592,39.9282858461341));
#2244=CARTESIAN_POINT('',(498.982225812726,999.944020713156,39.9205846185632));
#2245=CARTESIAN_POINT('',(499.028443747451,999.945493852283,39.9040475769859));
#2246=CARTESIAN_POINT('',(499.051349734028,999.946230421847,39.8952117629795));
#2247=CARTESIAN_POINT('',(499.096700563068,999.947703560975,39.8764268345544));
#2248=CARTESIAN_POINT('',(499.119145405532,999.948440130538,39.8664777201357));
#2249=CARTESIAN_POINT('',(499.163519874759,999.949913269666,39.8454901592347));
#2250=CARTESIAN_POINT('',(499.185449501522,999.95064983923,39.8344517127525));
#2251=CARTESIAN_POINT('',(499.228740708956,999.952122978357,39.8113120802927));
#2252=CARTESIAN_POINT('',(499.250102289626,999.952859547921,39.7992108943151));
#2253=CARTESIAN_POINT('',(499.292205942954,999.954332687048,39.7739749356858));
#2254=CARTESIAN_POINT('',(499.312948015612,999.955069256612,39.7608401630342));
#2255=CARTESIAN_POINT('',(499.353762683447,999.956542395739,39.7335686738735));
#2256=CARTESIAN_POINT('',(499.373835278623,999.957278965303,39.7194319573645));
#2257=CARTESIAN_POINT('',(499.413262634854,999.958752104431,39.6901906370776));
#2258=CARTESIAN_POINT('',(499.432617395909,999.959488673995,39.6750860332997));
#2259=CARTESIAN_POINT('',(499.470562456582,999.960961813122,39.6439453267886));
#2260=CARTESIAN_POINT('',(499.4891527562,999.961698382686,39.6279092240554));
#2261=CARTESIAN_POINT('',(499.525524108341,999.963171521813,39.5949441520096));
#2262=CARTESIAN_POINT('',(499.543305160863,999.963908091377,39.5780151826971));
#2263=CARTESIAN_POINT('',(499.578015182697,999.965381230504,39.5433051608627));
#2264=CARTESIAN_POINT('',(499.59494415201,999.966117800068,39.5255241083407));
#2265=CARTESIAN_POINT('',(499.627909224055,999.967590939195,39.4891527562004));
#2266=CARTESIAN_POINT('',(499.643945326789,999.968327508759,39.4705624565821));
#2267=CARTESIAN_POINT('',(499.6750860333,999.969800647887,39.432617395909));
#2268=CARTESIAN_POINT('',(499.690190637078,999.97053721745,39.4132626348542));
#2269=CARTESIAN_POINT('',(499.719431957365,999.972010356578,39.3738352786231));
#2270=CARTESIAN_POINT('',(499.733568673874,999.972746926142,39.3537626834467));
#2271=CARTESIAN_POINT('',(499.760840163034,999.974220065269,39.3129480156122));
#2272=CARTESIAN_POINT('',(499.773974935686,999.974956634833,39.292205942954));
#2273=CARTESIAN_POINT('',(499.799210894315,999.97642977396,39.2501022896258));
#2274=CARTESIAN_POINT('',(499.811312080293,999.977166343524,39.2287407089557));
#2275=CARTESIAN_POINT('',(499.834451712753,999.978639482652,39.1854495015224));
#2276=CARTESIAN_POINT('',(499.845490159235,999.979376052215,39.1635198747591));
#2277=CARTESIAN_POINT('',(499.866477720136,999.980849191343,39.1191454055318));
#2278=CARTESIAN_POINT('',(499.876426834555,999.981585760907,39.0967005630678));
#2279=CARTESIAN_POINT('',(499.89521176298,999.983058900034,39.0513497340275));
#2280=CARTESIAN_POINT('',(499.904047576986,999.983795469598,39.0284437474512));
#2281=CARTESIAN_POINT('',(499.920584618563,999.985268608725,38.9822258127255));
#2282=CARTESIAN_POINT('',(499.928285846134,999.986005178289,38.958913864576));
#2283=CARTESIAN_POINT('',(499.942535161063,999.987478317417,38.9119401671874));
#2284=CARTESIAN_POINT('',(499.94908324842,999.98821488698,38.8882784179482));
#2285=CARTESIAN_POINT('',(499.961010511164,999.989688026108,38.8406621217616));
#2286=CARTESIAN_POINT('',(499.966389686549,999.990424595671,38.8167075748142));
#2287=CARTESIAN_POINT('',(499.975966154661,999.991897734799,38.7685633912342));
#2288=CARTESIAN_POINT('',(499.980163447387,999.992634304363,38.7443737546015));
#2289=CARTESIAN_POINT('',(499.987366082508,999.99410744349,38.6958176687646));
#2290=CARTESIAN_POINT('',(499.990371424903,999.994844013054,38.6714512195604));
#2291=CARTESIAN_POINT('',(499.995182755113,999.996317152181,38.6226002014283));
#2292=CARTESIAN_POINT('',(499.996988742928,999.997053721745,38.5981156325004));
#2293=CARTESIAN_POINT('',(499.999397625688,999.998526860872,38.5490873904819));
#2294=CARTESIAN_POINT('',(500.000000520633,999.999263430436,38.5245437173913));
#2295=CARTESIAN_POINT('',(500.,1000.,38.5));
#2296=B_SPLINE_CURVE_WITH_KNOTS('',3,(#2230,#2231,#2232,#2233,#2234,#2235,#2236,#2237,#2238,
#2239,#2240,#2241,#2242,#2243,#2244,#2245,#2246,#2247,#2248,#2249,#2250,#2251,#2252,#2253,#2254,
#2255,#2256,#2257,#2258,#2259,#2260,#2261,#2262,#2263,#2264,#2265,#2266,#2267,#2268,#2269,#2270,
#2271,#2272,#2273,#2274,#2275,#2276,#2277,#2278,#2279,#2280,#2281,#2282,#2283,#2284,#2285,#2286,
#2287,#2288,#2289,#2290,#2291,#2292,#2293,#2294,#2295),.UNSPECIFIED.,.F.,.F.,(4,2,2,2,2,2,2,2,2,
2,2,2,2,2,2,2,2,2,2,2,2,2,2,2,2,2,2,2,2,2,2,2,4),(0.,0.0736568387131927,0.147313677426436,
0.220970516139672,0.294627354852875,0.368284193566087,0.441941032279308,0.515597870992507,
0.589254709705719,0.662911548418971,0.736568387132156,0.810225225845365,0.883882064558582,
0.957538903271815,1.03119574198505,1.10485258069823,1.17850941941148,1.2521662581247,
1.3258230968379,1.39947993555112,1.47313677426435,1.54679361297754,1.62045045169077,
1.69410729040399,1.76776412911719,1.84142096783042,1.91507780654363,1.98873464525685,
2.06239148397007,2.13604832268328,2.2097051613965,2.28336200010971,2.35701883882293),.UNSPECIFIED.);
#2297=EDGE_CURVE('E611',#2228,#733,#2296,.T.);
#2298=ORIENTED_EDGE('',*,*,#2222,.F.);
#2299=ORIENTED_EDGE('',*,*,#2229,.F.);
#2300=ORIENTED_EDGE('',*,*,#2297,.T.);
#2301=ORIENTED_EDGE('',*,*,#734,.T.);
#2302=EDGE_LOOP('',(#2298,#2299,#2300,#2301));
#2303=FACE_BOUND('',#2302,.T.);
#2304=ADVANCED_FACE('F635',(#2303),#2152,.F.);
#2305=CARTESIAN_POINT('',(498.5,1000.,38.5));
#2306=DIRECTION('',(0.,1.,0.));
#2307=DIRECTION('',(0.,0.,1.));
#2308=AXIS2_PLACEMENT_3D('',#2305,#2306,#2307);
#2309=CYLINDRICAL_SURFACE('',#2308,1.50000000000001);
#2310=ORIENTED_EDGE('',*,*,#756,.F.);
#2311=ORIENTED_EDGE('',*,*,#2297,.F.);
#2312=DIRECTION('',(0.,1.,0.));
#2313=VECTOR('',#2312,1.);
#2314=CARTESIAN_POINT('',(498.5,0.,40.));
#2315=LINE('',#2314,#2313);
#2316=EDGE_CURVE('E602',#2228,#2091,#2315,.F.);
#2317=ORIENTED_EDGE('',*,*,#2316,.T.);
#2318=ORIENTED_EDGE('',*,*,#2107,.F.);
#2319=EDGE_LOOP('',(#2310,#2311,#2317,#2318));
#2320=FACE_BOUND('',#2319,.T.);
#2321=ADVANCED_FACE('F633',(#2320),#2309,.T.);
#2322=CARTESIAN_POINT('',(498.5,1000.,38.5));
#2323=DIRECTION('',(0.,1.,0.));
#2324=DIRECTION('',(0.,0.,1.));
#2325=AXIS2_PLACEMENT_3D('',#2322,#2323,#2324);
#2326=CYLINDRICAL_SURFACE('',#2325,0.750000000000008);
#2327=ORIENTED_EDGE('',*,*,#774,.T.);
#2328=ORIENTED_EDGE('',*,*,#2099,.T.);
#2329=DIRECTION('',(0.,1.,0.));
#2330=VECTOR('',#2329,1.);
#2331=CARTESIAN_POINT('',(498.5,0.,39.25));
#2332=LINE('',#2331,#2330);
#2333=EDGE_CURVE('E604',#2089,#2221,#2332,.T.);
#2334=ORIENTED_EDGE('',*,*,#2333,.T.);
#2335=ORIENTED_EDGE('',*,*,#2222,.T.);
#2336=EDGE_LOOP('',(#2327,#2328,#2334,#2335));
#2337=FACE_BOUND('',#2336,.T.);
#2338=ADVANCED_FACE('F623',(#2337),#2326,.F.);
#2339=CARTESIAN_POINT('',(483.5,0.,40.0000000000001));
#2340=DIRECTION('',(0.,0.,-1.));
#2341=DIRECTION('',(-1.,0.,0.));
#2342=AXIS2_PLACEMENT_3D('',#2339,#2340,#2341);
#2343=PLANE('',#2342);
#2344=DIRECTION('',(0.707106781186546,0.707106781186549,0.));
#2345=VECTOR('',#2344,1.);
#2346=CARTESIAN_POINT('',(-208.636530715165,292.792758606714,40.0000000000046));
#2347=LINE('',#2346,#2345);
#2348=CARTESIAN_POINT('',(483.5,984.929289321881,40.0000000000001));
#2349=VERTEX_POINT('',#2348);
#2350=EDGE_CURVE('E493',#2349,#2228,#2347,.T.);
#2351=ORIENTED_EDGE('',*,*,#2350,.F.);
#2352=DIRECTION('',(0.,-1.,0.));
#2353=VECTOR('',#2352,1.);
#2354=CARTESIAN_POINT('',(483.5,0.,40.0000000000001));
#2355=LINE('',#2354,#2353);
#2356=CARTESIAN_POINT('',(483.5,0.,40.0000000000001));
#2357=VERTEX_POINT('',#2356);
#2358=EDGE_CURVE('E592',#2357,#2349,#2355,.F.);
#2359=ORIENTED_EDGE('',*,*,#2358,.F.);
#2360=DIRECTION('',(1.,0.,0.));
#2361=VECTOR('',#2360,1.);
#2362=CARTESIAN_POINT('',(499.25,0.,40.));
#2363=LINE('',#2362,#2361);
#2364=EDGE_CURVE('E595',#2091,#2357,#2363,.F.);
#2365=ORIENTED_EDGE('',*,*,#2364,.F.);
#2366=ORIENTED_EDGE('',*,*,#2316,.F.);
#2367=EDGE_LOOP('',(#2351,#2359,#2365,#2366));
#2368=FACE_BOUND('',#2367,.T.);
#2369=ADVANCED_FACE('F632',(#2368),#2343,.F.);
#2370=CARTESIAN_POINT('',(483.5,0.,39.2500000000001));
#2371=DIRECTION('',(0.,0.,-1.));
#2372=DIRECTION('',(-1.,0.,0.));
#2373=AXIS2_PLACEMENT_3D('',#2370,#2371,#2372);
#2374=PLANE('',#2373);
#2375=DIRECTION('',(0.,1.,0.));
#2376=VECTOR('',#2375,1.);
#2377=CARTESIAN_POINT('',(483.5,0.,39.2500000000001));
#2378=LINE('',#2377,#2376);
#2379=CARTESIAN_POINT('',(483.5,0.,39.2500000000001));
#2380=VERTEX_POINT('',#2379);
#2381=CARTESIAN_POINT('',(483.5,984.929289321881,39.2500000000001));
#2382=VERTEX_POINT('',#2381);
#2383=EDGE_CURVE('E597',#2380,#2382,#2378,.T.);
#2384=ORIENTED_EDGE('',*,*,#2383,.T.);
#2385=DIRECTION('',(0.707106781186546,0.707106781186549,0.));
#2386=VECTOR('',#2385,1.);
#2387=CARTESIAN_POINT('',(-8.96464466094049,492.464644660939,39.2500000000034));
#2388=LINE('',#2387,#2386);
#2389=EDGE_CURVE('E581',#2382,#2221,#2388,.T.);
#2390=ORIENTED_EDGE('',*,*,#2389,.T.);
#2391=ORIENTED_EDGE('',*,*,#2333,.F.);
#2392=DIRECTION('',(-1.,0.,0.));
#2393=VECTOR('',#2392,1.);
#2394=CARTESIAN_POINT('',(483.5,0.,39.2500000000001));
#2395=LINE('',#2394,#2393);
#2396=EDGE_CURVE('E600',#2089,#2380,#2395,.T.);
#2397=ORIENTED_EDGE('',*,*,#2396,.T.);
#2398=EDGE_LOOP('',(#2384,#2390,#2391,#2397));
#2399=FACE_BOUND('',#2398,.T.);
#2400=ADVANCED_FACE('F1708',(#2399),#2374,.T.);
#2401=CARTESIAN_POINT('',(483.5,0.,40.0000000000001));
#2402=DIRECTION('',(-1.,0.,0.));
#2403=DIRECTION('',(0.,0.,1.));
#2404=AXIS2_PLACEMENT_3D('',#2401,#2402,#2403);
#2405=PLANE('',#2404);
#2406=ORIENTED_EDGE('',*,*,#2358,.T.);
#2407=DIRECTION('',(0.,0.,-1.));
#2408=VECTOR('',#2407,1.);
#2409=CARTESIAN_POINT('',(483.5,984.929289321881,40.0000000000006));
#2410=LINE('',#2409,#2408);
#2411=EDGE_CURVE('E579',#2349,#2382,#2410,.T.);
#2412=ORIENTED_EDGE('',*,*,#2411,.T.);
#2413=ORIENTED_EDGE('',*,*,#2383,.F.);
#2414=DIRECTION('',(0.,0.,-1.));
#2415=VECTOR('',#2414,1.);
#2416=CARTESIAN_POINT('',(483.5,0.,40.0000000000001));
#2417=LINE('',#2416,#2415);
#2418=EDGE_CURVE('E589',#2357,#2380,#2417,.T.);
#2419=ORIENTED_EDGE('',*,*,#2418,.F.);
#2420=EDGE_LOOP('',(#2406,#2412,#2413,#2419));
#2421=FACE_BOUND('',#2420,.T.);
#2422=ADVANCED_FACE('F1719',(#2421),#2405,.T.);
#2423=CARTESIAN_POINT('',(499.25,0.,40.));
#2424=DIRECTION('',(0.,-1.,0.));
#2425=DIRECTION('',(0.,0.,-1.));
#2426=AXIS2_PLACEMENT_3D('',#2423,#2424,#2425);
#2427=PLANE('',#2426);
#2428=ORIENTED_EDGE('',*,*,#2396,.F.);
#2429=ORIENTED_EDGE('',*,*,#2092,.T.);
#2430=ORIENTED_EDGE('',*,*,#2364,.T.);
#2431=ORIENTED_EDGE('',*,*,#2418,.T.);
#2432=EDGE_LOOP('',(#2428,#2429,#2430,#2431));
#2433=FACE_BOUND('',#2432,.T.);
#2434=ADVANCED_FACE('F636',(#2433),#2427,.T.);
#2435=CARTESIAN_POINT('',(-208.636530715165,292.792758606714,40.0000000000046));
#2436=DIRECTION('',(-0.707106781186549,0.707106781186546,0.));
#2437=DIRECTION('',(-0.707106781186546,-0.707106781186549,0.));
#2438=AXIS2_PLACEMENT_3D('',#2435,#2436,#2437);
#2439=PLANE('',#2438);
#2440=ORIENTED_EDGE('',*,*,#2389,.F.);
#2441=ORIENTED_EDGE('',*,*,#2411,.F.);
#2442=ORIENTED_EDGE('',*,*,#2350,.T.);
#2443=ORIENTED_EDGE('',*,*,#2229,.T.);
#2444=EDGE_LOOP('',(#2440,#2441,#2442,#2443));
#2445=FACE_BOUND('',#2444,.T.);
#2446=ADVANCED_FACE('F1739',(#2445),#2439,.T.);
#2447=CARTESIAN_POINT('',(-58.6487222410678,1060.07801156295,40.0010000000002));
#2448=DIRECTION('',(-0.707106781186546,-0.707106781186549,0.));
#2449=DIRECTION('',(0.707106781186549,-0.707106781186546,0.));
#2450=AXIS2_PLACEMENT_3D('',#2447,#2448,#2449);
#2451=PLANE('',#2450);
#2452=ORIENTED_EDGE('',*,*,#40,.T.);
#2453=DIRECTION('',(0.,0.,-1.));
#2454=VECTOR('',#2453,1.);
#2455=CARTESIAN_POINT('',(79.9999999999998,921.429289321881,40.0010000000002));
#2456=LINE('',#2455,#2454);
#2457=EDGE_CURVE('E494',#31,#203,#2456,.T.);
#2458=ORIENTED_EDGE('',*,*,#2457,.T.);
#2459=ORIENTED_EDGE('',*,*,#206,.T.);
#2460=DIRECTION('',(0.,0.,-1.));
#2461=VECTOR('',#2460,1.);
#2462=CARTESIAN_POINT('',(69.9208670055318,931.508422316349,40.0010000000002));
#2463=LINE('',#2462,#2461);
#2464=EDGE_CURVE('E477',#39,#205,#2463,.T.);
#2465=ORIENTED_EDGE('',*,*,#2464,.F.);
#2466=EDGE_LOOP('',(#2452,#2458,#2459,#2465));
#2467=FACE_BOUND('',#2466,.T.);
#2468=ADVANCED_FACE('F479',(#2467),#2451,.F.);
#2469=CARTESIAN_POINT('',(79.9999999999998,500.,40.0010000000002));
#2470=DIRECTION('',(1.,0.,0.));
#2471=DIRECTION('',(0.,0.,-1.));
#2472=AXIS2_PLACEMENT_3D('',#2469,#2470,#2471);
#2473=PLANE('',#2472);
#2474=DIRECTION('',(0.,0.,-1.));
#2475=VECTOR('',#2474,1.);
#2476=CARTESIAN_POINT('',(79.9999999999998,421.570710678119,40.0010000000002));
#2477=LINE('',#2476,#2475);
#2478=EDGE_CURVE('E550',#29,#213,#2477,.T.);
#2479=ORIENTED_EDGE('',*,*,#2478,.T.);
#2480=ORIENTED_EDGE('',*,*,#214,.F.);
#2481=ORIENTED_EDGE('',*,*,#2457,.F.);
#2482=ORIENTED_EDGE('',*,*,#32,.F.);
#2483=EDGE_LOOP('',(#2479,#2480,#2481,#2482));
#2484=FACE_BOUND('',#2483,.T.);
#2485=ADVANCED_FACE('F1758',(#2484),#2473,.T.);
#2486=CARTESIAN_POINT('',(-230.14872224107,111.421988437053,40.0010000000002));
#2487=DIRECTION('',(0.707106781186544,-0.707106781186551,0.));
#2488=DIRECTION('',(0.707106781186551,0.707106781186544,0.));
#2489=AXIS2_PLACEMENT_3D('',#2486,#2487,#2488);
#2490=PLANE('',#2489);
#2491=DIRECTION('',(0.,0.,-1.));
#2492=VECTOR('',#2491,1.);
#2493=CARTESIAN_POINT('',(69.9208670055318,411.491577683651,40.0010000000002));
#2494=LINE('',#2493,#2492);
#2495=EDGE_CURVE('E552',#147,#221,#2494,.T.);
#2496=ORIENTED_EDGE('',*,*,#2495,.T.);
#2497=ORIENTED_EDGE('',*,*,#222,.F.);
#2498=ORIENTED_EDGE('',*,*,#2478,.F.);
#2499=ORIENTED_EDGE('',*,*,#154,.F.);
#2500=EDGE_LOOP('',(#2496,#2497,#2498,#2499));
#2501=FACE_BOUND('',#2500,.T.);
#2502=ADVANCED_FACE('F1778',(#2501),#2490,.T.);
#2503=CARTESIAN_POINT('',(69.2499999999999,410.75,40.0010000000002));
#2504=DIRECTION('',(0.,0.,-1.));
#2505=DIRECTION('',(-1.,0.,0.));
#2506=AXIS2_PLACEMENT_3D('',#2503,#2504,#2505);
#2507=CYLINDRICAL_SURFACE('',#2506,1.00000000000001);
#2508=DIRECTION('',(0.,0.,-1.));
#2509=VECTOR('',#2508,1.);
#2510=CARTESIAN_POINT('',(69.9915776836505,411.420867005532,40.0010000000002));
#2511=LINE('',#2510,#2509);
#2512=EDGE_CURVE('E554',#138,#230,#2511,.T.);
#2513=ORIENTED_EDGE('',*,*,#2512,.T.);
#2514=ORIENTED_EDGE('',*,*,#231,.F.);
#2515=ORIENTED_EDGE('',*,*,#2495,.F.);
#2516=ORIENTED_EDGE('',*,*,#148,.F.);
#2517=EDGE_LOOP('',(#2513,#2514,#2515,#2516));
#2518=FACE_BOUND('',#2517,.T.);
#2519=ADVANCED_FACE('F1789',(#2518),#2507,.F.);
#2520=CARTESIAN_POINT('',(-230.078011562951,111.351277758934,40.0010000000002));
#2521=DIRECTION('',(0.707106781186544,-0.707106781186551,0.));
#2522=DIRECTION('',(0.707106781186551,0.707106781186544,0.));
#2523=AXIS2_PLACEMENT_3D('',#2520,#2521,#2522);
#2524=PLANE('',#2523);
#2525=ORIENTED_EDGE('',*,*,#139,.T.);
#2526=DIRECTION('',(0.,0.,-1.));
#2527=VECTOR('',#2526,1.);
#2528=CARTESIAN_POINT('',(80.0707106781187,421.5,40.0010000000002));
#2529=LINE('',#2528,#2527);
#2530=EDGE_CURVE('E556',#130,#238,#2529,.T.);
#2531=ORIENTED_EDGE('',*,*,#2530,.T.);
#2532=ORIENTED_EDGE('',*,*,#239,.T.);
#2533=ORIENTED_EDGE('',*,*,#2512,.F.);
#2534=EDGE_LOOP('',(#2525,#2531,#2532,#2533));
#2535=FACE_BOUND('',#2534,.T.);
#2536=ADVANCED_FACE('F1809',(#2535),#2524,.F.);
#2537=CARTESIAN_POINT('',(-618.726733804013,421.5,40.0010000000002));
#2538=DIRECTION('',(0.,-1.,0.));
#2539=DIRECTION('',(0.,0.,-1.));
#2540=AXIS2_PLACEMENT_3D('',#2537,#2538,#2539);
#2541=PLANE('',#2540);
#2542=ORIENTED_EDGE('',*,*,#131,.T.);
#2543=DIRECTION('',(0.,0.,-1.));
#2544=VECTOR('',#2543,1.);
#2545=CARTESIAN_POINT('',(419.929289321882,421.5,40.0010000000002));
#2546=LINE('',#2545,#2544);
#2547=EDGE_CURVE('E558',#122,#246,#2546,.T.);
#2548=ORIENTED_EDGE('',*,*,#2547,.T.);
#2549=ORIENTED_EDGE('',*,*,#247,.T.);
#2550=ORIENTED_EDGE('',*,*,#2530,.F.);
#2551=EDGE_LOOP('',(#2542,#2548,#2549,#2550));
#2552=FACE_BOUND('',#2551,.T.);
#2553=ADVANCED_FACE('F1820',(#2552),#2541,.F.);
#2554=CARTESIAN_POINT('',(-138.648722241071,980.078011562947,40.0010000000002));
#2555=DIRECTION('',(0.707106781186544,0.707106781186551,0.));
#2556=DIRECTION('',(-0.707106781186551,0.707106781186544,0.));
#2557=AXIS2_PLACEMENT_3D('',#2554,#2555,#2556);
#2558=PLANE('',#2557);
#2559=DIRECTION('',(0.,0.,-1.));
#2560=VECTOR('',#2559,1.);
#2561=CARTESIAN_POINT('',(430.008422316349,411.420867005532,40.0010000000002));
#2562=LINE('',#2561,#2560);
#2563=EDGE_CURVE('E560',#114,#254,#2562,.T.);
#2564=ORIENTED_EDGE('',*,*,#2563,.T.);
#2565=ORIENTED_EDGE('',*,*,#255,.F.);
#2566=ORIENTED_EDGE('',*,*,#2547,.F.);
#2567=ORIENTED_EDGE('',*,*,#123,.F.);
#2568=EDGE_LOOP('',(#2564,#2565,#2566,#2567));
#2569=FACE_BOUND('',#2568,.T.);
#2570=ADVANCED_FACE('F1840',(#2569),#2558,.T.);
#2571=CARTESIAN_POINT('',(430.75,410.75,40.0010000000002));
#2572=DIRECTION('',(0.,0.,-1.));
#2573=DIRECTION('',(-1.,0.,0.));
#2574=AXIS2_PLACEMENT_3D('',#2571,#2572,#2573);
#2575=CYLINDRICAL_SURFACE('',#2574,1.00000000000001);
#2576=ORIENTED_EDGE('',*,*,#115,.T.);
#2577=DIRECTION('',(0.,0.,-1.));
#2578=VECTOR('',#2577,1.);
#2579=CARTESIAN_POINT('',(430.079132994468,411.491577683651,40.0010000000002));
#2580=LINE('',#2579,#2578);
#2581=EDGE_CURVE('E562',#105,#263,#2580,.T.);
#2582=ORIENTED_EDGE('',*,*,#2581,.T.);
#2583=ORIENTED_EDGE('',*,*,#264,.T.);
#2584=ORIENTED_EDGE('',*,*,#2563,.F.);
#2585=EDGE_LOOP('',(#2576,#2582,#2583,#2584));
#2586=FACE_BOUND('',#2585,.T.);
#2587=ADVANCED_FACE('F1851',(#2586),#2575,.F.);
#2588=CARTESIAN_POINT('',(-138.578011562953,980.148722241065,40.0010000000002));
#2589=DIRECTION('',(0.707106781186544,0.707106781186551,0.));
#2590=DIRECTION('',(-0.707106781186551,0.707106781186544,0.));
#2591=AXIS2_PLACEMENT_3D('',#2588,#2589,#2590);
#2592=PLANE('',#2591);
#2593=ORIENTED_EDGE('',*,*,#106,.T.);
#2594=DIRECTION('',(0.,0.,-1.));
#2595=VECTOR('',#2594,1.);
#2596=CARTESIAN_POINT('',(420.,421.570710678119,40.0010000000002));
#2597=LINE('',#2596,#2595);
#2598=EDGE_CURVE('E564',#97,#271,#2597,.T.);
#2599=ORIENTED_EDGE('',*,*,#2598,.T.);
#2600=ORIENTED_EDGE('',*,*,#272,.T.);
#2601=ORIENTED_EDGE('',*,*,#2581,.F.);
#2602=EDGE_LOOP('',(#2593,#2599,#2600,#2601));
#2603=FACE_BOUND('',#2602,.T.);
#2604=ADVANCED_FACE('F1871',(#2603),#2592,.F.);
#2605=CARTESIAN_POINT('',(420.,500.,40.0010000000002));
#2606=DIRECTION('',(1.,0.,0.));
#2607=DIRECTION('',(0.,0.,-1.));
#2608=AXIS2_PLACEMENT_3D('',#2605,#2606,#2607);
#2609=PLANE('',#2608);
#2610=ORIENTED_EDGE('',*,*,#98,.T.);
#2611=DIRECTION('',(0.,0.,-1.));
#2612=VECTOR('',#2611,1.);
#2613=CARTESIAN_POINT('',(420.,921.429289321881,40.0010000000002));
#2614=LINE('',#2613,#2612);
#2615=EDGE_CURVE('E566',#89,#279,#2614,.T.);
#2616=ORIENTED_EDGE('',*,*,#2615,.T.);
#2617=ORIENTED_EDGE('',*,*,#280,.T.);
#2618=ORIENTED_EDGE('',*,*,#2598,.F.);
#2619=EDGE_LOOP('',(#2610,#2616,#2617,#2618));
#2620=FACE_BOUND('',#2619,.T.);
#2621=ADVANCED_FACE('F1882',(#2620),#2609,.F.);
#2622=CARTESIAN_POINT('',(-310.07801156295,191.351277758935,40.0010000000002));
#2623=DIRECTION('',(-0.707106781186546,0.707106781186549,0.));
#2624=DIRECTION('',(-0.707106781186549,-0.707106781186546,0.));
#2625=AXIS2_PLACEMENT_3D('',#2622,#2623,#2624);
#2626=PLANE('',#2625);
#2627=DIRECTION('',(0.,0.,-1.));
#2628=VECTOR('',#2627,1.);
#2629=CARTESIAN_POINT('',(430.079132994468,931.508422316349,40.0010000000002));
#2630=LINE('',#2629,#2628);
#2631=EDGE_CURVE('E568',#81,#287,#2630,.T.);
#2632=ORIENTED_EDGE('',*,*,#2631,.T.);
#2633=ORIENTED_EDGE('',*,*,#288,.F.);
#2634=ORIENTED_EDGE('',*,*,#2615,.F.);
#2635=ORIENTED_EDGE('',*,*,#90,.F.);
#2636=EDGE_LOOP('',(#2632,#2633,#2634,#2635));
#2637=FACE_BOUND('',#2636,.T.);
#2638=ADVANCED_FACE('F1902',(#2637),#2626,.T.);
#2639=CARTESIAN_POINT('',(430.75,932.25,40.0010000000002));
#2640=DIRECTION('',(0.,0.,-1.));
#2641=DIRECTION('',(-1.,0.,0.));
#2642=AXIS2_PLACEMENT_3D('',#2639,#2640,#2641);
#2643=CYLINDRICAL_SURFACE('',#2642,0.999999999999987);
#2644=DIRECTION('',(0.,0.,-1.));
#2645=VECTOR('',#2644,1.);
#2646=CARTESIAN_POINT('',(430.008422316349,931.579132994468,40.0010000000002));
#2647=LINE('',#2646,#2645);
#2648=EDGE_CURVE('E570',#72,#296,#2647,.T.);
#2649=ORIENTED_EDGE('',*,*,#2648,.T.);
#2650=ORIENTED_EDGE('',*,*,#297,.F.);
#2651=ORIENTED_EDGE('',*,*,#2631,.F.);
#2652=ORIENTED_EDGE('',*,*,#82,.F.);
#2653=EDGE_LOOP('',(#2649,#2650,#2651,#2652));
#2654=FACE_BOUND('',#2653,.T.);
#2655=ADVANCED_FACE('F1913',(#2654),#2643,.F.);
#2656=CARTESIAN_POINT('',(-310.148722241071,191.421988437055,40.0010000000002));
#2657=DIRECTION('',(-0.707106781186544,0.707106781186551,0.));
#2658=DIRECTION('',(-0.707106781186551,-0.707106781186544,0.));
#2659=AXIS2_PLACEMENT_3D('',#2656,#2657,#2658);
#2660=PLANE('',#2659);
#2661=ORIENTED_EDGE('',*,*,#73,.T.);
#2662=DIRECTION('',(0.,0.,-1.));
#2663=VECTOR('',#2662,1.);
#2664=CARTESIAN_POINT('',(419.929289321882,921.5,40.0010000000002));
#2665=LINE('',#2664,#2663);
#2666=EDGE_CURVE('E572',#64,#304,#2665,.T.);
#2667=ORIENTED_EDGE('',*,*,#2666,.T.);
#2668=ORIENTED_EDGE('',*,*,#305,.T.);
#2669=ORIENTED_EDGE('',*,*,#2648,.F.);
#2670=EDGE_LOOP('',(#2661,#2667,#2668,#2669));
#2671=FACE_BOUND('',#2670,.T.);
#2672=ADVANCED_FACE('F1933',(#2671),#2660,.F.);
#2673=CARTESIAN_POINT('',(-618.726733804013,921.5,40.0010000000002));
#2674=DIRECTION('',(0.,-1.,0.));
#2675=DIRECTION('',(0.,0.,-1.));
#2676=AXIS2_PLACEMENT_3D('',#2673,#2674,#2675);
#2677=PLANE('',#2676);
#2678=DIRECTION('',(0.,0.,-1.));
#2679=VECTOR('',#2678,1.);
#2680=CARTESIAN_POINT('',(80.0707106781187,921.5,40.0010000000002));
#2681=LINE('',#2680,#2679);
#2682=EDGE_CURVE('E574',#56,#312,#2681,.T.);
#2683=ORIENTED_EDGE('',*,*,#2682,.T.);
#2684=ORIENTED_EDGE('',*,*,#313,.F.);
#2685=ORIENTED_EDGE('',*,*,#2666,.F.);
#2686=ORIENTED_EDGE('',*,*,#65,.F.);
#2687=EDGE_LOOP('',(#2683,#2684,#2685,#2686));
#2688=FACE_BOUND('',#2687,.T.);
#2689=ADVANCED_FACE('F1944',(#2688),#2677,.T.);
#2690=CARTESIAN_POINT('',(-58.5780115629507,1060.14872224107,40.0010000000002));
#2691=DIRECTION('',(-0.707106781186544,-0.707106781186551,0.));
#2692=DIRECTION('',(0.707106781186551,-0.707106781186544,0.));
#2693=AXIS2_PLACEMENT_3D('',#2690,#2691,#2692);
#2694=PLANE('',#2693);
#2695=DIRECTION('',(0.,0.,-1.));
#2696=VECTOR('',#2695,1.);
#2697=CARTESIAN_POINT('',(69.9915776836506,931.579132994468,40.0010000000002));
#2698=LINE('',#2697,#2696);
#2699=EDGE_CURVE('E486',#48,#320,#2698,.T.);
#2700=ORIENTED_EDGE('',*,*,#2699,.T.);
#2701=ORIENTED_EDGE('',*,*,#321,.F.);
#2702=ORIENTED_EDGE('',*,*,#2682,.F.);
#2703=ORIENTED_EDGE('',*,*,#57,.F.);
#2704=EDGE_LOOP('',(#2700,#2701,#2702,#2703));
#2705=FACE_BOUND('',#2704,.T.);
#2706=ADVANCED_FACE('F1964',(#2705),#2694,.T.);
#2707=CARTESIAN_POINT('',(69.2499999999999,932.25,40.0010000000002));
#2708=DIRECTION('',(0.,0.,-1.));
#2709=DIRECTION('',(-1.,0.,0.));
#2710=AXIS2_PLACEMENT_3D('',#2707,#2708,#2709);
#2711=CYLINDRICAL_SURFACE('',#2710,0.999999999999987);
#2712=ORIENTED_EDGE('',*,*,#49,.T.);
#2713=ORIENTED_EDGE('',*,*,#2464,.T.);
#2714=ORIENTED_EDGE('',*,*,#328,.T.);
#2715=ORIENTED_EDGE('',*,*,#2699,.F.);
#2716=EDGE_LOOP('',(#2712,#2713,#2714,#2715));
#2717=FACE_BOUND('',#2716,.T.);
#2718=ADVANCED_FACE('F491',(#2717),#2711,.F.);
#2719=CLOSED_SHELL('',(#192,#366,#404,#442,#459,#476,#507,#538,#555,#572,#610,#648,#665,#682,
#713,#744,#761,#778,#811,#844,#861,#878,#909,#940,#957,#974,#1007,#1040,#1057,#1074,#1105,#1136,
#1153,#1170,#1182,#1375,#1408,#1425,#1442,#1473,#1504,#1526,#1538,#1550,#1743,#1936,#1953,#1970,
#2001,#2032,#2054,#2066,#2078,#2111,#2304,#2321,#2338,#2369,#2400,#2422,#2434,#2446,#2468,#2485,
#2502,#2519,#2536,#2553,#2570,#2587,#2604,#2621,#2638,#2655,#2672,#2689,#2706,#2718));
#2720=MANIFOLD_SOLID_BREP('B2',#2719);
#2721=ADVANCED_BREP_SHAPE_REPRESENTATION('',(#18,#2720),#14);
#2722=SHAPE_DEFINITION_REPRESENTATION(#9,#2721);
ENDSEC;
END-ISO-10303-21;
